VERSION 5.8 ;
BUSBITCHARS "[]" ;
DIVIDERCHAR "/" ;
UNITS
    DATABASE MICRONS 1000 ;
END UNITS

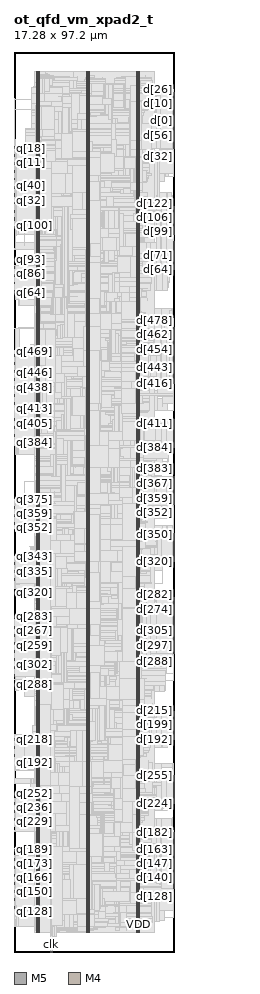
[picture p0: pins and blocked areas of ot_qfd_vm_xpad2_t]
MACRO ot_qfd_vm_xpad2_t
  FOREIGN ot_qfd_vm_xpad2_t 0 0 ;
  CLASS BLOCK ;
  SIZE 17.28 BY 97.2 ;
  PIN clk
    DIRECTION INPUT ;
    USE SIGNAL ;
    PORT
      LAYER M5 ;
        RECT  3.984 0 4.008 0.084 ;
    END
  END clk
  PIN d[0]
    DIRECTION INPUT ;
    USE SIGNAL ;
    PORT
      LAYER M4 ;
        RECT  17.196 89.808 17.28 89.832 ;
    END
  END d[0]
  PIN d[100]
    DIRECTION INPUT ;
    USE SIGNAL ;
    PORT
      LAYER M4 ;
        RECT  17.196 77.904 17.28 77.928 ;
    END
  END d[100]
  PIN d[101]
    DIRECTION INPUT ;
    USE SIGNAL ;
    PORT
      LAYER M4 ;
        RECT  17.196 78 17.28 78.024 ;
    END
  END d[101]
  PIN d[102]
    DIRECTION INPUT ;
    USE SIGNAL ;
    PORT
      LAYER M4 ;
        RECT  17.196 78.096 17.28 78.12 ;
    END
  END d[102]
  PIN d[103]
    DIRECTION INPUT ;
    USE SIGNAL ;
    PORT
      LAYER M4 ;
        RECT  17.196 78.192 17.28 78.216 ;
    END
  END d[103]
  PIN d[104]
    DIRECTION INPUT ;
    USE SIGNAL ;
    PORT
      LAYER M4 ;
        RECT  17.196 78.288 17.28 78.312 ;
    END
  END d[104]
  PIN d[105]
    DIRECTION INPUT ;
    USE SIGNAL ;
    PORT
      LAYER M4 ;
        RECT  17.196 78.384 17.28 78.408 ;
    END
  END d[105]
  PIN d[106]
    DIRECTION INPUT ;
    USE SIGNAL ;
    PORT
      LAYER M4 ;
        RECT  17.196 78.48 17.28 78.504 ;
    END
  END d[106]
  PIN d[107]
    DIRECTION INPUT ;
    USE SIGNAL ;
    PORT
      LAYER M4 ;
        RECT  17.196 78.576 17.28 78.6 ;
    END
  END d[107]
  PIN d[108]
    DIRECTION INPUT ;
    USE SIGNAL ;
    PORT
      LAYER M4 ;
        RECT  17.196 78.672 17.28 78.696 ;
    END
  END d[108]
  PIN d[109]
    DIRECTION INPUT ;
    USE SIGNAL ;
    PORT
      LAYER M4 ;
        RECT  17.196 78.768 17.28 78.792 ;
    END
  END d[109]
  PIN d[10]
    DIRECTION INPUT ;
    USE SIGNAL ;
    PORT
      LAYER M4 ;
        RECT  17.196 90.768 17.28 90.792 ;
    END
  END d[10]
  PIN d[110]
    DIRECTION INPUT ;
    USE SIGNAL ;
    PORT
      LAYER M4 ;
        RECT  17.196 78.864 17.28 78.888 ;
    END
  END d[110]
  PIN d[111]
    DIRECTION INPUT ;
    USE SIGNAL ;
    PORT
      LAYER M4 ;
        RECT  17.196 78.96 17.28 78.984 ;
    END
  END d[111]
  PIN d[112]
    DIRECTION INPUT ;
    USE SIGNAL ;
    PORT
      LAYER M4 ;
        RECT  17.196 79.056 17.28 79.08 ;
    END
  END d[112]
  PIN d[113]
    DIRECTION INPUT ;
    USE SIGNAL ;
    PORT
      LAYER M4 ;
        RECT  17.196 79.152 17.28 79.176 ;
    END
  END d[113]
  PIN d[114]
    DIRECTION INPUT ;
    USE SIGNAL ;
    PORT
      LAYER M4 ;
        RECT  17.196 79.248 17.28 79.272 ;
    END
  END d[114]
  PIN d[115]
    DIRECTION INPUT ;
    USE SIGNAL ;
    PORT
      LAYER M4 ;
        RECT  17.196 79.344 17.28 79.368 ;
    END
  END d[115]
  PIN d[116]
    DIRECTION INPUT ;
    USE SIGNAL ;
    PORT
      LAYER M4 ;
        RECT  17.196 79.44 17.28 79.464 ;
    END
  END d[116]
  PIN d[117]
    DIRECTION INPUT ;
    USE SIGNAL ;
    PORT
      LAYER M4 ;
        RECT  17.196 79.536 17.28 79.56 ;
    END
  END d[117]
  PIN d[118]
    DIRECTION INPUT ;
    USE SIGNAL ;
    PORT
      LAYER M4 ;
        RECT  17.196 79.632 17.28 79.656 ;
    END
  END d[118]
  PIN d[119]
    DIRECTION INPUT ;
    USE SIGNAL ;
    PORT
      LAYER M4 ;
        RECT  17.196 79.728 17.28 79.752 ;
    END
  END d[119]
  PIN d[11]
    DIRECTION INPUT ;
    USE SIGNAL ;
    PORT
      LAYER M4 ;
        RECT  17.196 90.864 17.28 90.888 ;
    END
  END d[11]
  PIN d[120]
    DIRECTION INPUT ;
    USE SIGNAL ;
    PORT
      LAYER M4 ;
        RECT  17.196 79.824 17.28 79.848 ;
    END
  END d[120]
  PIN d[121]
    DIRECTION INPUT ;
    USE SIGNAL ;
    PORT
      LAYER M4 ;
        RECT  17.196 79.92 17.28 79.944 ;
    END
  END d[121]
  PIN d[122]
    DIRECTION INPUT ;
    USE SIGNAL ;
    PORT
      LAYER M4 ;
        RECT  17.196 80.016 17.28 80.04 ;
    END
  END d[122]
  PIN d[123]
    DIRECTION INPUT ;
    USE SIGNAL ;
    PORT
      LAYER M4 ;
        RECT  17.196 80.112 17.28 80.136 ;
    END
  END d[123]
  PIN d[124]
    DIRECTION INPUT ;
    USE SIGNAL ;
    PORT
      LAYER M4 ;
        RECT  17.196 80.208 17.28 80.232 ;
    END
  END d[124]
  PIN d[125]
    DIRECTION INPUT ;
    USE SIGNAL ;
    PORT
      LAYER M4 ;
        RECT  17.196 80.304 17.28 80.328 ;
    END
  END d[125]
  PIN d[126]
    DIRECTION INPUT ;
    USE SIGNAL ;
    PORT
      LAYER M4 ;
        RECT  17.196 80.4 17.28 80.424 ;
    END
  END d[126]
  PIN d[127]
    DIRECTION INPUT ;
    USE SIGNAL ;
    PORT
      LAYER M4 ;
        RECT  17.196 80.496 17.28 80.52 ;
    END
  END d[127]
  PIN d[128]
    DIRECTION INPUT ;
    USE SIGNAL ;
    PORT
      LAYER M4 ;
        RECT  17.196 6.864 17.28 6.888 ;
    END
  END d[128]
  PIN d[129]
    DIRECTION INPUT ;
    USE SIGNAL ;
    PORT
      LAYER M4 ;
        RECT  17.196 6.96 17.28 6.984 ;
    END
  END d[129]
  PIN d[12]
    DIRECTION INPUT ;
    USE SIGNAL ;
    PORT
      LAYER M4 ;
        RECT  17.196 90.96 17.28 90.984 ;
    END
  END d[12]
  PIN d[130]
    DIRECTION INPUT ;
    USE SIGNAL ;
    PORT
      LAYER M4 ;
        RECT  17.196 7.056 17.28 7.08 ;
    END
  END d[130]
  PIN d[131]
    DIRECTION INPUT ;
    USE SIGNAL ;
    PORT
      LAYER M4 ;
        RECT  17.196 7.152 17.28 7.176 ;
    END
  END d[131]
  PIN d[132]
    DIRECTION INPUT ;
    USE SIGNAL ;
    PORT
      LAYER M4 ;
        RECT  17.196 7.248 17.28 7.272 ;
    END
  END d[132]
  PIN d[133]
    DIRECTION INPUT ;
    USE SIGNAL ;
    PORT
      LAYER M4 ;
        RECT  17.196 7.344 17.28 7.368 ;
    END
  END d[133]
  PIN d[134]
    DIRECTION INPUT ;
    USE SIGNAL ;
    PORT
      LAYER M4 ;
        RECT  17.196 7.44 17.28 7.464 ;
    END
  END d[134]
  PIN d[135]
    DIRECTION INPUT ;
    USE SIGNAL ;
    PORT
      LAYER M4 ;
        RECT  17.196 7.536 17.28 7.56 ;
    END
  END d[135]
  PIN d[136]
    DIRECTION INPUT ;
    USE SIGNAL ;
    PORT
      LAYER M4 ;
        RECT  17.196 7.632 17.28 7.656 ;
    END
  END d[136]
  PIN d[137]
    DIRECTION INPUT ;
    USE SIGNAL ;
    PORT
      LAYER M4 ;
        RECT  17.196 7.728 17.28 7.752 ;
    END
  END d[137]
  PIN d[138]
    DIRECTION INPUT ;
    USE SIGNAL ;
    PORT
      LAYER M4 ;
        RECT  17.196 7.824 17.28 7.848 ;
    END
  END d[138]
  PIN d[139]
    DIRECTION INPUT ;
    USE SIGNAL ;
    PORT
      LAYER M4 ;
        RECT  17.196 7.92 17.28 7.944 ;
    END
  END d[139]
  PIN d[13]
    DIRECTION INPUT ;
    USE SIGNAL ;
    PORT
      LAYER M4 ;
        RECT  17.196 91.056 17.28 91.08 ;
    END
  END d[13]
  PIN d[140]
    DIRECTION INPUT ;
    USE SIGNAL ;
    PORT
      LAYER M4 ;
        RECT  17.196 8.016 17.28 8.04 ;
    END
  END d[140]
  PIN d[141]
    DIRECTION INPUT ;
    USE SIGNAL ;
    PORT
      LAYER M4 ;
        RECT  17.196 8.112 17.28 8.136 ;
    END
  END d[141]
  PIN d[142]
    DIRECTION INPUT ;
    USE SIGNAL ;
    PORT
      LAYER M4 ;
        RECT  17.196 8.208 17.28 8.232 ;
    END
  END d[142]
  PIN d[143]
    DIRECTION INPUT ;
    USE SIGNAL ;
    PORT
      LAYER M4 ;
        RECT  17.196 8.304 17.28 8.328 ;
    END
  END d[143]
  PIN d[144]
    DIRECTION INPUT ;
    USE SIGNAL ;
    PORT
      LAYER M4 ;
        RECT  17.196 8.4 17.28 8.424 ;
    END
  END d[144]
  PIN d[145]
    DIRECTION INPUT ;
    USE SIGNAL ;
    PORT
      LAYER M4 ;
        RECT  17.196 8.496 17.28 8.52 ;
    END
  END d[145]
  PIN d[146]
    DIRECTION INPUT ;
    USE SIGNAL ;
    PORT
      LAYER M4 ;
        RECT  17.196 8.592 17.28 8.616 ;
    END
  END d[146]
  PIN d[147]
    DIRECTION INPUT ;
    USE SIGNAL ;
    PORT
      LAYER M4 ;
        RECT  17.196 8.688 17.28 8.712 ;
    END
  END d[147]
  PIN d[148]
    DIRECTION INPUT ;
    USE SIGNAL ;
    PORT
      LAYER M4 ;
        RECT  17.196 8.784 17.28 8.808 ;
    END
  END d[148]
  PIN d[149]
    DIRECTION INPUT ;
    USE SIGNAL ;
    PORT
      LAYER M4 ;
        RECT  17.196 8.88 17.28 8.904 ;
    END
  END d[149]
  PIN d[14]
    DIRECTION INPUT ;
    USE SIGNAL ;
    PORT
      LAYER M4 ;
        RECT  17.196 91.152 17.28 91.176 ;
    END
  END d[14]
  PIN d[150]
    DIRECTION INPUT ;
    USE SIGNAL ;
    PORT
      LAYER M4 ;
        RECT  17.196 8.976 17.28 9 ;
    END
  END d[150]
  PIN d[151]
    DIRECTION INPUT ;
    USE SIGNAL ;
    PORT
      LAYER M4 ;
        RECT  17.196 9.072 17.28 9.096 ;
    END
  END d[151]
  PIN d[152]
    DIRECTION INPUT ;
    USE SIGNAL ;
    PORT
      LAYER M4 ;
        RECT  17.196 9.168 17.28 9.192 ;
    END
  END d[152]
  PIN d[153]
    DIRECTION INPUT ;
    USE SIGNAL ;
    PORT
      LAYER M4 ;
        RECT  17.196 9.264 17.28 9.288 ;
    END
  END d[153]
  PIN d[154]
    DIRECTION INPUT ;
    USE SIGNAL ;
    PORT
      LAYER M4 ;
        RECT  17.196 9.36 17.28 9.384 ;
    END
  END d[154]
  PIN d[155]
    DIRECTION INPUT ;
    USE SIGNAL ;
    PORT
      LAYER M4 ;
        RECT  17.196 9.456 17.28 9.48 ;
    END
  END d[155]
  PIN d[156]
    DIRECTION INPUT ;
    USE SIGNAL ;
    PORT
      LAYER M4 ;
        RECT  17.196 9.552 17.28 9.576 ;
    END
  END d[156]
  PIN d[157]
    DIRECTION INPUT ;
    USE SIGNAL ;
    PORT
      LAYER M4 ;
        RECT  17.196 9.648 17.28 9.672 ;
    END
  END d[157]
  PIN d[158]
    DIRECTION INPUT ;
    USE SIGNAL ;
    PORT
      LAYER M4 ;
        RECT  17.196 9.744 17.28 9.768 ;
    END
  END d[158]
  PIN d[159]
    DIRECTION INPUT ;
    USE SIGNAL ;
    PORT
      LAYER M4 ;
        RECT  17.196 9.84 17.28 9.864 ;
    END
  END d[159]
  PIN d[15]
    DIRECTION INPUT ;
    USE SIGNAL ;
    PORT
      LAYER M4 ;
        RECT  17.196 91.248 17.28 91.272 ;
    END
  END d[15]
  PIN d[160]
    DIRECTION INPUT ;
    USE SIGNAL ;
    PORT
      LAYER M4 ;
        RECT  17.196 9.936 17.28 9.96 ;
    END
  END d[160]
  PIN d[161]
    DIRECTION INPUT ;
    USE SIGNAL ;
    PORT
      LAYER M4 ;
        RECT  17.196 10.032 17.28 10.056 ;
    END
  END d[161]
  PIN d[162]
    DIRECTION INPUT ;
    USE SIGNAL ;
    PORT
      LAYER M4 ;
        RECT  17.196 10.128 17.28 10.152 ;
    END
  END d[162]
  PIN d[163]
    DIRECTION INPUT ;
    USE SIGNAL ;
    PORT
      LAYER M4 ;
        RECT  17.196 10.224 17.28 10.248 ;
    END
  END d[163]
  PIN d[164]
    DIRECTION INPUT ;
    USE SIGNAL ;
    PORT
      LAYER M4 ;
        RECT  17.196 10.32 17.28 10.344 ;
    END
  END d[164]
  PIN d[165]
    DIRECTION INPUT ;
    USE SIGNAL ;
    PORT
      LAYER M4 ;
        RECT  17.196 10.416 17.28 10.44 ;
    END
  END d[165]
  PIN d[166]
    DIRECTION INPUT ;
    USE SIGNAL ;
    PORT
      LAYER M4 ;
        RECT  17.196 10.512 17.28 10.536 ;
    END
  END d[166]
  PIN d[167]
    DIRECTION INPUT ;
    USE SIGNAL ;
    PORT
      LAYER M4 ;
        RECT  17.196 10.608 17.28 10.632 ;
    END
  END d[167]
  PIN d[168]
    DIRECTION INPUT ;
    USE SIGNAL ;
    PORT
      LAYER M4 ;
        RECT  17.196 10.704 17.28 10.728 ;
    END
  END d[168]
  PIN d[169]
    DIRECTION INPUT ;
    USE SIGNAL ;
    PORT
      LAYER M4 ;
        RECT  17.196 10.8 17.28 10.824 ;
    END
  END d[169]
  PIN d[16]
    DIRECTION INPUT ;
    USE SIGNAL ;
    PORT
      LAYER M4 ;
        RECT  17.196 91.344 17.28 91.368 ;
    END
  END d[16]
  PIN d[170]
    DIRECTION INPUT ;
    USE SIGNAL ;
    PORT
      LAYER M4 ;
        RECT  17.196 10.896 17.28 10.92 ;
    END
  END d[170]
  PIN d[171]
    DIRECTION INPUT ;
    USE SIGNAL ;
    PORT
      LAYER M4 ;
        RECT  17.196 10.992 17.28 11.016 ;
    END
  END d[171]
  PIN d[172]
    DIRECTION INPUT ;
    USE SIGNAL ;
    PORT
      LAYER M4 ;
        RECT  17.196 11.088 17.28 11.112 ;
    END
  END d[172]
  PIN d[173]
    DIRECTION INPUT ;
    USE SIGNAL ;
    PORT
      LAYER M4 ;
        RECT  17.196 11.184 17.28 11.208 ;
    END
  END d[173]
  PIN d[174]
    DIRECTION INPUT ;
    USE SIGNAL ;
    PORT
      LAYER M4 ;
        RECT  17.196 11.28 17.28 11.304 ;
    END
  END d[174]
  PIN d[175]
    DIRECTION INPUT ;
    USE SIGNAL ;
    PORT
      LAYER M4 ;
        RECT  17.196 11.376 17.28 11.4 ;
    END
  END d[175]
  PIN d[176]
    DIRECTION INPUT ;
    USE SIGNAL ;
    PORT
      LAYER M4 ;
        RECT  17.196 11.472 17.28 11.496 ;
    END
  END d[176]
  PIN d[177]
    DIRECTION INPUT ;
    USE SIGNAL ;
    PORT
      LAYER M4 ;
        RECT  17.196 11.568 17.28 11.592 ;
    END
  END d[177]
  PIN d[178]
    DIRECTION INPUT ;
    USE SIGNAL ;
    PORT
      LAYER M4 ;
        RECT  17.196 11.664 17.28 11.688 ;
    END
  END d[178]
  PIN d[179]
    DIRECTION INPUT ;
    USE SIGNAL ;
    PORT
      LAYER M4 ;
        RECT  17.196 11.76 17.28 11.784 ;
    END
  END d[179]
  PIN d[17]
    DIRECTION INPUT ;
    USE SIGNAL ;
    PORT
      LAYER M4 ;
        RECT  17.196 91.44 17.28 91.464 ;
    END
  END d[17]
  PIN d[180]
    DIRECTION INPUT ;
    USE SIGNAL ;
    PORT
      LAYER M4 ;
        RECT  17.196 11.856 17.28 11.88 ;
    END
  END d[180]
  PIN d[181]
    DIRECTION INPUT ;
    USE SIGNAL ;
    PORT
      LAYER M4 ;
        RECT  17.196 11.952 17.28 11.976 ;
    END
  END d[181]
  PIN d[182]
    DIRECTION INPUT ;
    USE SIGNAL ;
    PORT
      LAYER M4 ;
        RECT  17.196 12.048 17.28 12.072 ;
    END
  END d[182]
  PIN d[183]
    DIRECTION INPUT ;
    USE SIGNAL ;
    PORT
      LAYER M4 ;
        RECT  17.196 12.144 17.28 12.168 ;
    END
  END d[183]
  PIN d[184]
    DIRECTION INPUT ;
    USE SIGNAL ;
    PORT
      LAYER M4 ;
        RECT  17.196 12.24 17.28 12.264 ;
    END
  END d[184]
  PIN d[185]
    DIRECTION INPUT ;
    USE SIGNAL ;
    PORT
      LAYER M4 ;
        RECT  17.196 12.336 17.28 12.36 ;
    END
  END d[185]
  PIN d[186]
    DIRECTION INPUT ;
    USE SIGNAL ;
    PORT
      LAYER M4 ;
        RECT  17.196 12.432 17.28 12.456 ;
    END
  END d[186]
  PIN d[187]
    DIRECTION INPUT ;
    USE SIGNAL ;
    PORT
      LAYER M4 ;
        RECT  17.196 12.528 17.28 12.552 ;
    END
  END d[187]
  PIN d[188]
    DIRECTION INPUT ;
    USE SIGNAL ;
    PORT
      LAYER M4 ;
        RECT  17.196 12.624 17.28 12.648 ;
    END
  END d[188]
  PIN d[189]
    DIRECTION INPUT ;
    USE SIGNAL ;
    PORT
      LAYER M4 ;
        RECT  17.196 12.72 17.28 12.744 ;
    END
  END d[189]
  PIN d[18]
    DIRECTION INPUT ;
    USE SIGNAL ;
    PORT
      LAYER M4 ;
        RECT  17.196 91.536 17.28 91.56 ;
    END
  END d[18]
  PIN d[190]
    DIRECTION INPUT ;
    USE SIGNAL ;
    PORT
      LAYER M4 ;
        RECT  17.196 12.816 17.28 12.84 ;
    END
  END d[190]
  PIN d[191]
    DIRECTION INPUT ;
    USE SIGNAL ;
    PORT
      LAYER M4 ;
        RECT  17.196 12.912 17.28 12.936 ;
    END
  END d[191]
  PIN d[192]
    DIRECTION INPUT ;
    USE SIGNAL ;
    PORT
      LAYER M4 ;
        RECT  17.196 22.992 17.28 23.016 ;
    END
  END d[192]
  PIN d[193]
    DIRECTION INPUT ;
    USE SIGNAL ;
    PORT
      LAYER M4 ;
        RECT  17.196 23.088 17.28 23.112 ;
    END
  END d[193]
  PIN d[194]
    DIRECTION INPUT ;
    USE SIGNAL ;
    PORT
      LAYER M4 ;
        RECT  17.196 23.184 17.28 23.208 ;
    END
  END d[194]
  PIN d[195]
    DIRECTION INPUT ;
    USE SIGNAL ;
    PORT
      LAYER M4 ;
        RECT  17.196 23.28 17.28 23.304 ;
    END
  END d[195]
  PIN d[196]
    DIRECTION INPUT ;
    USE SIGNAL ;
    PORT
      LAYER M4 ;
        RECT  17.196 23.376 17.28 23.4 ;
    END
  END d[196]
  PIN d[197]
    DIRECTION INPUT ;
    USE SIGNAL ;
    PORT
      LAYER M4 ;
        RECT  17.196 23.472 17.28 23.496 ;
    END
  END d[197]
  PIN d[198]
    DIRECTION INPUT ;
    USE SIGNAL ;
    PORT
      LAYER M4 ;
        RECT  17.196 23.568 17.28 23.592 ;
    END
  END d[198]
  PIN d[199]
    DIRECTION INPUT ;
    USE SIGNAL ;
    PORT
      LAYER M4 ;
        RECT  17.196 23.664 17.28 23.688 ;
    END
  END d[199]
  PIN d[19]
    DIRECTION INPUT ;
    USE SIGNAL ;
    PORT
      LAYER M4 ;
        RECT  17.196 91.632 17.28 91.656 ;
    END
  END d[19]
  PIN d[1]
    DIRECTION INPUT ;
    USE SIGNAL ;
    PORT
      LAYER M4 ;
        RECT  17.196 89.904 17.28 89.928 ;
    END
  END d[1]
  PIN d[200]
    DIRECTION INPUT ;
    USE SIGNAL ;
    PORT
      LAYER M4 ;
        RECT  17.196 23.76 17.28 23.784 ;
    END
  END d[200]
  PIN d[201]
    DIRECTION INPUT ;
    USE SIGNAL ;
    PORT
      LAYER M4 ;
        RECT  17.196 23.856 17.28 23.88 ;
    END
  END d[201]
  PIN d[202]
    DIRECTION INPUT ;
    USE SIGNAL ;
    PORT
      LAYER M4 ;
        RECT  17.196 23.952 17.28 23.976 ;
    END
  END d[202]
  PIN d[203]
    DIRECTION INPUT ;
    USE SIGNAL ;
    PORT
      LAYER M4 ;
        RECT  17.196 24.048 17.28 24.072 ;
    END
  END d[203]
  PIN d[204]
    DIRECTION INPUT ;
    USE SIGNAL ;
    PORT
      LAYER M4 ;
        RECT  17.196 24.144 17.28 24.168 ;
    END
  END d[204]
  PIN d[205]
    DIRECTION INPUT ;
    USE SIGNAL ;
    PORT
      LAYER M4 ;
        RECT  17.196 24.24 17.28 24.264 ;
    END
  END d[205]
  PIN d[206]
    DIRECTION INPUT ;
    USE SIGNAL ;
    PORT
      LAYER M4 ;
        RECT  17.196 24.336 17.28 24.36 ;
    END
  END d[206]
  PIN d[207]
    DIRECTION INPUT ;
    USE SIGNAL ;
    PORT
      LAYER M4 ;
        RECT  17.196 24.432 17.28 24.456 ;
    END
  END d[207]
  PIN d[208]
    DIRECTION INPUT ;
    USE SIGNAL ;
    PORT
      LAYER M4 ;
        RECT  17.196 24.528 17.28 24.552 ;
    END
  END d[208]
  PIN d[209]
    DIRECTION INPUT ;
    USE SIGNAL ;
    PORT
      LAYER M4 ;
        RECT  17.196 24.624 17.28 24.648 ;
    END
  END d[209]
  PIN d[20]
    DIRECTION INPUT ;
    USE SIGNAL ;
    PORT
      LAYER M4 ;
        RECT  17.196 91.728 17.28 91.752 ;
    END
  END d[20]
  PIN d[210]
    DIRECTION INPUT ;
    USE SIGNAL ;
    PORT
      LAYER M4 ;
        RECT  17.196 24.72 17.28 24.744 ;
    END
  END d[210]
  PIN d[211]
    DIRECTION INPUT ;
    USE SIGNAL ;
    PORT
      LAYER M4 ;
        RECT  17.196 24.816 17.28 24.84 ;
    END
  END d[211]
  PIN d[212]
    DIRECTION INPUT ;
    USE SIGNAL ;
    PORT
      LAYER M4 ;
        RECT  17.196 24.912 17.28 24.936 ;
    END
  END d[212]
  PIN d[213]
    DIRECTION INPUT ;
    USE SIGNAL ;
    PORT
      LAYER M4 ;
        RECT  17.196 25.008 17.28 25.032 ;
    END
  END d[213]
  PIN d[214]
    DIRECTION INPUT ;
    USE SIGNAL ;
    PORT
      LAYER M4 ;
        RECT  17.196 25.104 17.28 25.128 ;
    END
  END d[214]
  PIN d[215]
    DIRECTION INPUT ;
    USE SIGNAL ;
    PORT
      LAYER M4 ;
        RECT  17.196 25.2 17.28 25.224 ;
    END
  END d[215]
  PIN d[216]
    DIRECTION INPUT ;
    USE SIGNAL ;
    PORT
      LAYER M4 ;
        RECT  17.196 25.296 17.28 25.32 ;
    END
  END d[216]
  PIN d[217]
    DIRECTION INPUT ;
    USE SIGNAL ;
    PORT
      LAYER M4 ;
        RECT  17.196 25.392 17.28 25.416 ;
    END
  END d[217]
  PIN d[218]
    DIRECTION INPUT ;
    USE SIGNAL ;
    PORT
      LAYER M4 ;
        RECT  17.196 25.488 17.28 25.512 ;
    END
  END d[218]
  PIN d[219]
    DIRECTION INPUT ;
    USE SIGNAL ;
    PORT
      LAYER M4 ;
        RECT  17.196 25.584 17.28 25.608 ;
    END
  END d[219]
  PIN d[21]
    DIRECTION INPUT ;
    USE SIGNAL ;
    PORT
      LAYER M4 ;
        RECT  17.196 91.824 17.28 91.848 ;
    END
  END d[21]
  PIN d[220]
    DIRECTION INPUT ;
    USE SIGNAL ;
    PORT
      LAYER M4 ;
        RECT  17.196 25.68 17.28 25.704 ;
    END
  END d[220]
  PIN d[221]
    DIRECTION INPUT ;
    USE SIGNAL ;
    PORT
      LAYER M4 ;
        RECT  17.196 25.776 17.28 25.8 ;
    END
  END d[221]
  PIN d[222]
    DIRECTION INPUT ;
    USE SIGNAL ;
    PORT
      LAYER M4 ;
        RECT  17.196 25.872 17.28 25.896 ;
    END
  END d[222]
  PIN d[223]
    DIRECTION INPUT ;
    USE SIGNAL ;
    PORT
      LAYER M4 ;
        RECT  17.196 25.968 17.28 25.992 ;
    END
  END d[223]
  PIN d[224]
    DIRECTION INPUT ;
    USE SIGNAL ;
    PORT
      LAYER M4 ;
        RECT  17.196 16.08 17.28 16.104 ;
    END
  END d[224]
  PIN d[225]
    DIRECTION INPUT ;
    USE SIGNAL ;
    PORT
      LAYER M4 ;
        RECT  17.196 16.176 17.28 16.2 ;
    END
  END d[225]
  PIN d[226]
    DIRECTION INPUT ;
    USE SIGNAL ;
    PORT
      LAYER M4 ;
        RECT  17.196 16.272 17.28 16.296 ;
    END
  END d[226]
  PIN d[227]
    DIRECTION INPUT ;
    USE SIGNAL ;
    PORT
      LAYER M4 ;
        RECT  17.196 16.368 17.28 16.392 ;
    END
  END d[227]
  PIN d[228]
    DIRECTION INPUT ;
    USE SIGNAL ;
    PORT
      LAYER M4 ;
        RECT  17.196 16.464 17.28 16.488 ;
    END
  END d[228]
  PIN d[229]
    DIRECTION INPUT ;
    USE SIGNAL ;
    PORT
      LAYER M4 ;
        RECT  17.196 16.56 17.28 16.584 ;
    END
  END d[229]
  PIN d[22]
    DIRECTION INPUT ;
    USE SIGNAL ;
    PORT
      LAYER M4 ;
        RECT  17.196 91.92 17.28 91.944 ;
    END
  END d[22]
  PIN d[230]
    DIRECTION INPUT ;
    USE SIGNAL ;
    PORT
      LAYER M4 ;
        RECT  17.196 16.656 17.28 16.68 ;
    END
  END d[230]
  PIN d[231]
    DIRECTION INPUT ;
    USE SIGNAL ;
    PORT
      LAYER M4 ;
        RECT  17.196 16.752 17.28 16.776 ;
    END
  END d[231]
  PIN d[232]
    DIRECTION INPUT ;
    USE SIGNAL ;
    PORT
      LAYER M4 ;
        RECT  17.196 16.848 17.28 16.872 ;
    END
  END d[232]
  PIN d[233]
    DIRECTION INPUT ;
    USE SIGNAL ;
    PORT
      LAYER M4 ;
        RECT  17.196 16.944 17.28 16.968 ;
    END
  END d[233]
  PIN d[234]
    DIRECTION INPUT ;
    USE SIGNAL ;
    PORT
      LAYER M4 ;
        RECT  17.196 17.04 17.28 17.064 ;
    END
  END d[234]
  PIN d[235]
    DIRECTION INPUT ;
    USE SIGNAL ;
    PORT
      LAYER M4 ;
        RECT  17.196 17.136 17.28 17.16 ;
    END
  END d[235]
  PIN d[236]
    DIRECTION INPUT ;
    USE SIGNAL ;
    PORT
      LAYER M4 ;
        RECT  17.196 17.232 17.28 17.256 ;
    END
  END d[236]
  PIN d[237]
    DIRECTION INPUT ;
    USE SIGNAL ;
    PORT
      LAYER M4 ;
        RECT  17.196 17.328 17.28 17.352 ;
    END
  END d[237]
  PIN d[238]
    DIRECTION INPUT ;
    USE SIGNAL ;
    PORT
      LAYER M4 ;
        RECT  17.196 17.424 17.28 17.448 ;
    END
  END d[238]
  PIN d[239]
    DIRECTION INPUT ;
    USE SIGNAL ;
    PORT
      LAYER M4 ;
        RECT  17.196 17.52 17.28 17.544 ;
    END
  END d[239]
  PIN d[23]
    DIRECTION INPUT ;
    USE SIGNAL ;
    PORT
      LAYER M4 ;
        RECT  17.196 92.016 17.28 92.04 ;
    END
  END d[23]
  PIN d[240]
    DIRECTION INPUT ;
    USE SIGNAL ;
    PORT
      LAYER M4 ;
        RECT  17.196 17.616 17.28 17.64 ;
    END
  END d[240]
  PIN d[241]
    DIRECTION INPUT ;
    USE SIGNAL ;
    PORT
      LAYER M4 ;
        RECT  17.196 17.712 17.28 17.736 ;
    END
  END d[241]
  PIN d[242]
    DIRECTION INPUT ;
    USE SIGNAL ;
    PORT
      LAYER M4 ;
        RECT  17.196 17.808 17.28 17.832 ;
    END
  END d[242]
  PIN d[243]
    DIRECTION INPUT ;
    USE SIGNAL ;
    PORT
      LAYER M4 ;
        RECT  17.196 17.904 17.28 17.928 ;
    END
  END d[243]
  PIN d[244]
    DIRECTION INPUT ;
    USE SIGNAL ;
    PORT
      LAYER M4 ;
        RECT  17.196 18 17.28 18.024 ;
    END
  END d[244]
  PIN d[245]
    DIRECTION INPUT ;
    USE SIGNAL ;
    PORT
      LAYER M4 ;
        RECT  17.196 18.096 17.28 18.12 ;
    END
  END d[245]
  PIN d[246]
    DIRECTION INPUT ;
    USE SIGNAL ;
    PORT
      LAYER M4 ;
        RECT  17.196 18.192 17.28 18.216 ;
    END
  END d[246]
  PIN d[247]
    DIRECTION INPUT ;
    USE SIGNAL ;
    PORT
      LAYER M4 ;
        RECT  17.196 18.288 17.28 18.312 ;
    END
  END d[247]
  PIN d[248]
    DIRECTION INPUT ;
    USE SIGNAL ;
    PORT
      LAYER M4 ;
        RECT  17.196 18.384 17.28 18.408 ;
    END
  END d[248]
  PIN d[249]
    DIRECTION INPUT ;
    USE SIGNAL ;
    PORT
      LAYER M4 ;
        RECT  17.196 18.48 17.28 18.504 ;
    END
  END d[249]
  PIN d[24]
    DIRECTION INPUT ;
    USE SIGNAL ;
    PORT
      LAYER M4 ;
        RECT  17.196 92.112 17.28 92.136 ;
    END
  END d[24]
  PIN d[250]
    DIRECTION INPUT ;
    USE SIGNAL ;
    PORT
      LAYER M4 ;
        RECT  17.196 18.576 17.28 18.6 ;
    END
  END d[250]
  PIN d[251]
    DIRECTION INPUT ;
    USE SIGNAL ;
    PORT
      LAYER M4 ;
        RECT  17.196 18.672 17.28 18.696 ;
    END
  END d[251]
  PIN d[252]
    DIRECTION INPUT ;
    USE SIGNAL ;
    PORT
      LAYER M4 ;
        RECT  17.196 18.768 17.28 18.792 ;
    END
  END d[252]
  PIN d[253]
    DIRECTION INPUT ;
    USE SIGNAL ;
    PORT
      LAYER M4 ;
        RECT  17.196 18.864 17.28 18.888 ;
    END
  END d[253]
  PIN d[254]
    DIRECTION INPUT ;
    USE SIGNAL ;
    PORT
      LAYER M4 ;
        RECT  17.196 18.96 17.28 18.984 ;
    END
  END d[254]
  PIN d[255]
    DIRECTION INPUT ;
    USE SIGNAL ;
    PORT
      LAYER M4 ;
        RECT  17.196 19.056 17.28 19.08 ;
    END
  END d[255]
  PIN d[256]
    DIRECTION INPUT ;
    USE SIGNAL ;
    PORT
      LAYER M4 ;
        RECT  17.196 35.28 17.28 35.304 ;
    END
  END d[256]
  PIN d[257]
    DIRECTION INPUT ;
    USE SIGNAL ;
    PORT
      LAYER M4 ;
        RECT  17.196 35.376 17.28 35.4 ;
    END
  END d[257]
  PIN d[258]
    DIRECTION INPUT ;
    USE SIGNAL ;
    PORT
      LAYER M4 ;
        RECT  17.196 35.472 17.28 35.496 ;
    END
  END d[258]
  PIN d[259]
    DIRECTION INPUT ;
    USE SIGNAL ;
    PORT
      LAYER M4 ;
        RECT  17.196 35.568 17.28 35.592 ;
    END
  END d[259]
  PIN d[25]
    DIRECTION INPUT ;
    USE SIGNAL ;
    PORT
      LAYER M4 ;
        RECT  17.196 92.208 17.28 92.232 ;
    END
  END d[25]
  PIN d[260]
    DIRECTION INPUT ;
    USE SIGNAL ;
    PORT
      LAYER M4 ;
        RECT  17.196 35.664 17.28 35.688 ;
    END
  END d[260]
  PIN d[261]
    DIRECTION INPUT ;
    USE SIGNAL ;
    PORT
      LAYER M4 ;
        RECT  17.196 35.76 17.28 35.784 ;
    END
  END d[261]
  PIN d[262]
    DIRECTION INPUT ;
    USE SIGNAL ;
    PORT
      LAYER M4 ;
        RECT  17.196 35.856 17.28 35.88 ;
    END
  END d[262]
  PIN d[263]
    DIRECTION INPUT ;
    USE SIGNAL ;
    PORT
      LAYER M4 ;
        RECT  17.196 35.952 17.28 35.976 ;
    END
  END d[263]
  PIN d[264]
    DIRECTION INPUT ;
    USE SIGNAL ;
    PORT
      LAYER M4 ;
        RECT  17.196 36.048 17.28 36.072 ;
    END
  END d[264]
  PIN d[265]
    DIRECTION INPUT ;
    USE SIGNAL ;
    PORT
      LAYER M4 ;
        RECT  17.196 36.144 17.28 36.168 ;
    END
  END d[265]
  PIN d[266]
    DIRECTION INPUT ;
    USE SIGNAL ;
    PORT
      LAYER M4 ;
        RECT  17.196 36.24 17.28 36.264 ;
    END
  END d[266]
  PIN d[267]
    DIRECTION INPUT ;
    USE SIGNAL ;
    PORT
      LAYER M4 ;
        RECT  17.196 36.336 17.28 36.36 ;
    END
  END d[267]
  PIN d[268]
    DIRECTION INPUT ;
    USE SIGNAL ;
    PORT
      LAYER M4 ;
        RECT  17.196 36.432 17.28 36.456 ;
    END
  END d[268]
  PIN d[269]
    DIRECTION INPUT ;
    USE SIGNAL ;
    PORT
      LAYER M4 ;
        RECT  17.196 36.528 17.28 36.552 ;
    END
  END d[269]
  PIN d[26]
    DIRECTION INPUT ;
    USE SIGNAL ;
    PORT
      LAYER M4 ;
        RECT  17.196 92.304 17.28 92.328 ;
    END
  END d[26]
  PIN d[270]
    DIRECTION INPUT ;
    USE SIGNAL ;
    PORT
      LAYER M4 ;
        RECT  17.196 36.624 17.28 36.648 ;
    END
  END d[270]
  PIN d[271]
    DIRECTION INPUT ;
    USE SIGNAL ;
    PORT
      LAYER M4 ;
        RECT  17.196 36.72 17.28 36.744 ;
    END
  END d[271]
  PIN d[272]
    DIRECTION INPUT ;
    USE SIGNAL ;
    PORT
      LAYER M4 ;
        RECT  17.196 36.816 17.28 36.84 ;
    END
  END d[272]
  PIN d[273]
    DIRECTION INPUT ;
    USE SIGNAL ;
    PORT
      LAYER M4 ;
        RECT  17.196 36.912 17.28 36.936 ;
    END
  END d[273]
  PIN d[274]
    DIRECTION INPUT ;
    USE SIGNAL ;
    PORT
      LAYER M4 ;
        RECT  17.196 37.008 17.28 37.032 ;
    END
  END d[274]
  PIN d[275]
    DIRECTION INPUT ;
    USE SIGNAL ;
    PORT
      LAYER M4 ;
        RECT  17.196 37.104 17.28 37.128 ;
    END
  END d[275]
  PIN d[276]
    DIRECTION INPUT ;
    USE SIGNAL ;
    PORT
      LAYER M4 ;
        RECT  17.196 37.2 17.28 37.224 ;
    END
  END d[276]
  PIN d[277]
    DIRECTION INPUT ;
    USE SIGNAL ;
    PORT
      LAYER M4 ;
        RECT  17.196 37.296 17.28 37.32 ;
    END
  END d[277]
  PIN d[278]
    DIRECTION INPUT ;
    USE SIGNAL ;
    PORT
      LAYER M4 ;
        RECT  17.196 37.392 17.28 37.416 ;
    END
  END d[278]
  PIN d[279]
    DIRECTION INPUT ;
    USE SIGNAL ;
    PORT
      LAYER M4 ;
        RECT  17.196 37.488 17.28 37.512 ;
    END
  END d[279]
  PIN d[27]
    DIRECTION INPUT ;
    USE SIGNAL ;
    PORT
      LAYER M4 ;
        RECT  17.196 92.4 17.28 92.424 ;
    END
  END d[27]
  PIN d[280]
    DIRECTION INPUT ;
    USE SIGNAL ;
    PORT
      LAYER M4 ;
        RECT  17.196 37.584 17.28 37.608 ;
    END
  END d[280]
  PIN d[281]
    DIRECTION INPUT ;
    USE SIGNAL ;
    PORT
      LAYER M4 ;
        RECT  17.196 37.68 17.28 37.704 ;
    END
  END d[281]
  PIN d[282]
    DIRECTION INPUT ;
    USE SIGNAL ;
    PORT
      LAYER M4 ;
        RECT  17.196 37.776 17.28 37.8 ;
    END
  END d[282]
  PIN d[283]
    DIRECTION INPUT ;
    USE SIGNAL ;
    PORT
      LAYER M4 ;
        RECT  17.196 37.872 17.28 37.896 ;
    END
  END d[283]
  PIN d[284]
    DIRECTION INPUT ;
    USE SIGNAL ;
    PORT
      LAYER M4 ;
        RECT  17.196 37.968 17.28 37.992 ;
    END
  END d[284]
  PIN d[285]
    DIRECTION INPUT ;
    USE SIGNAL ;
    PORT
      LAYER M4 ;
        RECT  17.196 38.064 17.28 38.088 ;
    END
  END d[285]
  PIN d[286]
    DIRECTION INPUT ;
    USE SIGNAL ;
    PORT
      LAYER M4 ;
        RECT  17.196 38.16 17.28 38.184 ;
    END
  END d[286]
  PIN d[287]
    DIRECTION INPUT ;
    USE SIGNAL ;
    PORT
      LAYER M4 ;
        RECT  17.196 38.256 17.28 38.28 ;
    END
  END d[287]
  PIN d[288]
    DIRECTION INPUT ;
    USE SIGNAL ;
    PORT
      LAYER M4 ;
        RECT  17.196 32.208 17.28 32.232 ;
    END
  END d[288]
  PIN d[289]
    DIRECTION INPUT ;
    USE SIGNAL ;
    PORT
      LAYER M4 ;
        RECT  17.196 32.304 17.28 32.328 ;
    END
  END d[289]
  PIN d[28]
    DIRECTION INPUT ;
    USE SIGNAL ;
    PORT
      LAYER M4 ;
        RECT  17.196 92.496 17.28 92.52 ;
    END
  END d[28]
  PIN d[290]
    DIRECTION INPUT ;
    USE SIGNAL ;
    PORT
      LAYER M4 ;
        RECT  17.196 32.4 17.28 32.424 ;
    END
  END d[290]
  PIN d[291]
    DIRECTION INPUT ;
    USE SIGNAL ;
    PORT
      LAYER M4 ;
        RECT  17.196 32.496 17.28 32.52 ;
    END
  END d[291]
  PIN d[292]
    DIRECTION INPUT ;
    USE SIGNAL ;
    PORT
      LAYER M4 ;
        RECT  17.196 32.592 17.28 32.616 ;
    END
  END d[292]
  PIN d[293]
    DIRECTION INPUT ;
    USE SIGNAL ;
    PORT
      LAYER M4 ;
        RECT  17.196 32.688 17.28 32.712 ;
    END
  END d[293]
  PIN d[294]
    DIRECTION INPUT ;
    USE SIGNAL ;
    PORT
      LAYER M4 ;
        RECT  17.196 32.784 17.28 32.808 ;
    END
  END d[294]
  PIN d[295]
    DIRECTION INPUT ;
    USE SIGNAL ;
    PORT
      LAYER M4 ;
        RECT  17.196 32.88 17.28 32.904 ;
    END
  END d[295]
  PIN d[296]
    DIRECTION INPUT ;
    USE SIGNAL ;
    PORT
      LAYER M4 ;
        RECT  17.196 32.976 17.28 33 ;
    END
  END d[296]
  PIN d[297]
    DIRECTION INPUT ;
    USE SIGNAL ;
    PORT
      LAYER M4 ;
        RECT  17.196 33.072 17.28 33.096 ;
    END
  END d[297]
  PIN d[298]
    DIRECTION INPUT ;
    USE SIGNAL ;
    PORT
      LAYER M4 ;
        RECT  17.196 33.168 17.28 33.192 ;
    END
  END d[298]
  PIN d[299]
    DIRECTION INPUT ;
    USE SIGNAL ;
    PORT
      LAYER M4 ;
        RECT  17.196 33.264 17.28 33.288 ;
    END
  END d[299]
  PIN d[29]
    DIRECTION INPUT ;
    USE SIGNAL ;
    PORT
      LAYER M4 ;
        RECT  17.196 92.592 17.28 92.616 ;
    END
  END d[29]
  PIN d[2]
    DIRECTION INPUT ;
    USE SIGNAL ;
    PORT
      LAYER M4 ;
        RECT  17.196 90 17.28 90.024 ;
    END
  END d[2]
  PIN d[300]
    DIRECTION INPUT ;
    USE SIGNAL ;
    PORT
      LAYER M4 ;
        RECT  17.196 33.36 17.28 33.384 ;
    END
  END d[300]
  PIN d[301]
    DIRECTION INPUT ;
    USE SIGNAL ;
    PORT
      LAYER M4 ;
        RECT  17.196 33.456 17.28 33.48 ;
    END
  END d[301]
  PIN d[302]
    DIRECTION INPUT ;
    USE SIGNAL ;
    PORT
      LAYER M4 ;
        RECT  17.196 33.552 17.28 33.576 ;
    END
  END d[302]
  PIN d[303]
    DIRECTION INPUT ;
    USE SIGNAL ;
    PORT
      LAYER M4 ;
        RECT  17.196 33.648 17.28 33.672 ;
    END
  END d[303]
  PIN d[304]
    DIRECTION INPUT ;
    USE SIGNAL ;
    PORT
      LAYER M4 ;
        RECT  17.196 33.744 17.28 33.768 ;
    END
  END d[304]
  PIN d[305]
    DIRECTION INPUT ;
    USE SIGNAL ;
    PORT
      LAYER M4 ;
        RECT  17.196 33.84 17.28 33.864 ;
    END
  END d[305]
  PIN d[306]
    DIRECTION INPUT ;
    USE SIGNAL ;
    PORT
      LAYER M4 ;
        RECT  17.196 33.936 17.28 33.96 ;
    END
  END d[306]
  PIN d[307]
    DIRECTION INPUT ;
    USE SIGNAL ;
    PORT
      LAYER M4 ;
        RECT  17.196 34.032 17.28 34.056 ;
    END
  END d[307]
  PIN d[308]
    DIRECTION INPUT ;
    USE SIGNAL ;
    PORT
      LAYER M4 ;
        RECT  17.196 34.128 17.28 34.152 ;
    END
  END d[308]
  PIN d[309]
    DIRECTION INPUT ;
    USE SIGNAL ;
    PORT
      LAYER M4 ;
        RECT  17.196 34.224 17.28 34.248 ;
    END
  END d[309]
  PIN d[30]
    DIRECTION INPUT ;
    USE SIGNAL ;
    PORT
      LAYER M4 ;
        RECT  17.196 92.688 17.28 92.712 ;
    END
  END d[30]
  PIN d[310]
    DIRECTION INPUT ;
    USE SIGNAL ;
    PORT
      LAYER M4 ;
        RECT  17.196 34.32 17.28 34.344 ;
    END
  END d[310]
  PIN d[311]
    DIRECTION INPUT ;
    USE SIGNAL ;
    PORT
      LAYER M4 ;
        RECT  17.196 34.416 17.28 34.44 ;
    END
  END d[311]
  PIN d[312]
    DIRECTION INPUT ;
    USE SIGNAL ;
    PORT
      LAYER M4 ;
        RECT  17.196 34.512 17.28 34.536 ;
    END
  END d[312]
  PIN d[313]
    DIRECTION INPUT ;
    USE SIGNAL ;
    PORT
      LAYER M4 ;
        RECT  17.196 34.608 17.28 34.632 ;
    END
  END d[313]
  PIN d[314]
    DIRECTION INPUT ;
    USE SIGNAL ;
    PORT
      LAYER M4 ;
        RECT  17.196 34.704 17.28 34.728 ;
    END
  END d[314]
  PIN d[315]
    DIRECTION INPUT ;
    USE SIGNAL ;
    PORT
      LAYER M4 ;
        RECT  17.196 34.8 17.28 34.824 ;
    END
  END d[315]
  PIN d[316]
    DIRECTION INPUT ;
    USE SIGNAL ;
    PORT
      LAYER M4 ;
        RECT  17.196 34.896 17.28 34.92 ;
    END
  END d[316]
  PIN d[317]
    DIRECTION INPUT ;
    USE SIGNAL ;
    PORT
      LAYER M4 ;
        RECT  17.196 34.992 17.28 35.016 ;
    END
  END d[317]
  PIN d[318]
    DIRECTION INPUT ;
    USE SIGNAL ;
    PORT
      LAYER M4 ;
        RECT  17.196 35.088 17.28 35.112 ;
    END
  END d[318]
  PIN d[319]
    DIRECTION INPUT ;
    USE SIGNAL ;
    PORT
      LAYER M4 ;
        RECT  17.196 35.184 17.28 35.208 ;
    END
  END d[319]
  PIN d[31]
    DIRECTION INPUT ;
    USE SIGNAL ;
    PORT
      LAYER M4 ;
        RECT  17.196 92.784 17.28 92.808 ;
    END
  END d[31]
  PIN d[320]
    DIRECTION INPUT ;
    USE SIGNAL ;
    PORT
      LAYER M4 ;
        RECT  17.196 42.192 17.28 42.216 ;
    END
  END d[320]
  PIN d[321]
    DIRECTION INPUT ;
    USE SIGNAL ;
    PORT
      LAYER M4 ;
        RECT  17.196 42.288 17.28 42.312 ;
    END
  END d[321]
  PIN d[322]
    DIRECTION INPUT ;
    USE SIGNAL ;
    PORT
      LAYER M4 ;
        RECT  17.196 42.384 17.28 42.408 ;
    END
  END d[322]
  PIN d[323]
    DIRECTION INPUT ;
    USE SIGNAL ;
    PORT
      LAYER M4 ;
        RECT  17.196 42.48 17.28 42.504 ;
    END
  END d[323]
  PIN d[324]
    DIRECTION INPUT ;
    USE SIGNAL ;
    PORT
      LAYER M4 ;
        RECT  17.196 42.576 17.28 42.6 ;
    END
  END d[324]
  PIN d[325]
    DIRECTION INPUT ;
    USE SIGNAL ;
    PORT
      LAYER M4 ;
        RECT  17.196 42.672 17.28 42.696 ;
    END
  END d[325]
  PIN d[326]
    DIRECTION INPUT ;
    USE SIGNAL ;
    PORT
      LAYER M4 ;
        RECT  17.196 42.768 17.28 42.792 ;
    END
  END d[326]
  PIN d[327]
    DIRECTION INPUT ;
    USE SIGNAL ;
    PORT
      LAYER M4 ;
        RECT  17.196 42.864 17.28 42.888 ;
    END
  END d[327]
  PIN d[328]
    DIRECTION INPUT ;
    USE SIGNAL ;
    PORT
      LAYER M4 ;
        RECT  17.196 42.96 17.28 42.984 ;
    END
  END d[328]
  PIN d[329]
    DIRECTION INPUT ;
    USE SIGNAL ;
    PORT
      LAYER M4 ;
        RECT  17.196 43.056 17.28 43.08 ;
    END
  END d[329]
  PIN d[32]
    DIRECTION INPUT ;
    USE SIGNAL ;
    PORT
      LAYER M4 ;
        RECT  17.196 86.736 17.28 86.76 ;
    END
  END d[32]
  PIN d[330]
    DIRECTION INPUT ;
    USE SIGNAL ;
    PORT
      LAYER M4 ;
        RECT  17.196 43.152 17.28 43.176 ;
    END
  END d[330]
  PIN d[331]
    DIRECTION INPUT ;
    USE SIGNAL ;
    PORT
      LAYER M4 ;
        RECT  17.196 43.248 17.28 43.272 ;
    END
  END d[331]
  PIN d[332]
    DIRECTION INPUT ;
    USE SIGNAL ;
    PORT
      LAYER M4 ;
        RECT  17.196 43.344 17.28 43.368 ;
    END
  END d[332]
  PIN d[333]
    DIRECTION INPUT ;
    USE SIGNAL ;
    PORT
      LAYER M4 ;
        RECT  17.196 43.44 17.28 43.464 ;
    END
  END d[333]
  PIN d[334]
    DIRECTION INPUT ;
    USE SIGNAL ;
    PORT
      LAYER M4 ;
        RECT  17.196 43.536 17.28 43.56 ;
    END
  END d[334]
  PIN d[335]
    DIRECTION INPUT ;
    USE SIGNAL ;
    PORT
      LAYER M4 ;
        RECT  17.196 43.632 17.28 43.656 ;
    END
  END d[335]
  PIN d[336]
    DIRECTION INPUT ;
    USE SIGNAL ;
    PORT
      LAYER M4 ;
        RECT  17.196 43.728 17.28 43.752 ;
    END
  END d[336]
  PIN d[337]
    DIRECTION INPUT ;
    USE SIGNAL ;
    PORT
      LAYER M4 ;
        RECT  17.196 43.824 17.28 43.848 ;
    END
  END d[337]
  PIN d[338]
    DIRECTION INPUT ;
    USE SIGNAL ;
    PORT
      LAYER M4 ;
        RECT  17.196 43.92 17.28 43.944 ;
    END
  END d[338]
  PIN d[339]
    DIRECTION INPUT ;
    USE SIGNAL ;
    PORT
      LAYER M4 ;
        RECT  17.196 44.016 17.28 44.04 ;
    END
  END d[339]
  PIN d[33]
    DIRECTION INPUT ;
    USE SIGNAL ;
    PORT
      LAYER M4 ;
        RECT  17.196 86.832 17.28 86.856 ;
    END
  END d[33]
  PIN d[340]
    DIRECTION INPUT ;
    USE SIGNAL ;
    PORT
      LAYER M4 ;
        RECT  17.196 44.112 17.28 44.136 ;
    END
  END d[340]
  PIN d[341]
    DIRECTION INPUT ;
    USE SIGNAL ;
    PORT
      LAYER M4 ;
        RECT  17.196 44.208 17.28 44.232 ;
    END
  END d[341]
  PIN d[342]
    DIRECTION INPUT ;
    USE SIGNAL ;
    PORT
      LAYER M4 ;
        RECT  17.196 44.304 17.28 44.328 ;
    END
  END d[342]
  PIN d[343]
    DIRECTION INPUT ;
    USE SIGNAL ;
    PORT
      LAYER M4 ;
        RECT  17.196 44.4 17.28 44.424 ;
    END
  END d[343]
  PIN d[344]
    DIRECTION INPUT ;
    USE SIGNAL ;
    PORT
      LAYER M4 ;
        RECT  17.196 44.496 17.28 44.52 ;
    END
  END d[344]
  PIN d[345]
    DIRECTION INPUT ;
    USE SIGNAL ;
    PORT
      LAYER M4 ;
        RECT  17.196 44.592 17.28 44.616 ;
    END
  END d[345]
  PIN d[346]
    DIRECTION INPUT ;
    USE SIGNAL ;
    PORT
      LAYER M4 ;
        RECT  17.196 44.688 17.28 44.712 ;
    END
  END d[346]
  PIN d[347]
    DIRECTION INPUT ;
    USE SIGNAL ;
    PORT
      LAYER M4 ;
        RECT  17.196 44.784 17.28 44.808 ;
    END
  END d[347]
  PIN d[348]
    DIRECTION INPUT ;
    USE SIGNAL ;
    PORT
      LAYER M4 ;
        RECT  17.196 44.88 17.28 44.904 ;
    END
  END d[348]
  PIN d[349]
    DIRECTION INPUT ;
    USE SIGNAL ;
    PORT
      LAYER M4 ;
        RECT  17.196 44.976 17.28 45 ;
    END
  END d[349]
  PIN d[34]
    DIRECTION INPUT ;
    USE SIGNAL ;
    PORT
      LAYER M4 ;
        RECT  17.196 86.928 17.28 86.952 ;
    END
  END d[34]
  PIN d[350]
    DIRECTION INPUT ;
    USE SIGNAL ;
    PORT
      LAYER M4 ;
        RECT  17.196 45.072 17.28 45.096 ;
    END
  END d[350]
  PIN d[351]
    DIRECTION INPUT ;
    USE SIGNAL ;
    PORT
      LAYER M4 ;
        RECT  17.196 45.168 17.28 45.192 ;
    END
  END d[351]
  PIN d[352]
    DIRECTION INPUT ;
    USE SIGNAL ;
    PORT
      LAYER M4 ;
        RECT  17.196 48.336 17.28 48.36 ;
    END
  END d[352]
  PIN d[353]
    DIRECTION INPUT ;
    USE SIGNAL ;
    PORT
      LAYER M4 ;
        RECT  17.196 48.432 17.28 48.456 ;
    END
  END d[353]
  PIN d[354]
    DIRECTION INPUT ;
    USE SIGNAL ;
    PORT
      LAYER M4 ;
        RECT  17.196 48.528 17.28 48.552 ;
    END
  END d[354]
  PIN d[355]
    DIRECTION INPUT ;
    USE SIGNAL ;
    PORT
      LAYER M4 ;
        RECT  17.196 48.624 17.28 48.648 ;
    END
  END d[355]
  PIN d[356]
    DIRECTION INPUT ;
    USE SIGNAL ;
    PORT
      LAYER M4 ;
        RECT  17.196 48.72 17.28 48.744 ;
    END
  END d[356]
  PIN d[357]
    DIRECTION INPUT ;
    USE SIGNAL ;
    PORT
      LAYER M4 ;
        RECT  17.196 48.816 17.28 48.84 ;
    END
  END d[357]
  PIN d[358]
    DIRECTION INPUT ;
    USE SIGNAL ;
    PORT
      LAYER M4 ;
        RECT  17.196 48.912 17.28 48.936 ;
    END
  END d[358]
  PIN d[359]
    DIRECTION INPUT ;
    USE SIGNAL ;
    PORT
      LAYER M4 ;
        RECT  17.196 49.008 17.28 49.032 ;
    END
  END d[359]
  PIN d[35]
    DIRECTION INPUT ;
    USE SIGNAL ;
    PORT
      LAYER M4 ;
        RECT  17.196 87.024 17.28 87.048 ;
    END
  END d[35]
  PIN d[360]
    DIRECTION INPUT ;
    USE SIGNAL ;
    PORT
      LAYER M4 ;
        RECT  17.196 49.104 17.28 49.128 ;
    END
  END d[360]
  PIN d[361]
    DIRECTION INPUT ;
    USE SIGNAL ;
    PORT
      LAYER M4 ;
        RECT  17.196 49.2 17.28 49.224 ;
    END
  END d[361]
  PIN d[362]
    DIRECTION INPUT ;
    USE SIGNAL ;
    PORT
      LAYER M4 ;
        RECT  17.196 49.296 17.28 49.32 ;
    END
  END d[362]
  PIN d[363]
    DIRECTION INPUT ;
    USE SIGNAL ;
    PORT
      LAYER M4 ;
        RECT  17.196 49.392 17.28 49.416 ;
    END
  END d[363]
  PIN d[364]
    DIRECTION INPUT ;
    USE SIGNAL ;
    PORT
      LAYER M4 ;
        RECT  17.196 49.488 17.28 49.512 ;
    END
  END d[364]
  PIN d[365]
    DIRECTION INPUT ;
    USE SIGNAL ;
    PORT
      LAYER M4 ;
        RECT  17.196 49.584 17.28 49.608 ;
    END
  END d[365]
  PIN d[366]
    DIRECTION INPUT ;
    USE SIGNAL ;
    PORT
      LAYER M4 ;
        RECT  17.196 49.68 17.28 49.704 ;
    END
  END d[366]
  PIN d[367]
    DIRECTION INPUT ;
    USE SIGNAL ;
    PORT
      LAYER M4 ;
        RECT  17.196 49.776 17.28 49.8 ;
    END
  END d[367]
  PIN d[368]
    DIRECTION INPUT ;
    USE SIGNAL ;
    PORT
      LAYER M4 ;
        RECT  17.196 49.872 17.28 49.896 ;
    END
  END d[368]
  PIN d[369]
    DIRECTION INPUT ;
    USE SIGNAL ;
    PORT
      LAYER M4 ;
        RECT  17.196 49.968 17.28 49.992 ;
    END
  END d[369]
  PIN d[36]
    DIRECTION INPUT ;
    USE SIGNAL ;
    PORT
      LAYER M4 ;
        RECT  17.196 87.12 17.28 87.144 ;
    END
  END d[36]
  PIN d[370]
    DIRECTION INPUT ;
    USE SIGNAL ;
    PORT
      LAYER M4 ;
        RECT  17.196 50.064 17.28 50.088 ;
    END
  END d[370]
  PIN d[371]
    DIRECTION INPUT ;
    USE SIGNAL ;
    PORT
      LAYER M4 ;
        RECT  17.196 50.16 17.28 50.184 ;
    END
  END d[371]
  PIN d[372]
    DIRECTION INPUT ;
    USE SIGNAL ;
    PORT
      LAYER M4 ;
        RECT  17.196 50.256 17.28 50.28 ;
    END
  END d[372]
  PIN d[373]
    DIRECTION INPUT ;
    USE SIGNAL ;
    PORT
      LAYER M4 ;
        RECT  17.196 50.352 17.28 50.376 ;
    END
  END d[373]
  PIN d[374]
    DIRECTION INPUT ;
    USE SIGNAL ;
    PORT
      LAYER M4 ;
        RECT  17.196 50.448 17.28 50.472 ;
    END
  END d[374]
  PIN d[375]
    DIRECTION INPUT ;
    USE SIGNAL ;
    PORT
      LAYER M4 ;
        RECT  17.196 50.544 17.28 50.568 ;
    END
  END d[375]
  PIN d[376]
    DIRECTION INPUT ;
    USE SIGNAL ;
    PORT
      LAYER M4 ;
        RECT  17.196 50.64 17.28 50.664 ;
    END
  END d[376]
  PIN d[377]
    DIRECTION INPUT ;
    USE SIGNAL ;
    PORT
      LAYER M4 ;
        RECT  17.196 50.736 17.28 50.76 ;
    END
  END d[377]
  PIN d[378]
    DIRECTION INPUT ;
    USE SIGNAL ;
    PORT
      LAYER M4 ;
        RECT  17.196 50.832 17.28 50.856 ;
    END
  END d[378]
  PIN d[379]
    DIRECTION INPUT ;
    USE SIGNAL ;
    PORT
      LAYER M4 ;
        RECT  17.196 50.928 17.28 50.952 ;
    END
  END d[379]
  PIN d[37]
    DIRECTION INPUT ;
    USE SIGNAL ;
    PORT
      LAYER M4 ;
        RECT  17.196 87.216 17.28 87.24 ;
    END
  END d[37]
  PIN d[380]
    DIRECTION INPUT ;
    USE SIGNAL ;
    PORT
      LAYER M4 ;
        RECT  17.196 51.024 17.28 51.048 ;
    END
  END d[380]
  PIN d[381]
    DIRECTION INPUT ;
    USE SIGNAL ;
    PORT
      LAYER M4 ;
        RECT  17.196 51.12 17.28 51.144 ;
    END
  END d[381]
  PIN d[382]
    DIRECTION INPUT ;
    USE SIGNAL ;
    PORT
      LAYER M4 ;
        RECT  17.196 51.216 17.28 51.24 ;
    END
  END d[382]
  PIN d[383]
    DIRECTION INPUT ;
    USE SIGNAL ;
    PORT
      LAYER M4 ;
        RECT  17.196 51.312 17.28 51.336 ;
    END
  END d[383]
  PIN d[384]
    DIRECTION INPUT ;
    USE SIGNAL ;
    PORT
      LAYER M4 ;
        RECT  17.196 54.48 17.28 54.504 ;
    END
  END d[384]
  PIN d[385]
    DIRECTION INPUT ;
    USE SIGNAL ;
    PORT
      LAYER M4 ;
        RECT  17.196 54.576 17.28 54.6 ;
    END
  END d[385]
  PIN d[386]
    DIRECTION INPUT ;
    USE SIGNAL ;
    PORT
      LAYER M4 ;
        RECT  17.196 54.672 17.28 54.696 ;
    END
  END d[386]
  PIN d[387]
    DIRECTION INPUT ;
    USE SIGNAL ;
    PORT
      LAYER M4 ;
        RECT  17.196 54.768 17.28 54.792 ;
    END
  END d[387]
  PIN d[388]
    DIRECTION INPUT ;
    USE SIGNAL ;
    PORT
      LAYER M4 ;
        RECT  17.196 54.864 17.28 54.888 ;
    END
  END d[388]
  PIN d[389]
    DIRECTION INPUT ;
    USE SIGNAL ;
    PORT
      LAYER M4 ;
        RECT  17.196 54.96 17.28 54.984 ;
    END
  END d[389]
  PIN d[38]
    DIRECTION INPUT ;
    USE SIGNAL ;
    PORT
      LAYER M4 ;
        RECT  17.196 87.312 17.28 87.336 ;
    END
  END d[38]
  PIN d[390]
    DIRECTION INPUT ;
    USE SIGNAL ;
    PORT
      LAYER M4 ;
        RECT  17.196 55.056 17.28 55.08 ;
    END
  END d[390]
  PIN d[391]
    DIRECTION INPUT ;
    USE SIGNAL ;
    PORT
      LAYER M4 ;
        RECT  17.196 55.152 17.28 55.176 ;
    END
  END d[391]
  PIN d[392]
    DIRECTION INPUT ;
    USE SIGNAL ;
    PORT
      LAYER M4 ;
        RECT  17.196 55.248 17.28 55.272 ;
    END
  END d[392]
  PIN d[393]
    DIRECTION INPUT ;
    USE SIGNAL ;
    PORT
      LAYER M4 ;
        RECT  17.196 55.344 17.28 55.368 ;
    END
  END d[393]
  PIN d[394]
    DIRECTION INPUT ;
    USE SIGNAL ;
    PORT
      LAYER M4 ;
        RECT  17.196 55.44 17.28 55.464 ;
    END
  END d[394]
  PIN d[395]
    DIRECTION INPUT ;
    USE SIGNAL ;
    PORT
      LAYER M4 ;
        RECT  17.196 55.536 17.28 55.56 ;
    END
  END d[395]
  PIN d[396]
    DIRECTION INPUT ;
    USE SIGNAL ;
    PORT
      LAYER M4 ;
        RECT  17.196 55.632 17.28 55.656 ;
    END
  END d[396]
  PIN d[397]
    DIRECTION INPUT ;
    USE SIGNAL ;
    PORT
      LAYER M4 ;
        RECT  17.196 55.728 17.28 55.752 ;
    END
  END d[397]
  PIN d[398]
    DIRECTION INPUT ;
    USE SIGNAL ;
    PORT
      LAYER M4 ;
        RECT  17.196 55.824 17.28 55.848 ;
    END
  END d[398]
  PIN d[399]
    DIRECTION INPUT ;
    USE SIGNAL ;
    PORT
      LAYER M4 ;
        RECT  17.196 55.92 17.28 55.944 ;
    END
  END d[399]
  PIN d[39]
    DIRECTION INPUT ;
    USE SIGNAL ;
    PORT
      LAYER M4 ;
        RECT  17.196 87.408 17.28 87.432 ;
    END
  END d[39]
  PIN d[3]
    DIRECTION INPUT ;
    USE SIGNAL ;
    PORT
      LAYER M4 ;
        RECT  17.196 90.096 17.28 90.12 ;
    END
  END d[3]
  PIN d[400]
    DIRECTION INPUT ;
    USE SIGNAL ;
    PORT
      LAYER M4 ;
        RECT  17.196 56.016 17.28 56.04 ;
    END
  END d[400]
  PIN d[401]
    DIRECTION INPUT ;
    USE SIGNAL ;
    PORT
      LAYER M4 ;
        RECT  17.196 56.112 17.28 56.136 ;
    END
  END d[401]
  PIN d[402]
    DIRECTION INPUT ;
    USE SIGNAL ;
    PORT
      LAYER M4 ;
        RECT  17.196 56.208 17.28 56.232 ;
    END
  END d[402]
  PIN d[403]
    DIRECTION INPUT ;
    USE SIGNAL ;
    PORT
      LAYER M4 ;
        RECT  17.196 56.304 17.28 56.328 ;
    END
  END d[403]
  PIN d[404]
    DIRECTION INPUT ;
    USE SIGNAL ;
    PORT
      LAYER M4 ;
        RECT  17.196 56.4 17.28 56.424 ;
    END
  END d[404]
  PIN d[405]
    DIRECTION INPUT ;
    USE SIGNAL ;
    PORT
      LAYER M4 ;
        RECT  17.196 56.496 17.28 56.52 ;
    END
  END d[405]
  PIN d[406]
    DIRECTION INPUT ;
    USE SIGNAL ;
    PORT
      LAYER M4 ;
        RECT  17.196 56.592 17.28 56.616 ;
    END
  END d[406]
  PIN d[407]
    DIRECTION INPUT ;
    USE SIGNAL ;
    PORT
      LAYER M4 ;
        RECT  17.196 56.688 17.28 56.712 ;
    END
  END d[407]
  PIN d[408]
    DIRECTION INPUT ;
    USE SIGNAL ;
    PORT
      LAYER M4 ;
        RECT  17.196 56.784 17.28 56.808 ;
    END
  END d[408]
  PIN d[409]
    DIRECTION INPUT ;
    USE SIGNAL ;
    PORT
      LAYER M4 ;
        RECT  17.196 56.88 17.28 56.904 ;
    END
  END d[409]
  PIN d[40]
    DIRECTION INPUT ;
    USE SIGNAL ;
    PORT
      LAYER M4 ;
        RECT  17.196 87.504 17.28 87.528 ;
    END
  END d[40]
  PIN d[410]
    DIRECTION INPUT ;
    USE SIGNAL ;
    PORT
      LAYER M4 ;
        RECT  17.196 56.976 17.28 57 ;
    END
  END d[410]
  PIN d[411]
    DIRECTION INPUT ;
    USE SIGNAL ;
    PORT
      LAYER M4 ;
        RECT  17.196 57.072 17.28 57.096 ;
    END
  END d[411]
  PIN d[412]
    DIRECTION INPUT ;
    USE SIGNAL ;
    PORT
      LAYER M4 ;
        RECT  17.196 57.168 17.28 57.192 ;
    END
  END d[412]
  PIN d[413]
    DIRECTION INPUT ;
    USE SIGNAL ;
    PORT
      LAYER M4 ;
        RECT  17.196 57.264 17.28 57.288 ;
    END
  END d[413]
  PIN d[414]
    DIRECTION INPUT ;
    USE SIGNAL ;
    PORT
      LAYER M4 ;
        RECT  17.196 57.36 17.28 57.384 ;
    END
  END d[414]
  PIN d[415]
    DIRECTION INPUT ;
    USE SIGNAL ;
    PORT
      LAYER M4 ;
        RECT  17.196 57.456 17.28 57.48 ;
    END
  END d[415]
  PIN d[416]
    DIRECTION INPUT ;
    USE SIGNAL ;
    PORT
      LAYER M4 ;
        RECT  17.196 61.392 17.28 61.416 ;
    END
  END d[416]
  PIN d[417]
    DIRECTION INPUT ;
    USE SIGNAL ;
    PORT
      LAYER M4 ;
        RECT  17.196 61.488 17.28 61.512 ;
    END
  END d[417]
  PIN d[418]
    DIRECTION INPUT ;
    USE SIGNAL ;
    PORT
      LAYER M4 ;
        RECT  17.196 61.584 17.28 61.608 ;
    END
  END d[418]
  PIN d[419]
    DIRECTION INPUT ;
    USE SIGNAL ;
    PORT
      LAYER M4 ;
        RECT  17.196 61.68 17.28 61.704 ;
    END
  END d[419]
  PIN d[41]
    DIRECTION INPUT ;
    USE SIGNAL ;
    PORT
      LAYER M4 ;
        RECT  17.196 87.6 17.28 87.624 ;
    END
  END d[41]
  PIN d[420]
    DIRECTION INPUT ;
    USE SIGNAL ;
    PORT
      LAYER M4 ;
        RECT  17.196 61.776 17.28 61.8 ;
    END
  END d[420]
  PIN d[421]
    DIRECTION INPUT ;
    USE SIGNAL ;
    PORT
      LAYER M4 ;
        RECT  17.196 61.872 17.28 61.896 ;
    END
  END d[421]
  PIN d[422]
    DIRECTION INPUT ;
    USE SIGNAL ;
    PORT
      LAYER M4 ;
        RECT  17.196 61.968 17.28 61.992 ;
    END
  END d[422]
  PIN d[423]
    DIRECTION INPUT ;
    USE SIGNAL ;
    PORT
      LAYER M4 ;
        RECT  17.196 62.064 17.28 62.088 ;
    END
  END d[423]
  PIN d[424]
    DIRECTION INPUT ;
    USE SIGNAL ;
    PORT
      LAYER M4 ;
        RECT  17.196 62.16 17.28 62.184 ;
    END
  END d[424]
  PIN d[425]
    DIRECTION INPUT ;
    USE SIGNAL ;
    PORT
      LAYER M4 ;
        RECT  17.196 62.256 17.28 62.28 ;
    END
  END d[425]
  PIN d[426]
    DIRECTION INPUT ;
    USE SIGNAL ;
    PORT
      LAYER M4 ;
        RECT  17.196 62.352 17.28 62.376 ;
    END
  END d[426]
  PIN d[427]
    DIRECTION INPUT ;
    USE SIGNAL ;
    PORT
      LAYER M4 ;
        RECT  17.196 62.448 17.28 62.472 ;
    END
  END d[427]
  PIN d[428]
    DIRECTION INPUT ;
    USE SIGNAL ;
    PORT
      LAYER M4 ;
        RECT  17.196 62.544 17.28 62.568 ;
    END
  END d[428]
  PIN d[429]
    DIRECTION INPUT ;
    USE SIGNAL ;
    PORT
      LAYER M4 ;
        RECT  17.196 62.64 17.28 62.664 ;
    END
  END d[429]
  PIN d[42]
    DIRECTION INPUT ;
    USE SIGNAL ;
    PORT
      LAYER M4 ;
        RECT  17.196 87.696 17.28 87.72 ;
    END
  END d[42]
  PIN d[430]
    DIRECTION INPUT ;
    USE SIGNAL ;
    PORT
      LAYER M4 ;
        RECT  17.196 62.736 17.28 62.76 ;
    END
  END d[430]
  PIN d[431]
    DIRECTION INPUT ;
    USE SIGNAL ;
    PORT
      LAYER M4 ;
        RECT  17.196 62.832 17.28 62.856 ;
    END
  END d[431]
  PIN d[432]
    DIRECTION INPUT ;
    USE SIGNAL ;
    PORT
      LAYER M4 ;
        RECT  17.196 62.928 17.28 62.952 ;
    END
  END d[432]
  PIN d[433]
    DIRECTION INPUT ;
    USE SIGNAL ;
    PORT
      LAYER M4 ;
        RECT  17.196 63.024 17.28 63.048 ;
    END
  END d[433]
  PIN d[434]
    DIRECTION INPUT ;
    USE SIGNAL ;
    PORT
      LAYER M4 ;
        RECT  17.196 63.12 17.28 63.144 ;
    END
  END d[434]
  PIN d[435]
    DIRECTION INPUT ;
    USE SIGNAL ;
    PORT
      LAYER M4 ;
        RECT  17.196 63.216 17.28 63.24 ;
    END
  END d[435]
  PIN d[436]
    DIRECTION INPUT ;
    USE SIGNAL ;
    PORT
      LAYER M4 ;
        RECT  17.196 63.312 17.28 63.336 ;
    END
  END d[436]
  PIN d[437]
    DIRECTION INPUT ;
    USE SIGNAL ;
    PORT
      LAYER M4 ;
        RECT  17.196 63.408 17.28 63.432 ;
    END
  END d[437]
  PIN d[438]
    DIRECTION INPUT ;
    USE SIGNAL ;
    PORT
      LAYER M4 ;
        RECT  17.196 63.504 17.28 63.528 ;
    END
  END d[438]
  PIN d[439]
    DIRECTION INPUT ;
    USE SIGNAL ;
    PORT
      LAYER M4 ;
        RECT  17.196 63.6 17.28 63.624 ;
    END
  END d[439]
  PIN d[43]
    DIRECTION INPUT ;
    USE SIGNAL ;
    PORT
      LAYER M4 ;
        RECT  17.196 87.792 17.28 87.816 ;
    END
  END d[43]
  PIN d[440]
    DIRECTION INPUT ;
    USE SIGNAL ;
    PORT
      LAYER M4 ;
        RECT  17.196 63.696 17.28 63.72 ;
    END
  END d[440]
  PIN d[441]
    DIRECTION INPUT ;
    USE SIGNAL ;
    PORT
      LAYER M4 ;
        RECT  17.196 63.792 17.28 63.816 ;
    END
  END d[441]
  PIN d[442]
    DIRECTION INPUT ;
    USE SIGNAL ;
    PORT
      LAYER M4 ;
        RECT  17.196 63.888 17.28 63.912 ;
    END
  END d[442]
  PIN d[443]
    DIRECTION INPUT ;
    USE SIGNAL ;
    PORT
      LAYER M4 ;
        RECT  17.196 63.984 17.28 64.008 ;
    END
  END d[443]
  PIN d[444]
    DIRECTION INPUT ;
    USE SIGNAL ;
    PORT
      LAYER M4 ;
        RECT  17.196 64.08 17.28 64.104 ;
    END
  END d[444]
  PIN d[445]
    DIRECTION INPUT ;
    USE SIGNAL ;
    PORT
      LAYER M4 ;
        RECT  17.196 64.176 17.28 64.2 ;
    END
  END d[445]
  PIN d[446]
    DIRECTION INPUT ;
    USE SIGNAL ;
    PORT
      LAYER M4 ;
        RECT  17.196 64.272 17.28 64.296 ;
    END
  END d[446]
  PIN d[447]
    DIRECTION INPUT ;
    USE SIGNAL ;
    PORT
      LAYER M4 ;
        RECT  17.196 64.368 17.28 64.392 ;
    END
  END d[447]
  PIN d[448]
    DIRECTION INPUT ;
    USE SIGNAL ;
    PORT
      LAYER M4 ;
        RECT  17.196 64.464 17.28 64.488 ;
    END
  END d[448]
  PIN d[449]
    DIRECTION INPUT ;
    USE SIGNAL ;
    PORT
      LAYER M4 ;
        RECT  17.196 64.56 17.28 64.584 ;
    END
  END d[449]
  PIN d[44]
    DIRECTION INPUT ;
    USE SIGNAL ;
    PORT
      LAYER M4 ;
        RECT  17.196 87.888 17.28 87.912 ;
    END
  END d[44]
  PIN d[450]
    DIRECTION INPUT ;
    USE SIGNAL ;
    PORT
      LAYER M4 ;
        RECT  17.196 64.656 17.28 64.68 ;
    END
  END d[450]
  PIN d[451]
    DIRECTION INPUT ;
    USE SIGNAL ;
    PORT
      LAYER M4 ;
        RECT  17.196 64.752 17.28 64.776 ;
    END
  END d[451]
  PIN d[452]
    DIRECTION INPUT ;
    USE SIGNAL ;
    PORT
      LAYER M4 ;
        RECT  17.196 64.848 17.28 64.872 ;
    END
  END d[452]
  PIN d[453]
    DIRECTION INPUT ;
    USE SIGNAL ;
    PORT
      LAYER M4 ;
        RECT  17.196 64.944 17.28 64.968 ;
    END
  END d[453]
  PIN d[454]
    DIRECTION INPUT ;
    USE SIGNAL ;
    PORT
      LAYER M4 ;
        RECT  17.196 65.04 17.28 65.064 ;
    END
  END d[454]
  PIN d[455]
    DIRECTION INPUT ;
    USE SIGNAL ;
    PORT
      LAYER M4 ;
        RECT  17.196 65.136 17.28 65.16 ;
    END
  END d[455]
  PIN d[456]
    DIRECTION INPUT ;
    USE SIGNAL ;
    PORT
      LAYER M4 ;
        RECT  17.196 65.232 17.28 65.256 ;
    END
  END d[456]
  PIN d[457]
    DIRECTION INPUT ;
    USE SIGNAL ;
    PORT
      LAYER M4 ;
        RECT  17.196 65.328 17.28 65.352 ;
    END
  END d[457]
  PIN d[458]
    DIRECTION INPUT ;
    USE SIGNAL ;
    PORT
      LAYER M4 ;
        RECT  17.196 65.424 17.28 65.448 ;
    END
  END d[458]
  PIN d[459]
    DIRECTION INPUT ;
    USE SIGNAL ;
    PORT
      LAYER M4 ;
        RECT  17.196 65.52 17.28 65.544 ;
    END
  END d[459]
  PIN d[45]
    DIRECTION INPUT ;
    USE SIGNAL ;
    PORT
      LAYER M4 ;
        RECT  17.196 87.984 17.28 88.008 ;
    END
  END d[45]
  PIN d[460]
    DIRECTION INPUT ;
    USE SIGNAL ;
    PORT
      LAYER M4 ;
        RECT  17.196 65.616 17.28 65.64 ;
    END
  END d[460]
  PIN d[461]
    DIRECTION INPUT ;
    USE SIGNAL ;
    PORT
      LAYER M4 ;
        RECT  17.196 65.712 17.28 65.736 ;
    END
  END d[461]
  PIN d[462]
    DIRECTION INPUT ;
    USE SIGNAL ;
    PORT
      LAYER M4 ;
        RECT  17.196 65.808 17.28 65.832 ;
    END
  END d[462]
  PIN d[463]
    DIRECTION INPUT ;
    USE SIGNAL ;
    PORT
      LAYER M4 ;
        RECT  17.196 65.904 17.28 65.928 ;
    END
  END d[463]
  PIN d[464]
    DIRECTION INPUT ;
    USE SIGNAL ;
    PORT
      LAYER M4 ;
        RECT  17.196 66 17.28 66.024 ;
    END
  END d[464]
  PIN d[465]
    DIRECTION INPUT ;
    USE SIGNAL ;
    PORT
      LAYER M4 ;
        RECT  17.196 66.096 17.28 66.12 ;
    END
  END d[465]
  PIN d[466]
    DIRECTION INPUT ;
    USE SIGNAL ;
    PORT
      LAYER M4 ;
        RECT  17.196 66.192 17.28 66.216 ;
    END
  END d[466]
  PIN d[467]
    DIRECTION INPUT ;
    USE SIGNAL ;
    PORT
      LAYER M4 ;
        RECT  17.196 66.288 17.28 66.312 ;
    END
  END d[467]
  PIN d[468]
    DIRECTION INPUT ;
    USE SIGNAL ;
    PORT
      LAYER M4 ;
        RECT  17.196 66.384 17.28 66.408 ;
    END
  END d[468]
  PIN d[469]
    DIRECTION INPUT ;
    USE SIGNAL ;
    PORT
      LAYER M4 ;
        RECT  17.196 66.48 17.28 66.504 ;
    END
  END d[469]
  PIN d[46]
    DIRECTION INPUT ;
    USE SIGNAL ;
    PORT
      LAYER M4 ;
        RECT  17.196 88.08 17.28 88.104 ;
    END
  END d[46]
  PIN d[470]
    DIRECTION INPUT ;
    USE SIGNAL ;
    PORT
      LAYER M4 ;
        RECT  17.196 66.576 17.28 66.6 ;
    END
  END d[470]
  PIN d[471]
    DIRECTION INPUT ;
    USE SIGNAL ;
    PORT
      LAYER M4 ;
        RECT  17.196 66.672 17.28 66.696 ;
    END
  END d[471]
  PIN d[472]
    DIRECTION INPUT ;
    USE SIGNAL ;
    PORT
      LAYER M4 ;
        RECT  17.196 66.768 17.28 66.792 ;
    END
  END d[472]
  PIN d[473]
    DIRECTION INPUT ;
    USE SIGNAL ;
    PORT
      LAYER M4 ;
        RECT  17.196 66.864 17.28 66.888 ;
    END
  END d[473]
  PIN d[474]
    DIRECTION INPUT ;
    USE SIGNAL ;
    PORT
      LAYER M4 ;
        RECT  17.196 66.96 17.28 66.984 ;
    END
  END d[474]
  PIN d[475]
    DIRECTION INPUT ;
    USE SIGNAL ;
    PORT
      LAYER M4 ;
        RECT  17.196 67.056 17.28 67.08 ;
    END
  END d[475]
  PIN d[476]
    DIRECTION INPUT ;
    USE SIGNAL ;
    PORT
      LAYER M4 ;
        RECT  17.196 67.152 17.28 67.176 ;
    END
  END d[476]
  PIN d[477]
    DIRECTION INPUT ;
    USE SIGNAL ;
    PORT
      LAYER M4 ;
        RECT  17.196 67.248 17.28 67.272 ;
    END
  END d[477]
  PIN d[478]
    DIRECTION INPUT ;
    USE SIGNAL ;
    PORT
      LAYER M4 ;
        RECT  17.196 67.344 17.28 67.368 ;
    END
  END d[478]
  PIN d[479]
    DIRECTION INPUT ;
    USE SIGNAL ;
    PORT
      LAYER M4 ;
        RECT  17.196 67.44 17.28 67.464 ;
    END
  END d[479]
  PIN d[47]
    DIRECTION INPUT ;
    USE SIGNAL ;
    PORT
      LAYER M4 ;
        RECT  17.196 88.176 17.28 88.2 ;
    END
  END d[47]
  PIN d[48]
    DIRECTION INPUT ;
    USE SIGNAL ;
    PORT
      LAYER M4 ;
        RECT  17.196 88.272 17.28 88.296 ;
    END
  END d[48]
  PIN d[49]
    DIRECTION INPUT ;
    USE SIGNAL ;
    PORT
      LAYER M4 ;
        RECT  17.196 88.368 17.28 88.392 ;
    END
  END d[49]
  PIN d[4]
    DIRECTION INPUT ;
    USE SIGNAL ;
    PORT
      LAYER M4 ;
        RECT  17.196 90.192 17.28 90.216 ;
    END
  END d[4]
  PIN d[50]
    DIRECTION INPUT ;
    USE SIGNAL ;
    PORT
      LAYER M4 ;
        RECT  17.196 88.464 17.28 88.488 ;
    END
  END d[50]
  PIN d[51]
    DIRECTION INPUT ;
    USE SIGNAL ;
    PORT
      LAYER M4 ;
        RECT  17.196 88.56 17.28 88.584 ;
    END
  END d[51]
  PIN d[52]
    DIRECTION INPUT ;
    USE SIGNAL ;
    PORT
      LAYER M4 ;
        RECT  17.196 88.656 17.28 88.68 ;
    END
  END d[52]
  PIN d[53]
    DIRECTION INPUT ;
    USE SIGNAL ;
    PORT
      LAYER M4 ;
        RECT  17.196 88.752 17.28 88.776 ;
    END
  END d[53]
  PIN d[54]
    DIRECTION INPUT ;
    USE SIGNAL ;
    PORT
      LAYER M4 ;
        RECT  17.196 88.848 17.28 88.872 ;
    END
  END d[54]
  PIN d[55]
    DIRECTION INPUT ;
    USE SIGNAL ;
    PORT
      LAYER M4 ;
        RECT  17.196 88.944 17.28 88.968 ;
    END
  END d[55]
  PIN d[56]
    DIRECTION INPUT ;
    USE SIGNAL ;
    PORT
      LAYER M4 ;
        RECT  17.196 89.04 17.28 89.064 ;
    END
  END d[56]
  PIN d[57]
    DIRECTION INPUT ;
    USE SIGNAL ;
    PORT
      LAYER M4 ;
        RECT  17.196 89.136 17.28 89.16 ;
    END
  END d[57]
  PIN d[58]
    DIRECTION INPUT ;
    USE SIGNAL ;
    PORT
      LAYER M4 ;
        RECT  17.196 89.232 17.28 89.256 ;
    END
  END d[58]
  PIN d[59]
    DIRECTION INPUT ;
    USE SIGNAL ;
    PORT
      LAYER M4 ;
        RECT  17.196 89.328 17.28 89.352 ;
    END
  END d[59]
  PIN d[5]
    DIRECTION INPUT ;
    USE SIGNAL ;
    PORT
      LAYER M4 ;
        RECT  17.196 90.288 17.28 90.312 ;
    END
  END d[5]
  PIN d[60]
    DIRECTION INPUT ;
    USE SIGNAL ;
    PORT
      LAYER M4 ;
        RECT  17.196 89.424 17.28 89.448 ;
    END
  END d[60]
  PIN d[61]
    DIRECTION INPUT ;
    USE SIGNAL ;
    PORT
      LAYER M4 ;
        RECT  17.196 89.52 17.28 89.544 ;
    END
  END d[61]
  PIN d[62]
    DIRECTION INPUT ;
    USE SIGNAL ;
    PORT
      LAYER M4 ;
        RECT  17.196 89.616 17.28 89.64 ;
    END
  END d[62]
  PIN d[63]
    DIRECTION INPUT ;
    USE SIGNAL ;
    PORT
      LAYER M4 ;
        RECT  17.196 89.712 17.28 89.736 ;
    END
  END d[63]
  PIN d[64]
    DIRECTION INPUT ;
    USE SIGNAL ;
    PORT
      LAYER M4 ;
        RECT  17.196 73.68 17.28 73.704 ;
    END
  END d[64]
  PIN d[65]
    DIRECTION INPUT ;
    USE SIGNAL ;
    PORT
      LAYER M4 ;
        RECT  17.196 73.776 17.28 73.8 ;
    END
  END d[65]
  PIN d[66]
    DIRECTION INPUT ;
    USE SIGNAL ;
    PORT
      LAYER M4 ;
        RECT  17.196 73.872 17.28 73.896 ;
    END
  END d[66]
  PIN d[67]
    DIRECTION INPUT ;
    USE SIGNAL ;
    PORT
      LAYER M4 ;
        RECT  17.196 73.968 17.28 73.992 ;
    END
  END d[67]
  PIN d[68]
    DIRECTION INPUT ;
    USE SIGNAL ;
    PORT
      LAYER M4 ;
        RECT  17.196 74.064 17.28 74.088 ;
    END
  END d[68]
  PIN d[69]
    DIRECTION INPUT ;
    USE SIGNAL ;
    PORT
      LAYER M4 ;
        RECT  17.196 74.16 17.28 74.184 ;
    END
  END d[69]
  PIN d[6]
    DIRECTION INPUT ;
    USE SIGNAL ;
    PORT
      LAYER M4 ;
        RECT  17.196 90.384 17.28 90.408 ;
    END
  END d[6]
  PIN d[70]
    DIRECTION INPUT ;
    USE SIGNAL ;
    PORT
      LAYER M4 ;
        RECT  17.196 74.256 17.28 74.28 ;
    END
  END d[70]
  PIN d[71]
    DIRECTION INPUT ;
    USE SIGNAL ;
    PORT
      LAYER M4 ;
        RECT  17.196 74.352 17.28 74.376 ;
    END
  END d[71]
  PIN d[72]
    DIRECTION INPUT ;
    USE SIGNAL ;
    PORT
      LAYER M4 ;
        RECT  17.196 74.448 17.28 74.472 ;
    END
  END d[72]
  PIN d[73]
    DIRECTION INPUT ;
    USE SIGNAL ;
    PORT
      LAYER M4 ;
        RECT  17.196 74.544 17.28 74.568 ;
    END
  END d[73]
  PIN d[74]
    DIRECTION INPUT ;
    USE SIGNAL ;
    PORT
      LAYER M4 ;
        RECT  17.196 74.64 17.28 74.664 ;
    END
  END d[74]
  PIN d[75]
    DIRECTION INPUT ;
    USE SIGNAL ;
    PORT
      LAYER M4 ;
        RECT  17.196 74.736 17.28 74.76 ;
    END
  END d[75]
  PIN d[76]
    DIRECTION INPUT ;
    USE SIGNAL ;
    PORT
      LAYER M4 ;
        RECT  17.196 74.832 17.28 74.856 ;
    END
  END d[76]
  PIN d[77]
    DIRECTION INPUT ;
    USE SIGNAL ;
    PORT
      LAYER M4 ;
        RECT  17.196 74.928 17.28 74.952 ;
    END
  END d[77]
  PIN d[78]
    DIRECTION INPUT ;
    USE SIGNAL ;
    PORT
      LAYER M4 ;
        RECT  17.196 75.024 17.28 75.048 ;
    END
  END d[78]
  PIN d[79]
    DIRECTION INPUT ;
    USE SIGNAL ;
    PORT
      LAYER M4 ;
        RECT  17.196 75.12 17.28 75.144 ;
    END
  END d[79]
  PIN d[7]
    DIRECTION INPUT ;
    USE SIGNAL ;
    PORT
      LAYER M4 ;
        RECT  17.196 90.48 17.28 90.504 ;
    END
  END d[7]
  PIN d[80]
    DIRECTION INPUT ;
    USE SIGNAL ;
    PORT
      LAYER M4 ;
        RECT  17.196 75.216 17.28 75.24 ;
    END
  END d[80]
  PIN d[81]
    DIRECTION INPUT ;
    USE SIGNAL ;
    PORT
      LAYER M4 ;
        RECT  17.196 75.312 17.28 75.336 ;
    END
  END d[81]
  PIN d[82]
    DIRECTION INPUT ;
    USE SIGNAL ;
    PORT
      LAYER M4 ;
        RECT  17.196 75.408 17.28 75.432 ;
    END
  END d[82]
  PIN d[83]
    DIRECTION INPUT ;
    USE SIGNAL ;
    PORT
      LAYER M4 ;
        RECT  17.196 75.504 17.28 75.528 ;
    END
  END d[83]
  PIN d[84]
    DIRECTION INPUT ;
    USE SIGNAL ;
    PORT
      LAYER M4 ;
        RECT  17.196 75.6 17.28 75.624 ;
    END
  END d[84]
  PIN d[85]
    DIRECTION INPUT ;
    USE SIGNAL ;
    PORT
      LAYER M4 ;
        RECT  17.196 75.696 17.28 75.72 ;
    END
  END d[85]
  PIN d[86]
    DIRECTION INPUT ;
    USE SIGNAL ;
    PORT
      LAYER M4 ;
        RECT  17.196 75.792 17.28 75.816 ;
    END
  END d[86]
  PIN d[87]
    DIRECTION INPUT ;
    USE SIGNAL ;
    PORT
      LAYER M4 ;
        RECT  17.196 75.888 17.28 75.912 ;
    END
  END d[87]
  PIN d[88]
    DIRECTION INPUT ;
    USE SIGNAL ;
    PORT
      LAYER M4 ;
        RECT  17.196 75.984 17.28 76.008 ;
    END
  END d[88]
  PIN d[89]
    DIRECTION INPUT ;
    USE SIGNAL ;
    PORT
      LAYER M4 ;
        RECT  17.196 76.08 17.28 76.104 ;
    END
  END d[89]
  PIN d[8]
    DIRECTION INPUT ;
    USE SIGNAL ;
    PORT
      LAYER M4 ;
        RECT  17.196 90.576 17.28 90.6 ;
    END
  END d[8]
  PIN d[90]
    DIRECTION INPUT ;
    USE SIGNAL ;
    PORT
      LAYER M4 ;
        RECT  17.196 76.176 17.28 76.2 ;
    END
  END d[90]
  PIN d[91]
    DIRECTION INPUT ;
    USE SIGNAL ;
    PORT
      LAYER M4 ;
        RECT  17.196 76.272 17.28 76.296 ;
    END
  END d[91]
  PIN d[92]
    DIRECTION INPUT ;
    USE SIGNAL ;
    PORT
      LAYER M4 ;
        RECT  17.196 76.368 17.28 76.392 ;
    END
  END d[92]
  PIN d[93]
    DIRECTION INPUT ;
    USE SIGNAL ;
    PORT
      LAYER M4 ;
        RECT  17.196 76.464 17.28 76.488 ;
    END
  END d[93]
  PIN d[94]
    DIRECTION INPUT ;
    USE SIGNAL ;
    PORT
      LAYER M4 ;
        RECT  17.196 76.56 17.28 76.584 ;
    END
  END d[94]
  PIN d[95]
    DIRECTION INPUT ;
    USE SIGNAL ;
    PORT
      LAYER M4 ;
        RECT  17.196 76.656 17.28 76.68 ;
    END
  END d[95]
  PIN d[96]
    DIRECTION INPUT ;
    USE SIGNAL ;
    PORT
      LAYER M4 ;
        RECT  17.196 77.52 17.28 77.544 ;
    END
  END d[96]
  PIN d[97]
    DIRECTION INPUT ;
    USE SIGNAL ;
    PORT
      LAYER M4 ;
        RECT  17.196 77.616 17.28 77.64 ;
    END
  END d[97]
  PIN d[98]
    DIRECTION INPUT ;
    USE SIGNAL ;
    PORT
      LAYER M4 ;
        RECT  17.196 77.712 17.28 77.736 ;
    END
  END d[98]
  PIN d[99]
    DIRECTION INPUT ;
    USE SIGNAL ;
    PORT
      LAYER M4 ;
        RECT  17.196 77.808 17.28 77.832 ;
    END
  END d[99]
  PIN d[9]
    DIRECTION INPUT ;
    USE SIGNAL ;
    PORT
      LAYER M4 ;
        RECT  17.196 90.672 17.28 90.696 ;
    END
  END d[9]
  PIN me_e
    DIRECTION INPUT ;
    USE SIGNAL ;
    PORT
      LAYER M5 ;
        RECT  4.08 0 4.104 0.084 ;
    END
  END me_e
  PIN q[0]
    DIRECTION OUTPUT ;
    USE SIGNAL ;
    PORT
      LAYER M4 ;
        RECT  0 84.24 0.084 84.264 ;
    END
  END q[0]
  PIN q[100]
    DIRECTION OUTPUT ;
    USE SIGNAL ;
    PORT
      LAYER M4 ;
        RECT  0 78.48 0.084 78.504 ;
    END
  END q[100]
  PIN q[101]
    DIRECTION OUTPUT ;
    USE SIGNAL ;
    PORT
      LAYER M4 ;
        RECT  0 78.576 0.084 78.6 ;
    END
  END q[101]
  PIN q[102]
    DIRECTION OUTPUT ;
    USE SIGNAL ;
    PORT
      LAYER M4 ;
        RECT  0 78.672 0.084 78.696 ;
    END
  END q[102]
  PIN q[103]
    DIRECTION OUTPUT ;
    USE SIGNAL ;
    PORT
      LAYER M4 ;
        RECT  0 78.768 0.084 78.792 ;
    END
  END q[103]
  PIN q[104]
    DIRECTION OUTPUT ;
    USE SIGNAL ;
    PORT
      LAYER M4 ;
        RECT  0 78.864 0.084 78.888 ;
    END
  END q[104]
  PIN q[105]
    DIRECTION OUTPUT ;
    USE SIGNAL ;
    PORT
      LAYER M4 ;
        RECT  0 78.96 0.084 78.984 ;
    END
  END q[105]
  PIN q[106]
    DIRECTION OUTPUT ;
    USE SIGNAL ;
    PORT
      LAYER M4 ;
        RECT  0 79.056 0.084 79.08 ;
    END
  END q[106]
  PIN q[107]
    DIRECTION OUTPUT ;
    USE SIGNAL ;
    PORT
      LAYER M4 ;
        RECT  0 79.152 0.084 79.176 ;
    END
  END q[107]
  PIN q[108]
    DIRECTION OUTPUT ;
    USE SIGNAL ;
    PORT
      LAYER M4 ;
        RECT  0 79.248 0.084 79.272 ;
    END
  END q[108]
  PIN q[109]
    DIRECTION OUTPUT ;
    USE SIGNAL ;
    PORT
      LAYER M4 ;
        RECT  0 79.344 0.084 79.368 ;
    END
  END q[109]
  PIN q[10]
    DIRECTION OUTPUT ;
    USE SIGNAL ;
    PORT
      LAYER M4 ;
        RECT  0 85.2 0.084 85.224 ;
    END
  END q[10]
  PIN q[110]
    DIRECTION OUTPUT ;
    USE SIGNAL ;
    PORT
      LAYER M4 ;
        RECT  0 79.44 0.084 79.464 ;
    END
  END q[110]
  PIN q[111]
    DIRECTION OUTPUT ;
    USE SIGNAL ;
    PORT
      LAYER M4 ;
        RECT  0 79.536 0.084 79.56 ;
    END
  END q[111]
  PIN q[112]
    DIRECTION OUTPUT ;
    USE SIGNAL ;
    PORT
      LAYER M4 ;
        RECT  0 79.632 0.084 79.656 ;
    END
  END q[112]
  PIN q[113]
    DIRECTION OUTPUT ;
    USE SIGNAL ;
    PORT
      LAYER M4 ;
        RECT  0 79.728 0.084 79.752 ;
    END
  END q[113]
  PIN q[114]
    DIRECTION OUTPUT ;
    USE SIGNAL ;
    PORT
      LAYER M4 ;
        RECT  0 79.824 0.084 79.848 ;
    END
  END q[114]
  PIN q[115]
    DIRECTION OUTPUT ;
    USE SIGNAL ;
    PORT
      LAYER M4 ;
        RECT  0 79.92 0.084 79.944 ;
    END
  END q[115]
  PIN q[116]
    DIRECTION OUTPUT ;
    USE SIGNAL ;
    PORT
      LAYER M4 ;
        RECT  0 80.016 0.084 80.04 ;
    END
  END q[116]
  PIN q[117]
    DIRECTION OUTPUT ;
    USE SIGNAL ;
    PORT
      LAYER M4 ;
        RECT  0 80.112 0.084 80.136 ;
    END
  END q[117]
  PIN q[118]
    DIRECTION OUTPUT ;
    USE SIGNAL ;
    PORT
      LAYER M4 ;
        RECT  0 80.208 0.084 80.232 ;
    END
  END q[118]
  PIN q[119]
    DIRECTION OUTPUT ;
    USE SIGNAL ;
    PORT
      LAYER M4 ;
        RECT  0 80.304 0.084 80.328 ;
    END
  END q[119]
  PIN q[11]
    DIRECTION OUTPUT ;
    USE SIGNAL ;
    PORT
      LAYER M4 ;
        RECT  0 85.296 0.084 85.32 ;
    END
  END q[11]
  PIN q[120]
    DIRECTION OUTPUT ;
    USE SIGNAL ;
    PORT
      LAYER M4 ;
        RECT  0 80.4 0.084 80.424 ;
    END
  END q[120]
  PIN q[121]
    DIRECTION OUTPUT ;
    USE SIGNAL ;
    PORT
      LAYER M4 ;
        RECT  0 80.496 0.084 80.52 ;
    END
  END q[121]
  PIN q[122]
    DIRECTION OUTPUT ;
    USE SIGNAL ;
    PORT
      LAYER M4 ;
        RECT  0 80.592 0.084 80.616 ;
    END
  END q[122]
  PIN q[123]
    DIRECTION OUTPUT ;
    USE SIGNAL ;
    PORT
      LAYER M4 ;
        RECT  0 80.688 0.084 80.712 ;
    END
  END q[123]
  PIN q[124]
    DIRECTION OUTPUT ;
    USE SIGNAL ;
    PORT
      LAYER M4 ;
        RECT  0 80.784 0.084 80.808 ;
    END
  END q[124]
  PIN q[125]
    DIRECTION OUTPUT ;
    USE SIGNAL ;
    PORT
      LAYER M4 ;
        RECT  0 80.88 0.084 80.904 ;
    END
  END q[125]
  PIN q[126]
    DIRECTION OUTPUT ;
    USE SIGNAL ;
    PORT
      LAYER M4 ;
        RECT  0 80.976 0.084 81 ;
    END
  END q[126]
  PIN q[127]
    DIRECTION OUTPUT ;
    USE SIGNAL ;
    PORT
      LAYER M4 ;
        RECT  0 81.072 0.084 81.096 ;
    END
  END q[127]
  PIN q[128]
    DIRECTION OUTPUT ;
    USE SIGNAL ;
    PORT
      LAYER M4 ;
        RECT  0 4.368 0.084 4.392 ;
    END
  END q[128]
  PIN q[129]
    DIRECTION OUTPUT ;
    USE SIGNAL ;
    PORT
      LAYER M4 ;
        RECT  0 4.464 0.084 4.488 ;
    END
  END q[129]
  PIN q[12]
    DIRECTION OUTPUT ;
    USE SIGNAL ;
    PORT
      LAYER M4 ;
        RECT  0 85.392 0.084 85.416 ;
    END
  END q[12]
  PIN q[130]
    DIRECTION OUTPUT ;
    USE SIGNAL ;
    PORT
      LAYER M4 ;
        RECT  0 4.56 0.084 4.584 ;
    END
  END q[130]
  PIN q[131]
    DIRECTION OUTPUT ;
    USE SIGNAL ;
    PORT
      LAYER M4 ;
        RECT  0 4.656 0.084 4.68 ;
    END
  END q[131]
  PIN q[132]
    DIRECTION OUTPUT ;
    USE SIGNAL ;
    PORT
      LAYER M4 ;
        RECT  0 4.752 0.084 4.776 ;
    END
  END q[132]
  PIN q[133]
    DIRECTION OUTPUT ;
    USE SIGNAL ;
    PORT
      LAYER M4 ;
        RECT  0 4.848 0.084 4.872 ;
    END
  END q[133]
  PIN q[134]
    DIRECTION OUTPUT ;
    USE SIGNAL ;
    PORT
      LAYER M4 ;
        RECT  0 4.944 0.084 4.968 ;
    END
  END q[134]
  PIN q[135]
    DIRECTION OUTPUT ;
    USE SIGNAL ;
    PORT
      LAYER M4 ;
        RECT  0 5.04 0.084 5.064 ;
    END
  END q[135]
  PIN q[136]
    DIRECTION OUTPUT ;
    USE SIGNAL ;
    PORT
      LAYER M4 ;
        RECT  0 5.136 0.084 5.16 ;
    END
  END q[136]
  PIN q[137]
    DIRECTION OUTPUT ;
    USE SIGNAL ;
    PORT
      LAYER M4 ;
        RECT  0 5.232 0.084 5.256 ;
    END
  END q[137]
  PIN q[138]
    DIRECTION OUTPUT ;
    USE SIGNAL ;
    PORT
      LAYER M4 ;
        RECT  0 5.328 0.084 5.352 ;
    END
  END q[138]
  PIN q[139]
    DIRECTION OUTPUT ;
    USE SIGNAL ;
    PORT
      LAYER M4 ;
        RECT  0 5.424 0.084 5.448 ;
    END
  END q[139]
  PIN q[13]
    DIRECTION OUTPUT ;
    USE SIGNAL ;
    PORT
      LAYER M4 ;
        RECT  0 85.488 0.084 85.512 ;
    END
  END q[13]
  PIN q[140]
    DIRECTION OUTPUT ;
    USE SIGNAL ;
    PORT
      LAYER M4 ;
        RECT  0 5.52 0.084 5.544 ;
    END
  END q[140]
  PIN q[141]
    DIRECTION OUTPUT ;
    USE SIGNAL ;
    PORT
      LAYER M4 ;
        RECT  0 5.616 0.084 5.64 ;
    END
  END q[141]
  PIN q[142]
    DIRECTION OUTPUT ;
    USE SIGNAL ;
    PORT
      LAYER M4 ;
        RECT  0 5.712 0.084 5.736 ;
    END
  END q[142]
  PIN q[143]
    DIRECTION OUTPUT ;
    USE SIGNAL ;
    PORT
      LAYER M4 ;
        RECT  0 5.808 0.084 5.832 ;
    END
  END q[143]
  PIN q[144]
    DIRECTION OUTPUT ;
    USE SIGNAL ;
    PORT
      LAYER M4 ;
        RECT  0 5.904 0.084 5.928 ;
    END
  END q[144]
  PIN q[145]
    DIRECTION OUTPUT ;
    USE SIGNAL ;
    PORT
      LAYER M4 ;
        RECT  0 6 0.084 6.024 ;
    END
  END q[145]
  PIN q[146]
    DIRECTION OUTPUT ;
    USE SIGNAL ;
    PORT
      LAYER M4 ;
        RECT  0 6.096 0.084 6.12 ;
    END
  END q[146]
  PIN q[147]
    DIRECTION OUTPUT ;
    USE SIGNAL ;
    PORT
      LAYER M4 ;
        RECT  0 6.192 0.084 6.216 ;
    END
  END q[147]
  PIN q[148]
    DIRECTION OUTPUT ;
    USE SIGNAL ;
    PORT
      LAYER M4 ;
        RECT  0 6.288 0.084 6.312 ;
    END
  END q[148]
  PIN q[149]
    DIRECTION OUTPUT ;
    USE SIGNAL ;
    PORT
      LAYER M4 ;
        RECT  0 6.384 0.084 6.408 ;
    END
  END q[149]
  PIN q[14]
    DIRECTION OUTPUT ;
    USE SIGNAL ;
    PORT
      LAYER M4 ;
        RECT  0 85.584 0.084 85.608 ;
    END
  END q[14]
  PIN q[150]
    DIRECTION OUTPUT ;
    USE SIGNAL ;
    PORT
      LAYER M4 ;
        RECT  0 6.48 0.084 6.504 ;
    END
  END q[150]
  PIN q[151]
    DIRECTION OUTPUT ;
    USE SIGNAL ;
    PORT
      LAYER M4 ;
        RECT  0 6.576 0.084 6.6 ;
    END
  END q[151]
  PIN q[152]
    DIRECTION OUTPUT ;
    USE SIGNAL ;
    PORT
      LAYER M4 ;
        RECT  0 6.672 0.084 6.696 ;
    END
  END q[152]
  PIN q[153]
    DIRECTION OUTPUT ;
    USE SIGNAL ;
    PORT
      LAYER M4 ;
        RECT  0 6.768 0.084 6.792 ;
    END
  END q[153]
  PIN q[154]
    DIRECTION OUTPUT ;
    USE SIGNAL ;
    PORT
      LAYER M4 ;
        RECT  0 6.864 0.084 6.888 ;
    END
  END q[154]
  PIN q[155]
    DIRECTION OUTPUT ;
    USE SIGNAL ;
    PORT
      LAYER M4 ;
        RECT  0 6.96 0.084 6.984 ;
    END
  END q[155]
  PIN q[156]
    DIRECTION OUTPUT ;
    USE SIGNAL ;
    PORT
      LAYER M4 ;
        RECT  0 7.056 0.084 7.08 ;
    END
  END q[156]
  PIN q[157]
    DIRECTION OUTPUT ;
    USE SIGNAL ;
    PORT
      LAYER M4 ;
        RECT  0 7.152 0.084 7.176 ;
    END
  END q[157]
  PIN q[158]
    DIRECTION OUTPUT ;
    USE SIGNAL ;
    PORT
      LAYER M4 ;
        RECT  0 7.248 0.084 7.272 ;
    END
  END q[158]
  PIN q[159]
    DIRECTION OUTPUT ;
    USE SIGNAL ;
    PORT
      LAYER M4 ;
        RECT  0 7.344 0.084 7.368 ;
    END
  END q[159]
  PIN q[15]
    DIRECTION OUTPUT ;
    USE SIGNAL ;
    PORT
      LAYER M4 ;
        RECT  0 85.68 0.084 85.704 ;
    END
  END q[15]
  PIN q[160]
    DIRECTION OUTPUT ;
    USE SIGNAL ;
    PORT
      LAYER M4 ;
        RECT  0 7.44 0.084 7.464 ;
    END
  END q[160]
  PIN q[161]
    DIRECTION OUTPUT ;
    USE SIGNAL ;
    PORT
      LAYER M4 ;
        RECT  0 7.536 0.084 7.56 ;
    END
  END q[161]
  PIN q[162]
    DIRECTION OUTPUT ;
    USE SIGNAL ;
    PORT
      LAYER M4 ;
        RECT  0 7.632 0.084 7.656 ;
    END
  END q[162]
  PIN q[163]
    DIRECTION OUTPUT ;
    USE SIGNAL ;
    PORT
      LAYER M4 ;
        RECT  0 7.728 0.084 7.752 ;
    END
  END q[163]
  PIN q[164]
    DIRECTION OUTPUT ;
    USE SIGNAL ;
    PORT
      LAYER M4 ;
        RECT  0 7.824 0.084 7.848 ;
    END
  END q[164]
  PIN q[165]
    DIRECTION OUTPUT ;
    USE SIGNAL ;
    PORT
      LAYER M4 ;
        RECT  0 7.92 0.084 7.944 ;
    END
  END q[165]
  PIN q[166]
    DIRECTION OUTPUT ;
    USE SIGNAL ;
    PORT
      LAYER M4 ;
        RECT  0 8.016 0.084 8.04 ;
    END
  END q[166]
  PIN q[167]
    DIRECTION OUTPUT ;
    USE SIGNAL ;
    PORT
      LAYER M4 ;
        RECT  0 8.112 0.084 8.136 ;
    END
  END q[167]
  PIN q[168]
    DIRECTION OUTPUT ;
    USE SIGNAL ;
    PORT
      LAYER M4 ;
        RECT  0 8.208 0.084 8.232 ;
    END
  END q[168]
  PIN q[169]
    DIRECTION OUTPUT ;
    USE SIGNAL ;
    PORT
      LAYER M4 ;
        RECT  0 8.304 0.084 8.328 ;
    END
  END q[169]
  PIN q[16]
    DIRECTION OUTPUT ;
    USE SIGNAL ;
    PORT
      LAYER M4 ;
        RECT  0 85.776 0.084 85.8 ;
    END
  END q[16]
  PIN q[170]
    DIRECTION OUTPUT ;
    USE SIGNAL ;
    PORT
      LAYER M4 ;
        RECT  0 8.4 0.084 8.424 ;
    END
  END q[170]
  PIN q[171]
    DIRECTION OUTPUT ;
    USE SIGNAL ;
    PORT
      LAYER M4 ;
        RECT  0 8.496 0.084 8.52 ;
    END
  END q[171]
  PIN q[172]
    DIRECTION OUTPUT ;
    USE SIGNAL ;
    PORT
      LAYER M4 ;
        RECT  0 8.592 0.084 8.616 ;
    END
  END q[172]
  PIN q[173]
    DIRECTION OUTPUT ;
    USE SIGNAL ;
    PORT
      LAYER M4 ;
        RECT  0 8.688 0.084 8.712 ;
    END
  END q[173]
  PIN q[174]
    DIRECTION OUTPUT ;
    USE SIGNAL ;
    PORT
      LAYER M4 ;
        RECT  0 8.784 0.084 8.808 ;
    END
  END q[174]
  PIN q[175]
    DIRECTION OUTPUT ;
    USE SIGNAL ;
    PORT
      LAYER M4 ;
        RECT  0 8.88 0.084 8.904 ;
    END
  END q[175]
  PIN q[176]
    DIRECTION OUTPUT ;
    USE SIGNAL ;
    PORT
      LAYER M4 ;
        RECT  0 8.976 0.084 9 ;
    END
  END q[176]
  PIN q[177]
    DIRECTION OUTPUT ;
    USE SIGNAL ;
    PORT
      LAYER M4 ;
        RECT  0 9.072 0.084 9.096 ;
    END
  END q[177]
  PIN q[178]
    DIRECTION OUTPUT ;
    USE SIGNAL ;
    PORT
      LAYER M4 ;
        RECT  0 9.168 0.084 9.192 ;
    END
  END q[178]
  PIN q[179]
    DIRECTION OUTPUT ;
    USE SIGNAL ;
    PORT
      LAYER M4 ;
        RECT  0 9.264 0.084 9.288 ;
    END
  END q[179]
  PIN q[17]
    DIRECTION OUTPUT ;
    USE SIGNAL ;
    PORT
      LAYER M4 ;
        RECT  0 85.872 0.084 85.896 ;
    END
  END q[17]
  PIN q[180]
    DIRECTION OUTPUT ;
    USE SIGNAL ;
    PORT
      LAYER M4 ;
        RECT  0 9.36 0.084 9.384 ;
    END
  END q[180]
  PIN q[181]
    DIRECTION OUTPUT ;
    USE SIGNAL ;
    PORT
      LAYER M4 ;
        RECT  0 9.456 0.084 9.48 ;
    END
  END q[181]
  PIN q[182]
    DIRECTION OUTPUT ;
    USE SIGNAL ;
    PORT
      LAYER M4 ;
        RECT  0 9.552 0.084 9.576 ;
    END
  END q[182]
  PIN q[183]
    DIRECTION OUTPUT ;
    USE SIGNAL ;
    PORT
      LAYER M4 ;
        RECT  0 9.648 0.084 9.672 ;
    END
  END q[183]
  PIN q[184]
    DIRECTION OUTPUT ;
    USE SIGNAL ;
    PORT
      LAYER M4 ;
        RECT  0 9.744 0.084 9.768 ;
    END
  END q[184]
  PIN q[185]
    DIRECTION OUTPUT ;
    USE SIGNAL ;
    PORT
      LAYER M4 ;
        RECT  0 9.84 0.084 9.864 ;
    END
  END q[185]
  PIN q[186]
    DIRECTION OUTPUT ;
    USE SIGNAL ;
    PORT
      LAYER M4 ;
        RECT  0 9.936 0.084 9.96 ;
    END
  END q[186]
  PIN q[187]
    DIRECTION OUTPUT ;
    USE SIGNAL ;
    PORT
      LAYER M4 ;
        RECT  0 10.032 0.084 10.056 ;
    END
  END q[187]
  PIN q[188]
    DIRECTION OUTPUT ;
    USE SIGNAL ;
    PORT
      LAYER M4 ;
        RECT  0 10.128 0.084 10.152 ;
    END
  END q[188]
  PIN q[189]
    DIRECTION OUTPUT ;
    USE SIGNAL ;
    PORT
      LAYER M4 ;
        RECT  0 10.224 0.084 10.248 ;
    END
  END q[189]
  PIN q[18]
    DIRECTION OUTPUT ;
    USE SIGNAL ;
    PORT
      LAYER M4 ;
        RECT  0 85.968 0.084 85.992 ;
    END
  END q[18]
  PIN q[190]
    DIRECTION OUTPUT ;
    USE SIGNAL ;
    PORT
      LAYER M4 ;
        RECT  0 10.32 0.084 10.344 ;
    END
  END q[190]
  PIN q[191]
    DIRECTION OUTPUT ;
    USE SIGNAL ;
    PORT
      LAYER M4 ;
        RECT  0 10.416 0.084 10.44 ;
    END
  END q[191]
  PIN q[192]
    DIRECTION OUTPUT ;
    USE SIGNAL ;
    PORT
      LAYER M4 ;
        RECT  0 20.496 0.084 20.52 ;
    END
  END q[192]
  PIN q[193]
    DIRECTION OUTPUT ;
    USE SIGNAL ;
    PORT
      LAYER M4 ;
        RECT  0 20.592 0.084 20.616 ;
    END
  END q[193]
  PIN q[194]
    DIRECTION OUTPUT ;
    USE SIGNAL ;
    PORT
      LAYER M4 ;
        RECT  0 20.688 0.084 20.712 ;
    END
  END q[194]
  PIN q[195]
    DIRECTION OUTPUT ;
    USE SIGNAL ;
    PORT
      LAYER M4 ;
        RECT  0 20.784 0.084 20.808 ;
    END
  END q[195]
  PIN q[196]
    DIRECTION OUTPUT ;
    USE SIGNAL ;
    PORT
      LAYER M4 ;
        RECT  0 20.88 0.084 20.904 ;
    END
  END q[196]
  PIN q[197]
    DIRECTION OUTPUT ;
    USE SIGNAL ;
    PORT
      LAYER M4 ;
        RECT  0 20.976 0.084 21 ;
    END
  END q[197]
  PIN q[198]
    DIRECTION OUTPUT ;
    USE SIGNAL ;
    PORT
      LAYER M4 ;
        RECT  0 21.072 0.084 21.096 ;
    END
  END q[198]
  PIN q[199]
    DIRECTION OUTPUT ;
    USE SIGNAL ;
    PORT
      LAYER M4 ;
        RECT  0 21.168 0.084 21.192 ;
    END
  END q[199]
  PIN q[19]
    DIRECTION OUTPUT ;
    USE SIGNAL ;
    PORT
      LAYER M4 ;
        RECT  0 86.064 0.084 86.088 ;
    END
  END q[19]
  PIN q[1]
    DIRECTION OUTPUT ;
    USE SIGNAL ;
    PORT
      LAYER M4 ;
        RECT  0 84.336 0.084 84.36 ;
    END
  END q[1]
  PIN q[200]
    DIRECTION OUTPUT ;
    USE SIGNAL ;
    PORT
      LAYER M4 ;
        RECT  0 21.264 0.084 21.288 ;
    END
  END q[200]
  PIN q[201]
    DIRECTION OUTPUT ;
    USE SIGNAL ;
    PORT
      LAYER M4 ;
        RECT  0 21.36 0.084 21.384 ;
    END
  END q[201]
  PIN q[202]
    DIRECTION OUTPUT ;
    USE SIGNAL ;
    PORT
      LAYER M4 ;
        RECT  0 21.456 0.084 21.48 ;
    END
  END q[202]
  PIN q[203]
    DIRECTION OUTPUT ;
    USE SIGNAL ;
    PORT
      LAYER M4 ;
        RECT  0 21.552 0.084 21.576 ;
    END
  END q[203]
  PIN q[204]
    DIRECTION OUTPUT ;
    USE SIGNAL ;
    PORT
      LAYER M4 ;
        RECT  0 21.648 0.084 21.672 ;
    END
  END q[204]
  PIN q[205]
    DIRECTION OUTPUT ;
    USE SIGNAL ;
    PORT
      LAYER M4 ;
        RECT  0 21.744 0.084 21.768 ;
    END
  END q[205]
  PIN q[206]
    DIRECTION OUTPUT ;
    USE SIGNAL ;
    PORT
      LAYER M4 ;
        RECT  0 21.84 0.084 21.864 ;
    END
  END q[206]
  PIN q[207]
    DIRECTION OUTPUT ;
    USE SIGNAL ;
    PORT
      LAYER M4 ;
        RECT  0 21.936 0.084 21.96 ;
    END
  END q[207]
  PIN q[208]
    DIRECTION OUTPUT ;
    USE SIGNAL ;
    PORT
      LAYER M4 ;
        RECT  0 22.032 0.084 22.056 ;
    END
  END q[208]
  PIN q[209]
    DIRECTION OUTPUT ;
    USE SIGNAL ;
    PORT
      LAYER M4 ;
        RECT  0 22.128 0.084 22.152 ;
    END
  END q[209]
  PIN q[20]
    DIRECTION OUTPUT ;
    USE SIGNAL ;
    PORT
      LAYER M4 ;
        RECT  0 86.16 0.084 86.184 ;
    END
  END q[20]
  PIN q[210]
    DIRECTION OUTPUT ;
    USE SIGNAL ;
    PORT
      LAYER M4 ;
        RECT  0 22.224 0.084 22.248 ;
    END
  END q[210]
  PIN q[211]
    DIRECTION OUTPUT ;
    USE SIGNAL ;
    PORT
      LAYER M4 ;
        RECT  0 22.32 0.084 22.344 ;
    END
  END q[211]
  PIN q[212]
    DIRECTION OUTPUT ;
    USE SIGNAL ;
    PORT
      LAYER M4 ;
        RECT  0 22.416 0.084 22.44 ;
    END
  END q[212]
  PIN q[213]
    DIRECTION OUTPUT ;
    USE SIGNAL ;
    PORT
      LAYER M4 ;
        RECT  0 22.512 0.084 22.536 ;
    END
  END q[213]
  PIN q[214]
    DIRECTION OUTPUT ;
    USE SIGNAL ;
    PORT
      LAYER M4 ;
        RECT  0 22.608 0.084 22.632 ;
    END
  END q[214]
  PIN q[215]
    DIRECTION OUTPUT ;
    USE SIGNAL ;
    PORT
      LAYER M4 ;
        RECT  0 22.704 0.084 22.728 ;
    END
  END q[215]
  PIN q[216]
    DIRECTION OUTPUT ;
    USE SIGNAL ;
    PORT
      LAYER M4 ;
        RECT  0 22.8 0.084 22.824 ;
    END
  END q[216]
  PIN q[217]
    DIRECTION OUTPUT ;
    USE SIGNAL ;
    PORT
      LAYER M4 ;
        RECT  0 22.896 0.084 22.92 ;
    END
  END q[217]
  PIN q[218]
    DIRECTION OUTPUT ;
    USE SIGNAL ;
    PORT
      LAYER M4 ;
        RECT  0 22.992 0.084 23.016 ;
    END
  END q[218]
  PIN q[219]
    DIRECTION OUTPUT ;
    USE SIGNAL ;
    PORT
      LAYER M4 ;
        RECT  0 23.088 0.084 23.112 ;
    END
  END q[219]
  PIN q[21]
    DIRECTION OUTPUT ;
    USE SIGNAL ;
    PORT
      LAYER M4 ;
        RECT  0 86.256 0.084 86.28 ;
    END
  END q[21]
  PIN q[220]
    DIRECTION OUTPUT ;
    USE SIGNAL ;
    PORT
      LAYER M4 ;
        RECT  0 23.184 0.084 23.208 ;
    END
  END q[220]
  PIN q[221]
    DIRECTION OUTPUT ;
    USE SIGNAL ;
    PORT
      LAYER M4 ;
        RECT  0 23.28 0.084 23.304 ;
    END
  END q[221]
  PIN q[222]
    DIRECTION OUTPUT ;
    USE SIGNAL ;
    PORT
      LAYER M4 ;
        RECT  0 23.376 0.084 23.4 ;
    END
  END q[222]
  PIN q[223]
    DIRECTION OUTPUT ;
    USE SIGNAL ;
    PORT
      LAYER M4 ;
        RECT  0 23.472 0.084 23.496 ;
    END
  END q[223]
  PIN q[224]
    DIRECTION OUTPUT ;
    USE SIGNAL ;
    PORT
      LAYER M4 ;
        RECT  0 13.584 0.084 13.608 ;
    END
  END q[224]
  PIN q[225]
    DIRECTION OUTPUT ;
    USE SIGNAL ;
    PORT
      LAYER M4 ;
        RECT  0 13.68 0.084 13.704 ;
    END
  END q[225]
  PIN q[226]
    DIRECTION OUTPUT ;
    USE SIGNAL ;
    PORT
      LAYER M4 ;
        RECT  0 13.776 0.084 13.8 ;
    END
  END q[226]
  PIN q[227]
    DIRECTION OUTPUT ;
    USE SIGNAL ;
    PORT
      LAYER M4 ;
        RECT  0 13.872 0.084 13.896 ;
    END
  END q[227]
  PIN q[228]
    DIRECTION OUTPUT ;
    USE SIGNAL ;
    PORT
      LAYER M4 ;
        RECT  0 13.968 0.084 13.992 ;
    END
  END q[228]
  PIN q[229]
    DIRECTION OUTPUT ;
    USE SIGNAL ;
    PORT
      LAYER M4 ;
        RECT  0 14.064 0.084 14.088 ;
    END
  END q[229]
  PIN q[22]
    DIRECTION OUTPUT ;
    USE SIGNAL ;
    PORT
      LAYER M4 ;
        RECT  0 86.352 0.084 86.376 ;
    END
  END q[22]
  PIN q[230]
    DIRECTION OUTPUT ;
    USE SIGNAL ;
    PORT
      LAYER M4 ;
        RECT  0 14.16 0.084 14.184 ;
    END
  END q[230]
  PIN q[231]
    DIRECTION OUTPUT ;
    USE SIGNAL ;
    PORT
      LAYER M4 ;
        RECT  0 14.256 0.084 14.28 ;
    END
  END q[231]
  PIN q[232]
    DIRECTION OUTPUT ;
    USE SIGNAL ;
    PORT
      LAYER M4 ;
        RECT  0 14.352 0.084 14.376 ;
    END
  END q[232]
  PIN q[233]
    DIRECTION OUTPUT ;
    USE SIGNAL ;
    PORT
      LAYER M4 ;
        RECT  0 14.448 0.084 14.472 ;
    END
  END q[233]
  PIN q[234]
    DIRECTION OUTPUT ;
    USE SIGNAL ;
    PORT
      LAYER M4 ;
        RECT  0 14.544 0.084 14.568 ;
    END
  END q[234]
  PIN q[235]
    DIRECTION OUTPUT ;
    USE SIGNAL ;
    PORT
      LAYER M4 ;
        RECT  0 14.64 0.084 14.664 ;
    END
  END q[235]
  PIN q[236]
    DIRECTION OUTPUT ;
    USE SIGNAL ;
    PORT
      LAYER M4 ;
        RECT  0 14.736 0.084 14.76 ;
    END
  END q[236]
  PIN q[237]
    DIRECTION OUTPUT ;
    USE SIGNAL ;
    PORT
      LAYER M4 ;
        RECT  0 14.832 0.084 14.856 ;
    END
  END q[237]
  PIN q[238]
    DIRECTION OUTPUT ;
    USE SIGNAL ;
    PORT
      LAYER M4 ;
        RECT  0 14.928 0.084 14.952 ;
    END
  END q[238]
  PIN q[239]
    DIRECTION OUTPUT ;
    USE SIGNAL ;
    PORT
      LAYER M4 ;
        RECT  0 15.024 0.084 15.048 ;
    END
  END q[239]
  PIN q[23]
    DIRECTION OUTPUT ;
    USE SIGNAL ;
    PORT
      LAYER M4 ;
        RECT  0 86.448 0.084 86.472 ;
    END
  END q[23]
  PIN q[240]
    DIRECTION OUTPUT ;
    USE SIGNAL ;
    PORT
      LAYER M4 ;
        RECT  0 15.12 0.084 15.144 ;
    END
  END q[240]
  PIN q[241]
    DIRECTION OUTPUT ;
    USE SIGNAL ;
    PORT
      LAYER M4 ;
        RECT  0 15.216 0.084 15.24 ;
    END
  END q[241]
  PIN q[242]
    DIRECTION OUTPUT ;
    USE SIGNAL ;
    PORT
      LAYER M4 ;
        RECT  0 15.312 0.084 15.336 ;
    END
  END q[242]
  PIN q[243]
    DIRECTION OUTPUT ;
    USE SIGNAL ;
    PORT
      LAYER M4 ;
        RECT  0 15.408 0.084 15.432 ;
    END
  END q[243]
  PIN q[244]
    DIRECTION OUTPUT ;
    USE SIGNAL ;
    PORT
      LAYER M4 ;
        RECT  0 15.504 0.084 15.528 ;
    END
  END q[244]
  PIN q[245]
    DIRECTION OUTPUT ;
    USE SIGNAL ;
    PORT
      LAYER M4 ;
        RECT  0 15.6 0.084 15.624 ;
    END
  END q[245]
  PIN q[246]
    DIRECTION OUTPUT ;
    USE SIGNAL ;
    PORT
      LAYER M4 ;
        RECT  0 15.696 0.084 15.72 ;
    END
  END q[246]
  PIN q[247]
    DIRECTION OUTPUT ;
    USE SIGNAL ;
    PORT
      LAYER M4 ;
        RECT  0 15.792 0.084 15.816 ;
    END
  END q[247]
  PIN q[248]
    DIRECTION OUTPUT ;
    USE SIGNAL ;
    PORT
      LAYER M4 ;
        RECT  0 15.888 0.084 15.912 ;
    END
  END q[248]
  PIN q[249]
    DIRECTION OUTPUT ;
    USE SIGNAL ;
    PORT
      LAYER M4 ;
        RECT  0 15.984 0.084 16.008 ;
    END
  END q[249]
  PIN q[24]
    DIRECTION OUTPUT ;
    USE SIGNAL ;
    PORT
      LAYER M4 ;
        RECT  0 86.544 0.084 86.568 ;
    END
  END q[24]
  PIN q[250]
    DIRECTION OUTPUT ;
    USE SIGNAL ;
    PORT
      LAYER M4 ;
        RECT  0 16.08 0.084 16.104 ;
    END
  END q[250]
  PIN q[251]
    DIRECTION OUTPUT ;
    USE SIGNAL ;
    PORT
      LAYER M4 ;
        RECT  0 16.176 0.084 16.2 ;
    END
  END q[251]
  PIN q[252]
    DIRECTION OUTPUT ;
    USE SIGNAL ;
    PORT
      LAYER M4 ;
        RECT  0 16.272 0.084 16.296 ;
    END
  END q[252]
  PIN q[253]
    DIRECTION OUTPUT ;
    USE SIGNAL ;
    PORT
      LAYER M4 ;
        RECT  0 16.368 0.084 16.392 ;
    END
  END q[253]
  PIN q[254]
    DIRECTION OUTPUT ;
    USE SIGNAL ;
    PORT
      LAYER M4 ;
        RECT  0 16.464 0.084 16.488 ;
    END
  END q[254]
  PIN q[255]
    DIRECTION OUTPUT ;
    USE SIGNAL ;
    PORT
      LAYER M4 ;
        RECT  0 16.56 0.084 16.584 ;
    END
  END q[255]
  PIN q[256]
    DIRECTION OUTPUT ;
    USE SIGNAL ;
    PORT
      LAYER M4 ;
        RECT  0 32.784 0.084 32.808 ;
    END
  END q[256]
  PIN q[257]
    DIRECTION OUTPUT ;
    USE SIGNAL ;
    PORT
      LAYER M4 ;
        RECT  0 32.88 0.084 32.904 ;
    END
  END q[257]
  PIN q[258]
    DIRECTION OUTPUT ;
    USE SIGNAL ;
    PORT
      LAYER M4 ;
        RECT  0 32.976 0.084 33 ;
    END
  END q[258]
  PIN q[259]
    DIRECTION OUTPUT ;
    USE SIGNAL ;
    PORT
      LAYER M4 ;
        RECT  0 33.072 0.084 33.096 ;
    END
  END q[259]
  PIN q[25]
    DIRECTION OUTPUT ;
    USE SIGNAL ;
    PORT
      LAYER M4 ;
        RECT  0 86.64 0.084 86.664 ;
    END
  END q[25]
  PIN q[260]
    DIRECTION OUTPUT ;
    USE SIGNAL ;
    PORT
      LAYER M4 ;
        RECT  0 33.168 0.084 33.192 ;
    END
  END q[260]
  PIN q[261]
    DIRECTION OUTPUT ;
    USE SIGNAL ;
    PORT
      LAYER M4 ;
        RECT  0 33.264 0.084 33.288 ;
    END
  END q[261]
  PIN q[262]
    DIRECTION OUTPUT ;
    USE SIGNAL ;
    PORT
      LAYER M4 ;
        RECT  0 33.36 0.084 33.384 ;
    END
  END q[262]
  PIN q[263]
    DIRECTION OUTPUT ;
    USE SIGNAL ;
    PORT
      LAYER M4 ;
        RECT  0 33.456 0.084 33.48 ;
    END
  END q[263]
  PIN q[264]
    DIRECTION OUTPUT ;
    USE SIGNAL ;
    PORT
      LAYER M4 ;
        RECT  0 33.552 0.084 33.576 ;
    END
  END q[264]
  PIN q[265]
    DIRECTION OUTPUT ;
    USE SIGNAL ;
    PORT
      LAYER M4 ;
        RECT  0 33.648 0.084 33.672 ;
    END
  END q[265]
  PIN q[266]
    DIRECTION OUTPUT ;
    USE SIGNAL ;
    PORT
      LAYER M4 ;
        RECT  0 33.744 0.084 33.768 ;
    END
  END q[266]
  PIN q[267]
    DIRECTION OUTPUT ;
    USE SIGNAL ;
    PORT
      LAYER M4 ;
        RECT  0 33.84 0.084 33.864 ;
    END
  END q[267]
  PIN q[268]
    DIRECTION OUTPUT ;
    USE SIGNAL ;
    PORT
      LAYER M4 ;
        RECT  0 33.936 0.084 33.96 ;
    END
  END q[268]
  PIN q[269]
    DIRECTION OUTPUT ;
    USE SIGNAL ;
    PORT
      LAYER M4 ;
        RECT  0 34.032 0.084 34.056 ;
    END
  END q[269]
  PIN q[26]
    DIRECTION OUTPUT ;
    USE SIGNAL ;
    PORT
      LAYER M4 ;
        RECT  0 86.736 0.084 86.76 ;
    END
  END q[26]
  PIN q[270]
    DIRECTION OUTPUT ;
    USE SIGNAL ;
    PORT
      LAYER M4 ;
        RECT  0 34.128 0.084 34.152 ;
    END
  END q[270]
  PIN q[271]
    DIRECTION OUTPUT ;
    USE SIGNAL ;
    PORT
      LAYER M4 ;
        RECT  0 34.224 0.084 34.248 ;
    END
  END q[271]
  PIN q[272]
    DIRECTION OUTPUT ;
    USE SIGNAL ;
    PORT
      LAYER M4 ;
        RECT  0 34.32 0.084 34.344 ;
    END
  END q[272]
  PIN q[273]
    DIRECTION OUTPUT ;
    USE SIGNAL ;
    PORT
      LAYER M4 ;
        RECT  0 34.416 0.084 34.44 ;
    END
  END q[273]
  PIN q[274]
    DIRECTION OUTPUT ;
    USE SIGNAL ;
    PORT
      LAYER M4 ;
        RECT  0 34.512 0.084 34.536 ;
    END
  END q[274]
  PIN q[275]
    DIRECTION OUTPUT ;
    USE SIGNAL ;
    PORT
      LAYER M4 ;
        RECT  0 34.608 0.084 34.632 ;
    END
  END q[275]
  PIN q[276]
    DIRECTION OUTPUT ;
    USE SIGNAL ;
    PORT
      LAYER M4 ;
        RECT  0 34.704 0.084 34.728 ;
    END
  END q[276]
  PIN q[277]
    DIRECTION OUTPUT ;
    USE SIGNAL ;
    PORT
      LAYER M4 ;
        RECT  0 34.8 0.084 34.824 ;
    END
  END q[277]
  PIN q[278]
    DIRECTION OUTPUT ;
    USE SIGNAL ;
    PORT
      LAYER M4 ;
        RECT  0 34.896 0.084 34.92 ;
    END
  END q[278]
  PIN q[279]
    DIRECTION OUTPUT ;
    USE SIGNAL ;
    PORT
      LAYER M4 ;
        RECT  0 34.992 0.084 35.016 ;
    END
  END q[279]
  PIN q[27]
    DIRECTION OUTPUT ;
    USE SIGNAL ;
    PORT
      LAYER M4 ;
        RECT  0 86.832 0.084 86.856 ;
    END
  END q[27]
  PIN q[280]
    DIRECTION OUTPUT ;
    USE SIGNAL ;
    PORT
      LAYER M4 ;
        RECT  0 35.088 0.084 35.112 ;
    END
  END q[280]
  PIN q[281]
    DIRECTION OUTPUT ;
    USE SIGNAL ;
    PORT
      LAYER M4 ;
        RECT  0 35.184 0.084 35.208 ;
    END
  END q[281]
  PIN q[282]
    DIRECTION OUTPUT ;
    USE SIGNAL ;
    PORT
      LAYER M4 ;
        RECT  0 35.28 0.084 35.304 ;
    END
  END q[282]
  PIN q[283]
    DIRECTION OUTPUT ;
    USE SIGNAL ;
    PORT
      LAYER M4 ;
        RECT  0 35.376 0.084 35.4 ;
    END
  END q[283]
  PIN q[284]
    DIRECTION OUTPUT ;
    USE SIGNAL ;
    PORT
      LAYER M4 ;
        RECT  0 35.472 0.084 35.496 ;
    END
  END q[284]
  PIN q[285]
    DIRECTION OUTPUT ;
    USE SIGNAL ;
    PORT
      LAYER M4 ;
        RECT  0 35.568 0.084 35.592 ;
    END
  END q[285]
  PIN q[286]
    DIRECTION OUTPUT ;
    USE SIGNAL ;
    PORT
      LAYER M4 ;
        RECT  0 35.664 0.084 35.688 ;
    END
  END q[286]
  PIN q[287]
    DIRECTION OUTPUT ;
    USE SIGNAL ;
    PORT
      LAYER M4 ;
        RECT  0 35.76 0.084 35.784 ;
    END
  END q[287]
  PIN q[288]
    DIRECTION OUTPUT ;
    USE SIGNAL ;
    PORT
      LAYER M4 ;
        RECT  0 29.712 0.084 29.736 ;
    END
  END q[288]
  PIN q[289]
    DIRECTION OUTPUT ;
    USE SIGNAL ;
    PORT
      LAYER M4 ;
        RECT  0 29.808 0.084 29.832 ;
    END
  END q[289]
  PIN q[28]
    DIRECTION OUTPUT ;
    USE SIGNAL ;
    PORT
      LAYER M4 ;
        RECT  0 86.928 0.084 86.952 ;
    END
  END q[28]
  PIN q[290]
    DIRECTION OUTPUT ;
    USE SIGNAL ;
    PORT
      LAYER M4 ;
        RECT  0 29.904 0.084 29.928 ;
    END
  END q[290]
  PIN q[291]
    DIRECTION OUTPUT ;
    USE SIGNAL ;
    PORT
      LAYER M4 ;
        RECT  0 30 0.084 30.024 ;
    END
  END q[291]
  PIN q[292]
    DIRECTION OUTPUT ;
    USE SIGNAL ;
    PORT
      LAYER M4 ;
        RECT  0 30.096 0.084 30.12 ;
    END
  END q[292]
  PIN q[293]
    DIRECTION OUTPUT ;
    USE SIGNAL ;
    PORT
      LAYER M4 ;
        RECT  0 30.192 0.084 30.216 ;
    END
  END q[293]
  PIN q[294]
    DIRECTION OUTPUT ;
    USE SIGNAL ;
    PORT
      LAYER M4 ;
        RECT  0 30.288 0.084 30.312 ;
    END
  END q[294]
  PIN q[295]
    DIRECTION OUTPUT ;
    USE SIGNAL ;
    PORT
      LAYER M4 ;
        RECT  0 30.384 0.084 30.408 ;
    END
  END q[295]
  PIN q[296]
    DIRECTION OUTPUT ;
    USE SIGNAL ;
    PORT
      LAYER M4 ;
        RECT  0 30.48 0.084 30.504 ;
    END
  END q[296]
  PIN q[297]
    DIRECTION OUTPUT ;
    USE SIGNAL ;
    PORT
      LAYER M4 ;
        RECT  0 30.576 0.084 30.6 ;
    END
  END q[297]
  PIN q[298]
    DIRECTION OUTPUT ;
    USE SIGNAL ;
    PORT
      LAYER M4 ;
        RECT  0 30.672 0.084 30.696 ;
    END
  END q[298]
  PIN q[299]
    DIRECTION OUTPUT ;
    USE SIGNAL ;
    PORT
      LAYER M4 ;
        RECT  0 30.768 0.084 30.792 ;
    END
  END q[299]
  PIN q[29]
    DIRECTION OUTPUT ;
    USE SIGNAL ;
    PORT
      LAYER M4 ;
        RECT  0 87.024 0.084 87.048 ;
    END
  END q[29]
  PIN q[2]
    DIRECTION OUTPUT ;
    USE SIGNAL ;
    PORT
      LAYER M4 ;
        RECT  0 84.432 0.084 84.456 ;
    END
  END q[2]
  PIN q[300]
    DIRECTION OUTPUT ;
    USE SIGNAL ;
    PORT
      LAYER M4 ;
        RECT  0 30.864 0.084 30.888 ;
    END
  END q[300]
  PIN q[301]
    DIRECTION OUTPUT ;
    USE SIGNAL ;
    PORT
      LAYER M4 ;
        RECT  0 30.96 0.084 30.984 ;
    END
  END q[301]
  PIN q[302]
    DIRECTION OUTPUT ;
    USE SIGNAL ;
    PORT
      LAYER M4 ;
        RECT  0 31.056 0.084 31.08 ;
    END
  END q[302]
  PIN q[303]
    DIRECTION OUTPUT ;
    USE SIGNAL ;
    PORT
      LAYER M4 ;
        RECT  0 31.152 0.084 31.176 ;
    END
  END q[303]
  PIN q[304]
    DIRECTION OUTPUT ;
    USE SIGNAL ;
    PORT
      LAYER M4 ;
        RECT  0 31.248 0.084 31.272 ;
    END
  END q[304]
  PIN q[305]
    DIRECTION OUTPUT ;
    USE SIGNAL ;
    PORT
      LAYER M4 ;
        RECT  0 31.344 0.084 31.368 ;
    END
  END q[305]
  PIN q[306]
    DIRECTION OUTPUT ;
    USE SIGNAL ;
    PORT
      LAYER M4 ;
        RECT  0 31.44 0.084 31.464 ;
    END
  END q[306]
  PIN q[307]
    DIRECTION OUTPUT ;
    USE SIGNAL ;
    PORT
      LAYER M4 ;
        RECT  0 31.536 0.084 31.56 ;
    END
  END q[307]
  PIN q[308]
    DIRECTION OUTPUT ;
    USE SIGNAL ;
    PORT
      LAYER M4 ;
        RECT  0 31.632 0.084 31.656 ;
    END
  END q[308]
  PIN q[309]
    DIRECTION OUTPUT ;
    USE SIGNAL ;
    PORT
      LAYER M4 ;
        RECT  0 31.728 0.084 31.752 ;
    END
  END q[309]
  PIN q[30]
    DIRECTION OUTPUT ;
    USE SIGNAL ;
    PORT
      LAYER M4 ;
        RECT  0 87.12 0.084 87.144 ;
    END
  END q[30]
  PIN q[310]
    DIRECTION OUTPUT ;
    USE SIGNAL ;
    PORT
      LAYER M4 ;
        RECT  0 31.824 0.084 31.848 ;
    END
  END q[310]
  PIN q[311]
    DIRECTION OUTPUT ;
    USE SIGNAL ;
    PORT
      LAYER M4 ;
        RECT  0 31.92 0.084 31.944 ;
    END
  END q[311]
  PIN q[312]
    DIRECTION OUTPUT ;
    USE SIGNAL ;
    PORT
      LAYER M4 ;
        RECT  0 32.016 0.084 32.04 ;
    END
  END q[312]
  PIN q[313]
    DIRECTION OUTPUT ;
    USE SIGNAL ;
    PORT
      LAYER M4 ;
        RECT  0 32.112 0.084 32.136 ;
    END
  END q[313]
  PIN q[314]
    DIRECTION OUTPUT ;
    USE SIGNAL ;
    PORT
      LAYER M4 ;
        RECT  0 32.208 0.084 32.232 ;
    END
  END q[314]
  PIN q[315]
    DIRECTION OUTPUT ;
    USE SIGNAL ;
    PORT
      LAYER M4 ;
        RECT  0 32.304 0.084 32.328 ;
    END
  END q[315]
  PIN q[316]
    DIRECTION OUTPUT ;
    USE SIGNAL ;
    PORT
      LAYER M4 ;
        RECT  0 32.4 0.084 32.424 ;
    END
  END q[316]
  PIN q[317]
    DIRECTION OUTPUT ;
    USE SIGNAL ;
    PORT
      LAYER M4 ;
        RECT  0 32.496 0.084 32.52 ;
    END
  END q[317]
  PIN q[318]
    DIRECTION OUTPUT ;
    USE SIGNAL ;
    PORT
      LAYER M4 ;
        RECT  0 32.592 0.084 32.616 ;
    END
  END q[318]
  PIN q[319]
    DIRECTION OUTPUT ;
    USE SIGNAL ;
    PORT
      LAYER M4 ;
        RECT  0 32.688 0.084 32.712 ;
    END
  END q[319]
  PIN q[31]
    DIRECTION OUTPUT ;
    USE SIGNAL ;
    PORT
      LAYER M4 ;
        RECT  0 87.216 0.084 87.24 ;
    END
  END q[31]
  PIN q[320]
    DIRECTION OUTPUT ;
    USE SIGNAL ;
    PORT
      LAYER M4 ;
        RECT  0 39.696 0.084 39.72 ;
    END
  END q[320]
  PIN q[321]
    DIRECTION OUTPUT ;
    USE SIGNAL ;
    PORT
      LAYER M4 ;
        RECT  0 39.792 0.084 39.816 ;
    END
  END q[321]
  PIN q[322]
    DIRECTION OUTPUT ;
    USE SIGNAL ;
    PORT
      LAYER M4 ;
        RECT  0 39.888 0.084 39.912 ;
    END
  END q[322]
  PIN q[323]
    DIRECTION OUTPUT ;
    USE SIGNAL ;
    PORT
      LAYER M4 ;
        RECT  0 39.984 0.084 40.008 ;
    END
  END q[323]
  PIN q[324]
    DIRECTION OUTPUT ;
    USE SIGNAL ;
    PORT
      LAYER M4 ;
        RECT  0 40.08 0.084 40.104 ;
    END
  END q[324]
  PIN q[325]
    DIRECTION OUTPUT ;
    USE SIGNAL ;
    PORT
      LAYER M4 ;
        RECT  0 40.176 0.084 40.2 ;
    END
  END q[325]
  PIN q[326]
    DIRECTION OUTPUT ;
    USE SIGNAL ;
    PORT
      LAYER M4 ;
        RECT  0 40.272 0.084 40.296 ;
    END
  END q[326]
  PIN q[327]
    DIRECTION OUTPUT ;
    USE SIGNAL ;
    PORT
      LAYER M4 ;
        RECT  0 40.368 0.084 40.392 ;
    END
  END q[327]
  PIN q[328]
    DIRECTION OUTPUT ;
    USE SIGNAL ;
    PORT
      LAYER M4 ;
        RECT  0 40.464 0.084 40.488 ;
    END
  END q[328]
  PIN q[329]
    DIRECTION OUTPUT ;
    USE SIGNAL ;
    PORT
      LAYER M4 ;
        RECT  0 40.56 0.084 40.584 ;
    END
  END q[329]
  PIN q[32]
    DIRECTION OUTPUT ;
    USE SIGNAL ;
    PORT
      LAYER M4 ;
        RECT  0 81.168 0.084 81.192 ;
    END
  END q[32]
  PIN q[330]
    DIRECTION OUTPUT ;
    USE SIGNAL ;
    PORT
      LAYER M4 ;
        RECT  0 40.656 0.084 40.68 ;
    END
  END q[330]
  PIN q[331]
    DIRECTION OUTPUT ;
    USE SIGNAL ;
    PORT
      LAYER M4 ;
        RECT  0 40.752 0.084 40.776 ;
    END
  END q[331]
  PIN q[332]
    DIRECTION OUTPUT ;
    USE SIGNAL ;
    PORT
      LAYER M4 ;
        RECT  0 40.848 0.084 40.872 ;
    END
  END q[332]
  PIN q[333]
    DIRECTION OUTPUT ;
    USE SIGNAL ;
    PORT
      LAYER M4 ;
        RECT  0 40.944 0.084 40.968 ;
    END
  END q[333]
  PIN q[334]
    DIRECTION OUTPUT ;
    USE SIGNAL ;
    PORT
      LAYER M4 ;
        RECT  0 41.04 0.084 41.064 ;
    END
  END q[334]
  PIN q[335]
    DIRECTION OUTPUT ;
    USE SIGNAL ;
    PORT
      LAYER M4 ;
        RECT  0 41.136 0.084 41.16 ;
    END
  END q[335]
  PIN q[336]
    DIRECTION OUTPUT ;
    USE SIGNAL ;
    PORT
      LAYER M4 ;
        RECT  0 41.232 0.084 41.256 ;
    END
  END q[336]
  PIN q[337]
    DIRECTION OUTPUT ;
    USE SIGNAL ;
    PORT
      LAYER M4 ;
        RECT  0 41.328 0.084 41.352 ;
    END
  END q[337]
  PIN q[338]
    DIRECTION OUTPUT ;
    USE SIGNAL ;
    PORT
      LAYER M4 ;
        RECT  0 41.424 0.084 41.448 ;
    END
  END q[338]
  PIN q[339]
    DIRECTION OUTPUT ;
    USE SIGNAL ;
    PORT
      LAYER M4 ;
        RECT  0 41.52 0.084 41.544 ;
    END
  END q[339]
  PIN q[33]
    DIRECTION OUTPUT ;
    USE SIGNAL ;
    PORT
      LAYER M4 ;
        RECT  0 81.264 0.084 81.288 ;
    END
  END q[33]
  PIN q[340]
    DIRECTION OUTPUT ;
    USE SIGNAL ;
    PORT
      LAYER M4 ;
        RECT  0 41.616 0.084 41.64 ;
    END
  END q[340]
  PIN q[341]
    DIRECTION OUTPUT ;
    USE SIGNAL ;
    PORT
      LAYER M4 ;
        RECT  0 41.712 0.084 41.736 ;
    END
  END q[341]
  PIN q[342]
    DIRECTION OUTPUT ;
    USE SIGNAL ;
    PORT
      LAYER M4 ;
        RECT  0 41.808 0.084 41.832 ;
    END
  END q[342]
  PIN q[343]
    DIRECTION OUTPUT ;
    USE SIGNAL ;
    PORT
      LAYER M4 ;
        RECT  0 41.904 0.084 41.928 ;
    END
  END q[343]
  PIN q[344]
    DIRECTION OUTPUT ;
    USE SIGNAL ;
    PORT
      LAYER M4 ;
        RECT  0 42 0.084 42.024 ;
    END
  END q[344]
  PIN q[345]
    DIRECTION OUTPUT ;
    USE SIGNAL ;
    PORT
      LAYER M4 ;
        RECT  0 42.096 0.084 42.12 ;
    END
  END q[345]
  PIN q[346]
    DIRECTION OUTPUT ;
    USE SIGNAL ;
    PORT
      LAYER M4 ;
        RECT  0 42.192 0.084 42.216 ;
    END
  END q[346]
  PIN q[347]
    DIRECTION OUTPUT ;
    USE SIGNAL ;
    PORT
      LAYER M4 ;
        RECT  0 42.288 0.084 42.312 ;
    END
  END q[347]
  PIN q[348]
    DIRECTION OUTPUT ;
    USE SIGNAL ;
    PORT
      LAYER M4 ;
        RECT  0 42.384 0.084 42.408 ;
    END
  END q[348]
  PIN q[349]
    DIRECTION OUTPUT ;
    USE SIGNAL ;
    PORT
      LAYER M4 ;
        RECT  0 42.48 0.084 42.504 ;
    END
  END q[349]
  PIN q[34]
    DIRECTION OUTPUT ;
    USE SIGNAL ;
    PORT
      LAYER M4 ;
        RECT  0 81.36 0.084 81.384 ;
    END
  END q[34]
  PIN q[350]
    DIRECTION OUTPUT ;
    USE SIGNAL ;
    PORT
      LAYER M4 ;
        RECT  0 42.576 0.084 42.6 ;
    END
  END q[350]
  PIN q[351]
    DIRECTION OUTPUT ;
    USE SIGNAL ;
    PORT
      LAYER M4 ;
        RECT  0 42.672 0.084 42.696 ;
    END
  END q[351]
  PIN q[352]
    DIRECTION OUTPUT ;
    USE SIGNAL ;
    PORT
      LAYER M4 ;
        RECT  0 45.84 0.084 45.864 ;
    END
  END q[352]
  PIN q[353]
    DIRECTION OUTPUT ;
    USE SIGNAL ;
    PORT
      LAYER M4 ;
        RECT  0 45.936 0.084 45.96 ;
    END
  END q[353]
  PIN q[354]
    DIRECTION OUTPUT ;
    USE SIGNAL ;
    PORT
      LAYER M4 ;
        RECT  0 46.032 0.084 46.056 ;
    END
  END q[354]
  PIN q[355]
    DIRECTION OUTPUT ;
    USE SIGNAL ;
    PORT
      LAYER M4 ;
        RECT  0 46.128 0.084 46.152 ;
    END
  END q[355]
  PIN q[356]
    DIRECTION OUTPUT ;
    USE SIGNAL ;
    PORT
      LAYER M4 ;
        RECT  0 46.224 0.084 46.248 ;
    END
  END q[356]
  PIN q[357]
    DIRECTION OUTPUT ;
    USE SIGNAL ;
    PORT
      LAYER M4 ;
        RECT  0 46.32 0.084 46.344 ;
    END
  END q[357]
  PIN q[358]
    DIRECTION OUTPUT ;
    USE SIGNAL ;
    PORT
      LAYER M4 ;
        RECT  0 46.416 0.084 46.44 ;
    END
  END q[358]
  PIN q[359]
    DIRECTION OUTPUT ;
    USE SIGNAL ;
    PORT
      LAYER M4 ;
        RECT  0 46.512 0.084 46.536 ;
    END
  END q[359]
  PIN q[35]
    DIRECTION OUTPUT ;
    USE SIGNAL ;
    PORT
      LAYER M4 ;
        RECT  0 81.456 0.084 81.48 ;
    END
  END q[35]
  PIN q[360]
    DIRECTION OUTPUT ;
    USE SIGNAL ;
    PORT
      LAYER M4 ;
        RECT  0 46.608 0.084 46.632 ;
    END
  END q[360]
  PIN q[361]
    DIRECTION OUTPUT ;
    USE SIGNAL ;
    PORT
      LAYER M4 ;
        RECT  0 46.704 0.084 46.728 ;
    END
  END q[361]
  PIN q[362]
    DIRECTION OUTPUT ;
    USE SIGNAL ;
    PORT
      LAYER M4 ;
        RECT  0 46.8 0.084 46.824 ;
    END
  END q[362]
  PIN q[363]
    DIRECTION OUTPUT ;
    USE SIGNAL ;
    PORT
      LAYER M4 ;
        RECT  0 46.896 0.084 46.92 ;
    END
  END q[363]
  PIN q[364]
    DIRECTION OUTPUT ;
    USE SIGNAL ;
    PORT
      LAYER M4 ;
        RECT  0 46.992 0.084 47.016 ;
    END
  END q[364]
  PIN q[365]
    DIRECTION OUTPUT ;
    USE SIGNAL ;
    PORT
      LAYER M4 ;
        RECT  0 47.088 0.084 47.112 ;
    END
  END q[365]
  PIN q[366]
    DIRECTION OUTPUT ;
    USE SIGNAL ;
    PORT
      LAYER M4 ;
        RECT  0 47.184 0.084 47.208 ;
    END
  END q[366]
  PIN q[367]
    DIRECTION OUTPUT ;
    USE SIGNAL ;
    PORT
      LAYER M4 ;
        RECT  0 47.28 0.084 47.304 ;
    END
  END q[367]
  PIN q[368]
    DIRECTION OUTPUT ;
    USE SIGNAL ;
    PORT
      LAYER M4 ;
        RECT  0 47.376 0.084 47.4 ;
    END
  END q[368]
  PIN q[369]
    DIRECTION OUTPUT ;
    USE SIGNAL ;
    PORT
      LAYER M4 ;
        RECT  0 47.472 0.084 47.496 ;
    END
  END q[369]
  PIN q[36]
    DIRECTION OUTPUT ;
    USE SIGNAL ;
    PORT
      LAYER M4 ;
        RECT  0 81.552 0.084 81.576 ;
    END
  END q[36]
  PIN q[370]
    DIRECTION OUTPUT ;
    USE SIGNAL ;
    PORT
      LAYER M4 ;
        RECT  0 47.568 0.084 47.592 ;
    END
  END q[370]
  PIN q[371]
    DIRECTION OUTPUT ;
    USE SIGNAL ;
    PORT
      LAYER M4 ;
        RECT  0 47.664 0.084 47.688 ;
    END
  END q[371]
  PIN q[372]
    DIRECTION OUTPUT ;
    USE SIGNAL ;
    PORT
      LAYER M4 ;
        RECT  0 47.76 0.084 47.784 ;
    END
  END q[372]
  PIN q[373]
    DIRECTION OUTPUT ;
    USE SIGNAL ;
    PORT
      LAYER M4 ;
        RECT  0 47.856 0.084 47.88 ;
    END
  END q[373]
  PIN q[374]
    DIRECTION OUTPUT ;
    USE SIGNAL ;
    PORT
      LAYER M4 ;
        RECT  0 47.952 0.084 47.976 ;
    END
  END q[374]
  PIN q[375]
    DIRECTION OUTPUT ;
    USE SIGNAL ;
    PORT
      LAYER M4 ;
        RECT  0 48.048 0.084 48.072 ;
    END
  END q[375]
  PIN q[376]
    DIRECTION OUTPUT ;
    USE SIGNAL ;
    PORT
      LAYER M4 ;
        RECT  0 48.144 0.084 48.168 ;
    END
  END q[376]
  PIN q[377]
    DIRECTION OUTPUT ;
    USE SIGNAL ;
    PORT
      LAYER M4 ;
        RECT  0 48.24 0.084 48.264 ;
    END
  END q[377]
  PIN q[378]
    DIRECTION OUTPUT ;
    USE SIGNAL ;
    PORT
      LAYER M4 ;
        RECT  0 48.336 0.084 48.36 ;
    END
  END q[378]
  PIN q[379]
    DIRECTION OUTPUT ;
    USE SIGNAL ;
    PORT
      LAYER M4 ;
        RECT  0 48.432 0.084 48.456 ;
    END
  END q[379]
  PIN q[37]
    DIRECTION OUTPUT ;
    USE SIGNAL ;
    PORT
      LAYER M4 ;
        RECT  0 81.648 0.084 81.672 ;
    END
  END q[37]
  PIN q[380]
    DIRECTION OUTPUT ;
    USE SIGNAL ;
    PORT
      LAYER M4 ;
        RECT  0 48.528 0.084 48.552 ;
    END
  END q[380]
  PIN q[381]
    DIRECTION OUTPUT ;
    USE SIGNAL ;
    PORT
      LAYER M4 ;
        RECT  0 48.624 0.084 48.648 ;
    END
  END q[381]
  PIN q[382]
    DIRECTION OUTPUT ;
    USE SIGNAL ;
    PORT
      LAYER M4 ;
        RECT  0 48.72 0.084 48.744 ;
    END
  END q[382]
  PIN q[383]
    DIRECTION OUTPUT ;
    USE SIGNAL ;
    PORT
      LAYER M4 ;
        RECT  0 48.816 0.084 48.84 ;
    END
  END q[383]
  PIN q[384]
    DIRECTION OUTPUT ;
    USE SIGNAL ;
    PORT
      LAYER M4 ;
        RECT  0 55.056 0.084 55.08 ;
    END
  END q[384]
  PIN q[385]
    DIRECTION OUTPUT ;
    USE SIGNAL ;
    PORT
      LAYER M4 ;
        RECT  0 55.152 0.084 55.176 ;
    END
  END q[385]
  PIN q[386]
    DIRECTION OUTPUT ;
    USE SIGNAL ;
    PORT
      LAYER M4 ;
        RECT  0 55.248 0.084 55.272 ;
    END
  END q[386]
  PIN q[387]
    DIRECTION OUTPUT ;
    USE SIGNAL ;
    PORT
      LAYER M4 ;
        RECT  0 55.344 0.084 55.368 ;
    END
  END q[387]
  PIN q[388]
    DIRECTION OUTPUT ;
    USE SIGNAL ;
    PORT
      LAYER M4 ;
        RECT  0 55.44 0.084 55.464 ;
    END
  END q[388]
  PIN q[389]
    DIRECTION OUTPUT ;
    USE SIGNAL ;
    PORT
      LAYER M4 ;
        RECT  0 55.536 0.084 55.56 ;
    END
  END q[389]
  PIN q[38]
    DIRECTION OUTPUT ;
    USE SIGNAL ;
    PORT
      LAYER M4 ;
        RECT  0 81.744 0.084 81.768 ;
    END
  END q[38]
  PIN q[390]
    DIRECTION OUTPUT ;
    USE SIGNAL ;
    PORT
      LAYER M4 ;
        RECT  0 55.632 0.084 55.656 ;
    END
  END q[390]
  PIN q[391]
    DIRECTION OUTPUT ;
    USE SIGNAL ;
    PORT
      LAYER M4 ;
        RECT  0 55.728 0.084 55.752 ;
    END
  END q[391]
  PIN q[392]
    DIRECTION OUTPUT ;
    USE SIGNAL ;
    PORT
      LAYER M4 ;
        RECT  0 55.824 0.084 55.848 ;
    END
  END q[392]
  PIN q[393]
    DIRECTION OUTPUT ;
    USE SIGNAL ;
    PORT
      LAYER M4 ;
        RECT  0 55.92 0.084 55.944 ;
    END
  END q[393]
  PIN q[394]
    DIRECTION OUTPUT ;
    USE SIGNAL ;
    PORT
      LAYER M4 ;
        RECT  0 56.016 0.084 56.04 ;
    END
  END q[394]
  PIN q[395]
    DIRECTION OUTPUT ;
    USE SIGNAL ;
    PORT
      LAYER M4 ;
        RECT  0 56.112 0.084 56.136 ;
    END
  END q[395]
  PIN q[396]
    DIRECTION OUTPUT ;
    USE SIGNAL ;
    PORT
      LAYER M4 ;
        RECT  0 56.208 0.084 56.232 ;
    END
  END q[396]
  PIN q[397]
    DIRECTION OUTPUT ;
    USE SIGNAL ;
    PORT
      LAYER M4 ;
        RECT  0 56.304 0.084 56.328 ;
    END
  END q[397]
  PIN q[398]
    DIRECTION OUTPUT ;
    USE SIGNAL ;
    PORT
      LAYER M4 ;
        RECT  0 56.4 0.084 56.424 ;
    END
  END q[398]
  PIN q[399]
    DIRECTION OUTPUT ;
    USE SIGNAL ;
    PORT
      LAYER M4 ;
        RECT  0 56.496 0.084 56.52 ;
    END
  END q[399]
  PIN q[39]
    DIRECTION OUTPUT ;
    USE SIGNAL ;
    PORT
      LAYER M4 ;
        RECT  0 81.84 0.084 81.864 ;
    END
  END q[39]
  PIN q[3]
    DIRECTION OUTPUT ;
    USE SIGNAL ;
    PORT
      LAYER M4 ;
        RECT  0 84.528 0.084 84.552 ;
    END
  END q[3]
  PIN q[400]
    DIRECTION OUTPUT ;
    USE SIGNAL ;
    PORT
      LAYER M4 ;
        RECT  0 56.592 0.084 56.616 ;
    END
  END q[400]
  PIN q[401]
    DIRECTION OUTPUT ;
    USE SIGNAL ;
    PORT
      LAYER M4 ;
        RECT  0 56.688 0.084 56.712 ;
    END
  END q[401]
  PIN q[402]
    DIRECTION OUTPUT ;
    USE SIGNAL ;
    PORT
      LAYER M4 ;
        RECT  0 56.784 0.084 56.808 ;
    END
  END q[402]
  PIN q[403]
    DIRECTION OUTPUT ;
    USE SIGNAL ;
    PORT
      LAYER M4 ;
        RECT  0 56.88 0.084 56.904 ;
    END
  END q[403]
  PIN q[404]
    DIRECTION OUTPUT ;
    USE SIGNAL ;
    PORT
      LAYER M4 ;
        RECT  0 56.976 0.084 57 ;
    END
  END q[404]
  PIN q[405]
    DIRECTION OUTPUT ;
    USE SIGNAL ;
    PORT
      LAYER M4 ;
        RECT  0 57.072 0.084 57.096 ;
    END
  END q[405]
  PIN q[406]
    DIRECTION OUTPUT ;
    USE SIGNAL ;
    PORT
      LAYER M4 ;
        RECT  0 57.168 0.084 57.192 ;
    END
  END q[406]
  PIN q[407]
    DIRECTION OUTPUT ;
    USE SIGNAL ;
    PORT
      LAYER M4 ;
        RECT  0 57.264 0.084 57.288 ;
    END
  END q[407]
  PIN q[408]
    DIRECTION OUTPUT ;
    USE SIGNAL ;
    PORT
      LAYER M4 ;
        RECT  0 57.36 0.084 57.384 ;
    END
  END q[408]
  PIN q[409]
    DIRECTION OUTPUT ;
    USE SIGNAL ;
    PORT
      LAYER M4 ;
        RECT  0 57.456 0.084 57.48 ;
    END
  END q[409]
  PIN q[40]
    DIRECTION OUTPUT ;
    USE SIGNAL ;
    PORT
      LAYER M4 ;
        RECT  0 81.936 0.084 81.96 ;
    END
  END q[40]
  PIN q[410]
    DIRECTION OUTPUT ;
    USE SIGNAL ;
    PORT
      LAYER M4 ;
        RECT  0 57.552 0.084 57.576 ;
    END
  END q[410]
  PIN q[411]
    DIRECTION OUTPUT ;
    USE SIGNAL ;
    PORT
      LAYER M4 ;
        RECT  0 57.648 0.084 57.672 ;
    END
  END q[411]
  PIN q[412]
    DIRECTION OUTPUT ;
    USE SIGNAL ;
    PORT
      LAYER M4 ;
        RECT  0 57.744 0.084 57.768 ;
    END
  END q[412]
  PIN q[413]
    DIRECTION OUTPUT ;
    USE SIGNAL ;
    PORT
      LAYER M4 ;
        RECT  0 57.84 0.084 57.864 ;
    END
  END q[413]
  PIN q[414]
    DIRECTION OUTPUT ;
    USE SIGNAL ;
    PORT
      LAYER M4 ;
        RECT  0 57.936 0.084 57.96 ;
    END
  END q[414]
  PIN q[415]
    DIRECTION OUTPUT ;
    USE SIGNAL ;
    PORT
      LAYER M4 ;
        RECT  0 58.032 0.084 58.056 ;
    END
  END q[415]
  PIN q[416]
    DIRECTION OUTPUT ;
    USE SIGNAL ;
    PORT
      LAYER M4 ;
        RECT  0 58.896 0.084 58.92 ;
    END
  END q[416]
  PIN q[417]
    DIRECTION OUTPUT ;
    USE SIGNAL ;
    PORT
      LAYER M4 ;
        RECT  0 58.992 0.084 59.016 ;
    END
  END q[417]
  PIN q[418]
    DIRECTION OUTPUT ;
    USE SIGNAL ;
    PORT
      LAYER M4 ;
        RECT  0 59.088 0.084 59.112 ;
    END
  END q[418]
  PIN q[419]
    DIRECTION OUTPUT ;
    USE SIGNAL ;
    PORT
      LAYER M4 ;
        RECT  0 59.184 0.084 59.208 ;
    END
  END q[419]
  PIN q[41]
    DIRECTION OUTPUT ;
    USE SIGNAL ;
    PORT
      LAYER M4 ;
        RECT  0 82.032 0.084 82.056 ;
    END
  END q[41]
  PIN q[420]
    DIRECTION OUTPUT ;
    USE SIGNAL ;
    PORT
      LAYER M4 ;
        RECT  0 59.28 0.084 59.304 ;
    END
  END q[420]
  PIN q[421]
    DIRECTION OUTPUT ;
    USE SIGNAL ;
    PORT
      LAYER M4 ;
        RECT  0 59.376 0.084 59.4 ;
    END
  END q[421]
  PIN q[422]
    DIRECTION OUTPUT ;
    USE SIGNAL ;
    PORT
      LAYER M4 ;
        RECT  0 59.472 0.084 59.496 ;
    END
  END q[422]
  PIN q[423]
    DIRECTION OUTPUT ;
    USE SIGNAL ;
    PORT
      LAYER M4 ;
        RECT  0 59.568 0.084 59.592 ;
    END
  END q[423]
  PIN q[424]
    DIRECTION OUTPUT ;
    USE SIGNAL ;
    PORT
      LAYER M4 ;
        RECT  0 59.664 0.084 59.688 ;
    END
  END q[424]
  PIN q[425]
    DIRECTION OUTPUT ;
    USE SIGNAL ;
    PORT
      LAYER M4 ;
        RECT  0 59.76 0.084 59.784 ;
    END
  END q[425]
  PIN q[426]
    DIRECTION OUTPUT ;
    USE SIGNAL ;
    PORT
      LAYER M4 ;
        RECT  0 59.856 0.084 59.88 ;
    END
  END q[426]
  PIN q[427]
    DIRECTION OUTPUT ;
    USE SIGNAL ;
    PORT
      LAYER M4 ;
        RECT  0 59.952 0.084 59.976 ;
    END
  END q[427]
  PIN q[428]
    DIRECTION OUTPUT ;
    USE SIGNAL ;
    PORT
      LAYER M4 ;
        RECT  0 60.048 0.084 60.072 ;
    END
  END q[428]
  PIN q[429]
    DIRECTION OUTPUT ;
    USE SIGNAL ;
    PORT
      LAYER M4 ;
        RECT  0 60.144 0.084 60.168 ;
    END
  END q[429]
  PIN q[42]
    DIRECTION OUTPUT ;
    USE SIGNAL ;
    PORT
      LAYER M4 ;
        RECT  0 82.128 0.084 82.152 ;
    END
  END q[42]
  PIN q[430]
    DIRECTION OUTPUT ;
    USE SIGNAL ;
    PORT
      LAYER M4 ;
        RECT  0 60.24 0.084 60.264 ;
    END
  END q[430]
  PIN q[431]
    DIRECTION OUTPUT ;
    USE SIGNAL ;
    PORT
      LAYER M4 ;
        RECT  0 60.336 0.084 60.36 ;
    END
  END q[431]
  PIN q[432]
    DIRECTION OUTPUT ;
    USE SIGNAL ;
    PORT
      LAYER M4 ;
        RECT  0 60.432 0.084 60.456 ;
    END
  END q[432]
  PIN q[433]
    DIRECTION OUTPUT ;
    USE SIGNAL ;
    PORT
      LAYER M4 ;
        RECT  0 60.528 0.084 60.552 ;
    END
  END q[433]
  PIN q[434]
    DIRECTION OUTPUT ;
    USE SIGNAL ;
    PORT
      LAYER M4 ;
        RECT  0 60.624 0.084 60.648 ;
    END
  END q[434]
  PIN q[435]
    DIRECTION OUTPUT ;
    USE SIGNAL ;
    PORT
      LAYER M4 ;
        RECT  0 60.72 0.084 60.744 ;
    END
  END q[435]
  PIN q[436]
    DIRECTION OUTPUT ;
    USE SIGNAL ;
    PORT
      LAYER M4 ;
        RECT  0 60.816 0.084 60.84 ;
    END
  END q[436]
  PIN q[437]
    DIRECTION OUTPUT ;
    USE SIGNAL ;
    PORT
      LAYER M4 ;
        RECT  0 60.912 0.084 60.936 ;
    END
  END q[437]
  PIN q[438]
    DIRECTION OUTPUT ;
    USE SIGNAL ;
    PORT
      LAYER M4 ;
        RECT  0 61.008 0.084 61.032 ;
    END
  END q[438]
  PIN q[439]
    DIRECTION OUTPUT ;
    USE SIGNAL ;
    PORT
      LAYER M4 ;
        RECT  0 61.104 0.084 61.128 ;
    END
  END q[439]
  PIN q[43]
    DIRECTION OUTPUT ;
    USE SIGNAL ;
    PORT
      LAYER M4 ;
        RECT  0 82.224 0.084 82.248 ;
    END
  END q[43]
  PIN q[440]
    DIRECTION OUTPUT ;
    USE SIGNAL ;
    PORT
      LAYER M4 ;
        RECT  0 61.2 0.084 61.224 ;
    END
  END q[440]
  PIN q[441]
    DIRECTION OUTPUT ;
    USE SIGNAL ;
    PORT
      LAYER M4 ;
        RECT  0 61.296 0.084 61.32 ;
    END
  END q[441]
  PIN q[442]
    DIRECTION OUTPUT ;
    USE SIGNAL ;
    PORT
      LAYER M4 ;
        RECT  0 61.392 0.084 61.416 ;
    END
  END q[442]
  PIN q[443]
    DIRECTION OUTPUT ;
    USE SIGNAL ;
    PORT
      LAYER M4 ;
        RECT  0 61.488 0.084 61.512 ;
    END
  END q[443]
  PIN q[444]
    DIRECTION OUTPUT ;
    USE SIGNAL ;
    PORT
      LAYER M4 ;
        RECT  0 61.584 0.084 61.608 ;
    END
  END q[444]
  PIN q[445]
    DIRECTION OUTPUT ;
    USE SIGNAL ;
    PORT
      LAYER M4 ;
        RECT  0 61.68 0.084 61.704 ;
    END
  END q[445]
  PIN q[446]
    DIRECTION OUTPUT ;
    USE SIGNAL ;
    PORT
      LAYER M4 ;
        RECT  0 61.776 0.084 61.8 ;
    END
  END q[446]
  PIN q[447]
    DIRECTION OUTPUT ;
    USE SIGNAL ;
    PORT
      LAYER M4 ;
        RECT  0 61.872 0.084 61.896 ;
    END
  END q[447]
  PIN q[448]
    DIRECTION OUTPUT ;
    USE SIGNAL ;
    PORT
      LAYER M4 ;
        RECT  0 61.968 0.084 61.992 ;
    END
  END q[448]
  PIN q[449]
    DIRECTION OUTPUT ;
    USE SIGNAL ;
    PORT
      LAYER M4 ;
        RECT  0 62.064 0.084 62.088 ;
    END
  END q[449]
  PIN q[44]
    DIRECTION OUTPUT ;
    USE SIGNAL ;
    PORT
      LAYER M4 ;
        RECT  0 82.32 0.084 82.344 ;
    END
  END q[44]
  PIN q[450]
    DIRECTION OUTPUT ;
    USE SIGNAL ;
    PORT
      LAYER M4 ;
        RECT  0 62.16 0.084 62.184 ;
    END
  END q[450]
  PIN q[451]
    DIRECTION OUTPUT ;
    USE SIGNAL ;
    PORT
      LAYER M4 ;
        RECT  0 62.256 0.084 62.28 ;
    END
  END q[451]
  PIN q[452]
    DIRECTION OUTPUT ;
    USE SIGNAL ;
    PORT
      LAYER M4 ;
        RECT  0 62.352 0.084 62.376 ;
    END
  END q[452]
  PIN q[453]
    DIRECTION OUTPUT ;
    USE SIGNAL ;
    PORT
      LAYER M4 ;
        RECT  0 62.448 0.084 62.472 ;
    END
  END q[453]
  PIN q[454]
    DIRECTION OUTPUT ;
    USE SIGNAL ;
    PORT
      LAYER M4 ;
        RECT  0 62.544 0.084 62.568 ;
    END
  END q[454]
  PIN q[455]
    DIRECTION OUTPUT ;
    USE SIGNAL ;
    PORT
      LAYER M4 ;
        RECT  0 62.64 0.084 62.664 ;
    END
  END q[455]
  PIN q[456]
    DIRECTION OUTPUT ;
    USE SIGNAL ;
    PORT
      LAYER M4 ;
        RECT  0 62.736 0.084 62.76 ;
    END
  END q[456]
  PIN q[457]
    DIRECTION OUTPUT ;
    USE SIGNAL ;
    PORT
      LAYER M4 ;
        RECT  0 62.832 0.084 62.856 ;
    END
  END q[457]
  PIN q[458]
    DIRECTION OUTPUT ;
    USE SIGNAL ;
    PORT
      LAYER M4 ;
        RECT  0 62.928 0.084 62.952 ;
    END
  END q[458]
  PIN q[459]
    DIRECTION OUTPUT ;
    USE SIGNAL ;
    PORT
      LAYER M4 ;
        RECT  0 63.024 0.084 63.048 ;
    END
  END q[459]
  PIN q[45]
    DIRECTION OUTPUT ;
    USE SIGNAL ;
    PORT
      LAYER M4 ;
        RECT  0 82.416 0.084 82.44 ;
    END
  END q[45]
  PIN q[460]
    DIRECTION OUTPUT ;
    USE SIGNAL ;
    PORT
      LAYER M4 ;
        RECT  0 63.12 0.084 63.144 ;
    END
  END q[460]
  PIN q[461]
    DIRECTION OUTPUT ;
    USE SIGNAL ;
    PORT
      LAYER M4 ;
        RECT  0 63.216 0.084 63.24 ;
    END
  END q[461]
  PIN q[462]
    DIRECTION OUTPUT ;
    USE SIGNAL ;
    PORT
      LAYER M4 ;
        RECT  0 63.312 0.084 63.336 ;
    END
  END q[462]
  PIN q[463]
    DIRECTION OUTPUT ;
    USE SIGNAL ;
    PORT
      LAYER M4 ;
        RECT  0 63.408 0.084 63.432 ;
    END
  END q[463]
  PIN q[464]
    DIRECTION OUTPUT ;
    USE SIGNAL ;
    PORT
      LAYER M4 ;
        RECT  0 63.504 0.084 63.528 ;
    END
  END q[464]
  PIN q[465]
    DIRECTION OUTPUT ;
    USE SIGNAL ;
    PORT
      LAYER M4 ;
        RECT  0 63.6 0.084 63.624 ;
    END
  END q[465]
  PIN q[466]
    DIRECTION OUTPUT ;
    USE SIGNAL ;
    PORT
      LAYER M4 ;
        RECT  0 63.696 0.084 63.72 ;
    END
  END q[466]
  PIN q[467]
    DIRECTION OUTPUT ;
    USE SIGNAL ;
    PORT
      LAYER M4 ;
        RECT  0 63.792 0.084 63.816 ;
    END
  END q[467]
  PIN q[468]
    DIRECTION OUTPUT ;
    USE SIGNAL ;
    PORT
      LAYER M4 ;
        RECT  0 63.888 0.084 63.912 ;
    END
  END q[468]
  PIN q[469]
    DIRECTION OUTPUT ;
    USE SIGNAL ;
    PORT
      LAYER M4 ;
        RECT  0 63.984 0.084 64.008 ;
    END
  END q[469]
  PIN q[46]
    DIRECTION OUTPUT ;
    USE SIGNAL ;
    PORT
      LAYER M4 ;
        RECT  0 82.512 0.084 82.536 ;
    END
  END q[46]
  PIN q[470]
    DIRECTION OUTPUT ;
    USE SIGNAL ;
    PORT
      LAYER M4 ;
        RECT  0 64.08 0.084 64.104 ;
    END
  END q[470]
  PIN q[471]
    DIRECTION OUTPUT ;
    USE SIGNAL ;
    PORT
      LAYER M4 ;
        RECT  0 64.176 0.084 64.2 ;
    END
  END q[471]
  PIN q[472]
    DIRECTION OUTPUT ;
    USE SIGNAL ;
    PORT
      LAYER M4 ;
        RECT  0 64.272 0.084 64.296 ;
    END
  END q[472]
  PIN q[473]
    DIRECTION OUTPUT ;
    USE SIGNAL ;
    PORT
      LAYER M4 ;
        RECT  0 64.368 0.084 64.392 ;
    END
  END q[473]
  PIN q[474]
    DIRECTION OUTPUT ;
    USE SIGNAL ;
    PORT
      LAYER M4 ;
        RECT  0 64.464 0.084 64.488 ;
    END
  END q[474]
  PIN q[475]
    DIRECTION OUTPUT ;
    USE SIGNAL ;
    PORT
      LAYER M4 ;
        RECT  0 64.56 0.084 64.584 ;
    END
  END q[475]
  PIN q[476]
    DIRECTION OUTPUT ;
    USE SIGNAL ;
    PORT
      LAYER M4 ;
        RECT  0 64.656 0.084 64.68 ;
    END
  END q[476]
  PIN q[477]
    DIRECTION OUTPUT ;
    USE SIGNAL ;
    PORT
      LAYER M4 ;
        RECT  0 64.752 0.084 64.776 ;
    END
  END q[477]
  PIN q[478]
    DIRECTION OUTPUT ;
    USE SIGNAL ;
    PORT
      LAYER M4 ;
        RECT  0 64.848 0.084 64.872 ;
    END
  END q[478]
  PIN q[479]
    DIRECTION OUTPUT ;
    USE SIGNAL ;
    PORT
      LAYER M4 ;
        RECT  0 64.944 0.084 64.968 ;
    END
  END q[479]
  PIN q[47]
    DIRECTION OUTPUT ;
    USE SIGNAL ;
    PORT
      LAYER M4 ;
        RECT  0 82.608 0.084 82.632 ;
    END
  END q[47]
  PIN q[48]
    DIRECTION OUTPUT ;
    USE SIGNAL ;
    PORT
      LAYER M4 ;
        RECT  0 82.704 0.084 82.728 ;
    END
  END q[48]
  PIN q[49]
    DIRECTION OUTPUT ;
    USE SIGNAL ;
    PORT
      LAYER M4 ;
        RECT  0 82.8 0.084 82.824 ;
    END
  END q[49]
  PIN q[4]
    DIRECTION OUTPUT ;
    USE SIGNAL ;
    PORT
      LAYER M4 ;
        RECT  0 84.624 0.084 84.648 ;
    END
  END q[4]
  PIN q[50]
    DIRECTION OUTPUT ;
    USE SIGNAL ;
    PORT
      LAYER M4 ;
        RECT  0 82.896 0.084 82.92 ;
    END
  END q[50]
  PIN q[51]
    DIRECTION OUTPUT ;
    USE SIGNAL ;
    PORT
      LAYER M4 ;
        RECT  0 82.992 0.084 83.016 ;
    END
  END q[51]
  PIN q[52]
    DIRECTION OUTPUT ;
    USE SIGNAL ;
    PORT
      LAYER M4 ;
        RECT  0 83.088 0.084 83.112 ;
    END
  END q[52]
  PIN q[53]
    DIRECTION OUTPUT ;
    USE SIGNAL ;
    PORT
      LAYER M4 ;
        RECT  0 83.184 0.084 83.208 ;
    END
  END q[53]
  PIN q[54]
    DIRECTION OUTPUT ;
    USE SIGNAL ;
    PORT
      LAYER M4 ;
        RECT  0 83.28 0.084 83.304 ;
    END
  END q[54]
  PIN q[55]
    DIRECTION OUTPUT ;
    USE SIGNAL ;
    PORT
      LAYER M4 ;
        RECT  0 83.376 0.084 83.4 ;
    END
  END q[55]
  PIN q[56]
    DIRECTION OUTPUT ;
    USE SIGNAL ;
    PORT
      LAYER M4 ;
        RECT  0 83.472 0.084 83.496 ;
    END
  END q[56]
  PIN q[57]
    DIRECTION OUTPUT ;
    USE SIGNAL ;
    PORT
      LAYER M4 ;
        RECT  0 83.568 0.084 83.592 ;
    END
  END q[57]
  PIN q[58]
    DIRECTION OUTPUT ;
    USE SIGNAL ;
    PORT
      LAYER M4 ;
        RECT  0 83.664 0.084 83.688 ;
    END
  END q[58]
  PIN q[59]
    DIRECTION OUTPUT ;
    USE SIGNAL ;
    PORT
      LAYER M4 ;
        RECT  0 83.76 0.084 83.784 ;
    END
  END q[59]
  PIN q[5]
    DIRECTION OUTPUT ;
    USE SIGNAL ;
    PORT
      LAYER M4 ;
        RECT  0 84.72 0.084 84.744 ;
    END
  END q[5]
  PIN q[60]
    DIRECTION OUTPUT ;
    USE SIGNAL ;
    PORT
      LAYER M4 ;
        RECT  0 83.856 0.084 83.88 ;
    END
  END q[60]
  PIN q[61]
    DIRECTION OUTPUT ;
    USE SIGNAL ;
    PORT
      LAYER M4 ;
        RECT  0 83.952 0.084 83.976 ;
    END
  END q[61]
  PIN q[62]
    DIRECTION OUTPUT ;
    USE SIGNAL ;
    PORT
      LAYER M4 ;
        RECT  0 84.048 0.084 84.072 ;
    END
  END q[62]
  PIN q[63]
    DIRECTION OUTPUT ;
    USE SIGNAL ;
    PORT
      LAYER M4 ;
        RECT  0 84.144 0.084 84.168 ;
    END
  END q[63]
  PIN q[64]
    DIRECTION OUTPUT ;
    USE SIGNAL ;
    PORT
      LAYER M4 ;
        RECT  0 71.184 0.084 71.208 ;
    END
  END q[64]
  PIN q[65]
    DIRECTION OUTPUT ;
    USE SIGNAL ;
    PORT
      LAYER M4 ;
        RECT  0 71.28 0.084 71.304 ;
    END
  END q[65]
  PIN q[66]
    DIRECTION OUTPUT ;
    USE SIGNAL ;
    PORT
      LAYER M4 ;
        RECT  0 71.376 0.084 71.4 ;
    END
  END q[66]
  PIN q[67]
    DIRECTION OUTPUT ;
    USE SIGNAL ;
    PORT
      LAYER M4 ;
        RECT  0 71.472 0.084 71.496 ;
    END
  END q[67]
  PIN q[68]
    DIRECTION OUTPUT ;
    USE SIGNAL ;
    PORT
      LAYER M4 ;
        RECT  0 71.568 0.084 71.592 ;
    END
  END q[68]
  PIN q[69]
    DIRECTION OUTPUT ;
    USE SIGNAL ;
    PORT
      LAYER M4 ;
        RECT  0 71.664 0.084 71.688 ;
    END
  END q[69]
  PIN q[6]
    DIRECTION OUTPUT ;
    USE SIGNAL ;
    PORT
      LAYER M4 ;
        RECT  0 84.816 0.084 84.84 ;
    END
  END q[6]
  PIN q[70]
    DIRECTION OUTPUT ;
    USE SIGNAL ;
    PORT
      LAYER M4 ;
        RECT  0 71.76 0.084 71.784 ;
    END
  END q[70]
  PIN q[71]
    DIRECTION OUTPUT ;
    USE SIGNAL ;
    PORT
      LAYER M4 ;
        RECT  0 71.856 0.084 71.88 ;
    END
  END q[71]
  PIN q[72]
    DIRECTION OUTPUT ;
    USE SIGNAL ;
    PORT
      LAYER M4 ;
        RECT  0 71.952 0.084 71.976 ;
    END
  END q[72]
  PIN q[73]
    DIRECTION OUTPUT ;
    USE SIGNAL ;
    PORT
      LAYER M4 ;
        RECT  0 72.048 0.084 72.072 ;
    END
  END q[73]
  PIN q[74]
    DIRECTION OUTPUT ;
    USE SIGNAL ;
    PORT
      LAYER M4 ;
        RECT  0 72.144 0.084 72.168 ;
    END
  END q[74]
  PIN q[75]
    DIRECTION OUTPUT ;
    USE SIGNAL ;
    PORT
      LAYER M4 ;
        RECT  0 72.24 0.084 72.264 ;
    END
  END q[75]
  PIN q[76]
    DIRECTION OUTPUT ;
    USE SIGNAL ;
    PORT
      LAYER M4 ;
        RECT  0 72.336 0.084 72.36 ;
    END
  END q[76]
  PIN q[77]
    DIRECTION OUTPUT ;
    USE SIGNAL ;
    PORT
      LAYER M4 ;
        RECT  0 72.432 0.084 72.456 ;
    END
  END q[77]
  PIN q[78]
    DIRECTION OUTPUT ;
    USE SIGNAL ;
    PORT
      LAYER M4 ;
        RECT  0 72.528 0.084 72.552 ;
    END
  END q[78]
  PIN q[79]
    DIRECTION OUTPUT ;
    USE SIGNAL ;
    PORT
      LAYER M4 ;
        RECT  0 72.624 0.084 72.648 ;
    END
  END q[79]
  PIN q[7]
    DIRECTION OUTPUT ;
    USE SIGNAL ;
    PORT
      LAYER M4 ;
        RECT  0 84.912 0.084 84.936 ;
    END
  END q[7]
  PIN q[80]
    DIRECTION OUTPUT ;
    USE SIGNAL ;
    PORT
      LAYER M4 ;
        RECT  0 72.72 0.084 72.744 ;
    END
  END q[80]
  PIN q[81]
    DIRECTION OUTPUT ;
    USE SIGNAL ;
    PORT
      LAYER M4 ;
        RECT  0 72.816 0.084 72.84 ;
    END
  END q[81]
  PIN q[82]
    DIRECTION OUTPUT ;
    USE SIGNAL ;
    PORT
      LAYER M4 ;
        RECT  0 72.912 0.084 72.936 ;
    END
  END q[82]
  PIN q[83]
    DIRECTION OUTPUT ;
    USE SIGNAL ;
    PORT
      LAYER M4 ;
        RECT  0 73.008 0.084 73.032 ;
    END
  END q[83]
  PIN q[84]
    DIRECTION OUTPUT ;
    USE SIGNAL ;
    PORT
      LAYER M4 ;
        RECT  0 73.104 0.084 73.128 ;
    END
  END q[84]
  PIN q[85]
    DIRECTION OUTPUT ;
    USE SIGNAL ;
    PORT
      LAYER M4 ;
        RECT  0 73.2 0.084 73.224 ;
    END
  END q[85]
  PIN q[86]
    DIRECTION OUTPUT ;
    USE SIGNAL ;
    PORT
      LAYER M4 ;
        RECT  0 73.296 0.084 73.32 ;
    END
  END q[86]
  PIN q[87]
    DIRECTION OUTPUT ;
    USE SIGNAL ;
    PORT
      LAYER M4 ;
        RECT  0 73.392 0.084 73.416 ;
    END
  END q[87]
  PIN q[88]
    DIRECTION OUTPUT ;
    USE SIGNAL ;
    PORT
      LAYER M4 ;
        RECT  0 73.488 0.084 73.512 ;
    END
  END q[88]
  PIN q[89]
    DIRECTION OUTPUT ;
    USE SIGNAL ;
    PORT
      LAYER M4 ;
        RECT  0 73.584 0.084 73.608 ;
    END
  END q[89]
  PIN q[8]
    DIRECTION OUTPUT ;
    USE SIGNAL ;
    PORT
      LAYER M4 ;
        RECT  0 85.008 0.084 85.032 ;
    END
  END q[8]
  PIN q[90]
    DIRECTION OUTPUT ;
    USE SIGNAL ;
    PORT
      LAYER M4 ;
        RECT  0 73.68 0.084 73.704 ;
    END
  END q[90]
  PIN q[91]
    DIRECTION OUTPUT ;
    USE SIGNAL ;
    PORT
      LAYER M4 ;
        RECT  0 73.776 0.084 73.8 ;
    END
  END q[91]
  PIN q[92]
    DIRECTION OUTPUT ;
    USE SIGNAL ;
    PORT
      LAYER M4 ;
        RECT  0 73.872 0.084 73.896 ;
    END
  END q[92]
  PIN q[93]
    DIRECTION OUTPUT ;
    USE SIGNAL ;
    PORT
      LAYER M4 ;
        RECT  0 73.968 0.084 73.992 ;
    END
  END q[93]
  PIN q[94]
    DIRECTION OUTPUT ;
    USE SIGNAL ;
    PORT
      LAYER M4 ;
        RECT  0 74.064 0.084 74.088 ;
    END
  END q[94]
  PIN q[95]
    DIRECTION OUTPUT ;
    USE SIGNAL ;
    PORT
      LAYER M4 ;
        RECT  0 74.16 0.084 74.184 ;
    END
  END q[95]
  PIN q[96]
    DIRECTION OUTPUT ;
    USE SIGNAL ;
    PORT
      LAYER M4 ;
        RECT  0 78.096 0.084 78.12 ;
    END
  END q[96]
  PIN q[97]
    DIRECTION OUTPUT ;
    USE SIGNAL ;
    PORT
      LAYER M4 ;
        RECT  0 78.192 0.084 78.216 ;
    END
  END q[97]
  PIN q[98]
    DIRECTION OUTPUT ;
    USE SIGNAL ;
    PORT
      LAYER M4 ;
        RECT  0 78.288 0.084 78.312 ;
    END
  END q[98]
  PIN q[99]
    DIRECTION OUTPUT ;
    USE SIGNAL ;
    PORT
      LAYER M4 ;
        RECT  0 78.384 0.084 78.408 ;
    END
  END q[99]
  PIN q[9]
    DIRECTION OUTPUT ;
    USE SIGNAL ;
    PORT
      LAYER M4 ;
        RECT  0 85.104 0.084 85.128 ;
    END
  END q[9]
  PIN VSS
    DIRECTION INOUT ;
    USE GROUND ;
    PORT
      LAYER M5 ;
        RECT  13.2 2.137 13.32 95.063 ;
        RECT  7.8 2.137 7.92 95.063 ;
        RECT  2.4 2.137 2.52 95.063 ;
    END
  END VSS
  PIN VDD
    DIRECTION INOUT ;
    USE POWER ;
    PORT
      LAYER M5 ;
        RECT  13.392 2.151 13.512 95.049 ;
        RECT  7.992 2.151 8.112 95.049 ;
        RECT  2.592 2.151 2.712 95.049 ;
    END
  END VDD
  # OT_OBS_CLOSED layer=M5 d_um=1.536 added=203
  OBS
    LAYER RVTN ;
     RECT  2.16 2.16 15.12 2.295 ;
     RECT  2.16 2.565 15.12 2.835 ;
     RECT  2.16 3.105 15.12 3.375 ;
     RECT  2.16 3.645 15.12 3.915 ;
     RECT  2.16 4.185 15.12 4.455 ;
     RECT  2.16 4.725 15.12 4.995 ;
     RECT  2.16 5.265 15.12 5.535 ;
     RECT  2.16 5.805 15.12 6.075 ;
     RECT  2.16 6.345 15.12 6.615 ;
     RECT  2.16 6.885 15.12 7.155 ;
     RECT  2.16 7.425 15.12 7.695 ;
     RECT  2.16 7.965 15.12 8.235 ;
     RECT  2.16 8.505 15.12 8.775 ;
     RECT  2.16 9.045 15.12 9.315 ;
     RECT  2.16 9.585 15.12 9.855 ;
     RECT  2.16 10.125 15.12 10.395 ;
     RECT  2.16 10.665 15.12 10.935 ;
     RECT  2.16 11.205 15.12 11.475 ;
     RECT  2.16 11.745 15.12 12.015 ;
     RECT  2.16 12.285 15.12 12.555 ;
     RECT  2.16 12.825 15.12 13.095 ;
     RECT  2.16 13.365 15.12 13.635 ;
     RECT  2.16 13.905 15.12 14.175 ;
     RECT  2.16 14.445 15.12 14.715 ;
     RECT  2.16 14.985 15.12 15.255 ;
     RECT  2.16 15.525 15.12 15.795 ;
     RECT  2.16 16.065 15.12 16.335 ;
     RECT  2.16 16.605 15.12 16.875 ;
     RECT  2.16 17.145 15.12 17.415 ;
     RECT  2.16 17.685 15.12 17.955 ;
     RECT  2.16 18.225 15.12 18.495 ;
     RECT  2.16 18.765 15.12 19.035 ;
     RECT  2.16 19.305 15.12 19.575 ;
     RECT  2.16 19.845 15.12 20.115 ;
     RECT  2.16 20.385 15.12 20.655 ;
     RECT  2.16 20.925 15.12 21.195 ;
     RECT  2.16 21.465 15.12 21.735 ;
     RECT  2.16 22.005 15.12 22.275 ;
     RECT  2.16 22.545 15.12 22.815 ;
     RECT  2.16 23.085 15.12 23.355 ;
     RECT  2.16 23.625 15.12 23.895 ;
     RECT  2.16 24.165 15.12 24.435 ;
     RECT  2.16 24.705 15.12 24.975 ;
     RECT  2.16 25.245 15.12 25.515 ;
     RECT  2.16 25.785 15.12 26.055 ;
     RECT  2.16 26.325 15.12 26.595 ;
     RECT  2.16 26.865 15.12 27.135 ;
     RECT  2.16 27.405 15.12 27.675 ;
     RECT  2.16 27.945 15.12 28.215 ;
     RECT  2.16 28.485 15.12 28.755 ;
     RECT  2.16 29.025 15.12 29.295 ;
     RECT  2.16 29.565 15.12 29.835 ;
     RECT  2.16 30.105 15.12 30.375 ;
     RECT  2.16 30.645 15.12 30.915 ;
     RECT  2.16 31.185 15.12 31.455 ;
     RECT  2.16 31.725 15.12 31.995 ;
     RECT  2.16 32.265 15.12 32.535 ;
     RECT  2.16 32.805 15.12 33.075 ;
     RECT  2.16 33.345 15.12 33.615 ;
     RECT  2.16 33.885 15.12 34.155 ;
     RECT  2.16 34.425 15.12 34.695 ;
     RECT  2.16 34.965 15.12 35.235 ;
     RECT  2.16 35.505 15.12 35.775 ;
     RECT  2.16 36.045 15.12 36.315 ;
     RECT  2.16 36.585 15.12 36.855 ;
     RECT  2.16 37.125 15.12 37.395 ;
     RECT  2.16 37.665 15.12 37.935 ;
     RECT  2.16 38.205 15.12 38.475 ;
     RECT  2.16 38.745 15.12 39.015 ;
     RECT  2.16 39.285 15.12 39.555 ;
     RECT  2.16 39.825 15.12 40.095 ;
     RECT  2.16 40.365 15.12 40.635 ;
     RECT  2.16 40.905 15.12 41.175 ;
     RECT  2.16 41.445 15.12 41.715 ;
     RECT  2.16 41.985 15.12 42.255 ;
     RECT  2.16 42.525 15.12 42.795 ;
     RECT  2.16 43.065 15.12 43.335 ;
     RECT  2.16 43.605 15.12 43.875 ;
     RECT  2.16 44.145 15.12 44.415 ;
     RECT  2.16 44.685 15.12 44.955 ;
     RECT  2.16 45.225 15.12 45.495 ;
     RECT  2.16 45.765 15.12 46.035 ;
     RECT  2.16 46.305 15.12 46.575 ;
     RECT  2.16 46.845 15.12 47.115 ;
     RECT  2.16 47.385 15.12 47.655 ;
     RECT  2.16 47.925 15.12 48.195 ;
     RECT  2.16 48.465 15.12 48.735 ;
     RECT  2.16 49.005 15.12 49.275 ;
     RECT  2.16 49.545 15.12 49.815 ;
     RECT  2.16 50.085 15.12 50.355 ;
     RECT  2.16 50.625 15.12 50.895 ;
     RECT  2.16 51.165 15.12 51.435 ;
     RECT  2.16 51.705 15.12 51.975 ;
     RECT  2.16 52.245 15.12 52.515 ;
     RECT  2.16 52.785 15.12 53.055 ;
     RECT  2.16 53.325 15.12 53.595 ;
     RECT  2.16 53.865 15.12 54.135 ;
     RECT  2.16 54.405 15.12 54.675 ;
     RECT  2.16 54.945 15.12 55.215 ;
     RECT  2.16 55.485 15.12 55.755 ;
     RECT  2.16 56.025 15.12 56.295 ;
     RECT  2.16 56.565 15.12 56.835 ;
     RECT  2.16 57.105 15.12 57.375 ;
     RECT  2.16 57.645 15.12 57.915 ;
     RECT  2.16 58.185 15.12 58.455 ;
     RECT  2.16 58.725 15.12 58.995 ;
     RECT  2.16 59.265 15.12 59.535 ;
     RECT  2.16 59.805 15.12 60.075 ;
     RECT  2.16 60.345 15.12 60.615 ;
     RECT  2.16 60.885 15.12 61.155 ;
     RECT  2.16 61.425 15.12 61.695 ;
     RECT  2.16 61.965 15.12 62.235 ;
     RECT  2.16 62.505 15.12 62.775 ;
     RECT  2.16 63.045 15.12 63.315 ;
     RECT  2.16 63.585 15.12 63.855 ;
     RECT  2.16 64.125 15.12 64.395 ;
     RECT  2.16 64.665 15.12 64.935 ;
     RECT  2.16 65.205 15.12 65.475 ;
     RECT  2.16 65.745 15.12 66.015 ;
     RECT  2.16 66.285 15.12 66.555 ;
     RECT  2.16 66.825 15.12 67.095 ;
     RECT  2.16 67.365 15.12 67.635 ;
     RECT  2.16 67.905 15.12 68.175 ;
     RECT  2.16 68.445 15.12 68.715 ;
     RECT  2.16 68.985 15.12 69.255 ;
     RECT  2.16 69.525 15.12 69.795 ;
     RECT  2.16 70.065 15.12 70.335 ;
     RECT  2.16 70.605 15.12 70.875 ;
     RECT  2.16 71.145 15.12 71.415 ;
     RECT  2.16 71.685 15.12 71.955 ;
     RECT  2.16 72.225 15.12 72.495 ;
     RECT  2.16 72.765 15.12 73.035 ;
     RECT  2.16 73.305 15.12 73.575 ;
     RECT  2.16 73.845 15.12 74.115 ;
     RECT  2.16 74.385 15.12 74.655 ;
     RECT  2.16 74.925 15.12 75.195 ;
     RECT  2.16 75.465 15.12 75.735 ;
     RECT  2.16 76.005 15.12 76.275 ;
     RECT  2.16 76.545 15.12 76.815 ;
     RECT  2.16 77.085 15.12 77.355 ;
     RECT  2.16 77.625 15.12 77.895 ;
     RECT  2.16 78.165 15.12 78.435 ;
     RECT  2.16 78.705 15.12 78.975 ;
     RECT  2.16 79.245 15.12 79.515 ;
     RECT  2.16 79.785 15.12 80.055 ;
     RECT  2.16 80.325 15.12 80.595 ;
     RECT  2.16 80.865 15.12 81.135 ;
     RECT  2.16 81.405 15.12 81.675 ;
     RECT  2.16 81.945 15.12 82.215 ;
     RECT  2.16 82.485 15.12 82.755 ;
     RECT  2.16 83.025 15.12 83.295 ;
     RECT  2.16 83.565 15.12 83.835 ;
     RECT  2.16 84.105 15.12 84.375 ;
     RECT  2.16 84.645 15.12 84.915 ;
     RECT  2.16 85.185 15.12 85.455 ;
     RECT  2.16 85.725 15.12 85.995 ;
     RECT  2.16 86.265 15.12 86.535 ;
     RECT  2.16 86.805 15.12 87.075 ;
     RECT  2.16 87.345 15.12 87.615 ;
     RECT  2.16 87.885 15.12 88.155 ;
     RECT  2.16 88.425 15.12 88.695 ;
     RECT  2.16 88.965 15.12 89.235 ;
     RECT  2.16 89.505 15.12 89.775 ;
     RECT  2.16 90.045 15.12 90.315 ;
     RECT  2.16 90.585 15.12 90.855 ;
     RECT  2.16 91.125 15.12 91.395 ;
     RECT  2.16 91.665 15.12 91.935 ;
     RECT  2.16 92.205 15.12 92.475 ;
     RECT  2.16 92.745 15.12 93.015 ;
     RECT  2.16 93.285 15.12 93.555 ;
     RECT  2.16 93.825 15.12 94.095 ;
     RECT  2.16 94.365 15.12 94.635 ;
     RECT  2.16 94.905 15.12 95.04 ;
    LAYER RVTP ;
     RECT  2.16 2.295 15.12 2.565 ;
     RECT  2.16 2.835 15.12 3.105 ;
     RECT  2.16 3.375 15.12 3.645 ;
     RECT  2.16 3.915 15.12 4.185 ;
     RECT  2.16 4.455 15.12 4.725 ;
     RECT  2.16 4.995 15.12 5.265 ;
     RECT  2.16 5.535 15.12 5.805 ;
     RECT  2.16 6.075 15.12 6.345 ;
     RECT  2.16 6.615 15.12 6.885 ;
     RECT  2.16 7.155 15.12 7.425 ;
     RECT  2.16 7.695 15.12 7.965 ;
     RECT  2.16 8.235 15.12 8.505 ;
     RECT  2.16 8.775 15.12 9.045 ;
     RECT  2.16 9.315 15.12 9.585 ;
     RECT  2.16 9.855 15.12 10.125 ;
     RECT  2.16 10.395 15.12 10.665 ;
     RECT  2.16 10.935 15.12 11.205 ;
     RECT  2.16 11.475 15.12 11.745 ;
     RECT  2.16 12.015 15.12 12.285 ;
     RECT  2.16 12.555 15.12 12.825 ;
     RECT  2.16 13.095 15.12 13.365 ;
     RECT  2.16 13.635 15.12 13.905 ;
     RECT  2.16 14.175 15.12 14.445 ;
     RECT  2.16 14.715 15.12 14.985 ;
     RECT  2.16 15.255 15.12 15.525 ;
     RECT  2.16 15.795 15.12 16.065 ;
     RECT  2.16 16.335 15.12 16.605 ;
     RECT  2.16 16.875 15.12 17.145 ;
     RECT  2.16 17.415 15.12 17.685 ;
     RECT  2.16 17.955 15.12 18.225 ;
     RECT  2.16 18.495 15.12 18.765 ;
     RECT  2.16 19.035 15.12 19.305 ;
     RECT  2.16 19.575 15.12 19.845 ;
     RECT  2.16 20.115 15.12 20.385 ;
     RECT  2.16 20.655 15.12 20.925 ;
     RECT  2.16 21.195 15.12 21.465 ;
     RECT  2.16 21.735 15.12 22.005 ;
     RECT  2.16 22.275 15.12 22.545 ;
     RECT  2.16 22.815 15.12 23.085 ;
     RECT  2.16 23.355 15.12 23.625 ;
     RECT  2.16 23.895 15.12 24.165 ;
     RECT  2.16 24.435 15.12 24.705 ;
     RECT  2.16 24.975 15.12 25.245 ;
     RECT  2.16 25.515 15.12 25.785 ;
     RECT  2.16 26.055 15.12 26.325 ;
     RECT  2.16 26.595 15.12 26.865 ;
     RECT  2.16 27.135 15.12 27.405 ;
     RECT  2.16 27.675 15.12 27.945 ;
     RECT  2.16 28.215 15.12 28.485 ;
     RECT  2.16 28.755 15.12 29.025 ;
     RECT  2.16 29.295 15.12 29.565 ;
     RECT  2.16 29.835 15.12 30.105 ;
     RECT  2.16 30.375 15.12 30.645 ;
     RECT  2.16 30.915 15.12 31.185 ;
     RECT  2.16 31.455 15.12 31.725 ;
     RECT  2.16 31.995 15.12 32.265 ;
     RECT  2.16 32.535 15.12 32.805 ;
     RECT  2.16 33.075 15.12 33.345 ;
     RECT  2.16 33.615 15.12 33.885 ;
     RECT  2.16 34.155 15.12 34.425 ;
     RECT  2.16 34.695 15.12 34.965 ;
     RECT  2.16 35.235 15.12 35.505 ;
     RECT  2.16 35.775 15.12 36.045 ;
     RECT  2.16 36.315 15.12 36.585 ;
     RECT  2.16 36.855 15.12 37.125 ;
     RECT  2.16 37.395 15.12 37.665 ;
     RECT  2.16 37.935 15.12 38.205 ;
     RECT  2.16 38.475 15.12 38.745 ;
     RECT  2.16 39.015 15.12 39.285 ;
     RECT  2.16 39.555 15.12 39.825 ;
     RECT  2.16 40.095 15.12 40.365 ;
     RECT  2.16 40.635 15.12 40.905 ;
     RECT  2.16 41.175 15.12 41.445 ;
     RECT  2.16 41.715 15.12 41.985 ;
     RECT  2.16 42.255 15.12 42.525 ;
     RECT  2.16 42.795 15.12 43.065 ;
     RECT  2.16 43.335 15.12 43.605 ;
     RECT  2.16 43.875 15.12 44.145 ;
     RECT  2.16 44.415 15.12 44.685 ;
     RECT  2.16 44.955 15.12 45.225 ;
     RECT  2.16 45.495 15.12 45.765 ;
     RECT  2.16 46.035 15.12 46.305 ;
     RECT  2.16 46.575 15.12 46.845 ;
     RECT  2.16 47.115 15.12 47.385 ;
     RECT  2.16 47.655 15.12 47.925 ;
     RECT  2.16 48.195 15.12 48.465 ;
     RECT  2.16 48.735 15.12 49.005 ;
     RECT  2.16 49.275 15.12 49.545 ;
     RECT  2.16 49.815 15.12 50.085 ;
     RECT  2.16 50.355 15.12 50.625 ;
     RECT  2.16 50.895 15.12 51.165 ;
     RECT  2.16 51.435 15.12 51.705 ;
     RECT  2.16 51.975 15.12 52.245 ;
     RECT  2.16 52.515 15.12 52.785 ;
     RECT  2.16 53.055 15.12 53.325 ;
     RECT  2.16 53.595 15.12 53.865 ;
     RECT  2.16 54.135 15.12 54.405 ;
     RECT  2.16 54.675 15.12 54.945 ;
     RECT  2.16 55.215 15.12 55.485 ;
     RECT  2.16 55.755 15.12 56.025 ;
     RECT  2.16 56.295 15.12 56.565 ;
     RECT  2.16 56.835 15.12 57.105 ;
     RECT  2.16 57.375 15.12 57.645 ;
     RECT  2.16 57.915 15.12 58.185 ;
     RECT  2.16 58.455 15.12 58.725 ;
     RECT  2.16 58.995 15.12 59.265 ;
     RECT  2.16 59.535 15.12 59.805 ;
     RECT  2.16 60.075 15.12 60.345 ;
     RECT  2.16 60.615 15.12 60.885 ;
     RECT  2.16 61.155 15.12 61.425 ;
     RECT  2.16 61.695 15.12 61.965 ;
     RECT  2.16 62.235 15.12 62.505 ;
     RECT  2.16 62.775 15.12 63.045 ;
     RECT  2.16 63.315 15.12 63.585 ;
     RECT  2.16 63.855 15.12 64.125 ;
     RECT  2.16 64.395 15.12 64.665 ;
     RECT  2.16 64.935 15.12 65.205 ;
     RECT  2.16 65.475 15.12 65.745 ;
     RECT  2.16 66.015 15.12 66.285 ;
     RECT  2.16 66.555 15.12 66.825 ;
     RECT  2.16 67.095 15.12 67.365 ;
     RECT  2.16 67.635 15.12 67.905 ;
     RECT  2.16 68.175 15.12 68.445 ;
     RECT  2.16 68.715 15.12 68.985 ;
     RECT  2.16 69.255 15.12 69.525 ;
     RECT  2.16 69.795 15.12 70.065 ;
     RECT  2.16 70.335 15.12 70.605 ;
     RECT  2.16 70.875 15.12 71.145 ;
     RECT  2.16 71.415 15.12 71.685 ;
     RECT  2.16 71.955 15.12 72.225 ;
     RECT  2.16 72.495 15.12 72.765 ;
     RECT  2.16 73.035 15.12 73.305 ;
     RECT  2.16 73.575 15.12 73.845 ;
     RECT  2.16 74.115 15.12 74.385 ;
     RECT  2.16 74.655 15.12 74.925 ;
     RECT  2.16 75.195 15.12 75.465 ;
     RECT  2.16 75.735 15.12 76.005 ;
     RECT  2.16 76.275 15.12 76.545 ;
     RECT  2.16 76.815 15.12 77.085 ;
     RECT  2.16 77.355 15.12 77.625 ;
     RECT  2.16 77.895 15.12 78.165 ;
     RECT  2.16 78.435 15.12 78.705 ;
     RECT  2.16 78.975 15.12 79.245 ;
     RECT  2.16 79.515 15.12 79.785 ;
     RECT  2.16 80.055 15.12 80.325 ;
     RECT  2.16 80.595 15.12 80.865 ;
     RECT  2.16 81.135 15.12 81.405 ;
     RECT  2.16 81.675 15.12 81.945 ;
     RECT  2.16 82.215 15.12 82.485 ;
     RECT  2.16 82.755 15.12 83.025 ;
     RECT  2.16 83.295 15.12 83.565 ;
     RECT  2.16 83.835 15.12 84.105 ;
     RECT  2.16 84.375 15.12 84.645 ;
     RECT  2.16 84.915 15.12 85.185 ;
     RECT  2.16 85.455 15.12 85.725 ;
     RECT  2.16 85.995 15.12 86.265 ;
     RECT  2.16 86.535 15.12 86.805 ;
     RECT  2.16 87.075 15.12 87.345 ;
     RECT  2.16 87.615 15.12 87.885 ;
     RECT  2.16 88.155 15.12 88.425 ;
     RECT  2.16 88.695 15.12 88.965 ;
     RECT  2.16 89.235 15.12 89.505 ;
     RECT  2.16 89.775 15.12 90.045 ;
     RECT  2.16 90.315 15.12 90.585 ;
     RECT  2.16 90.855 15.12 91.125 ;
     RECT  2.16 91.395 15.12 91.665 ;
     RECT  2.16 91.935 15.12 92.205 ;
     RECT  2.16 92.475 15.12 92.745 ;
     RECT  2.16 93.015 15.12 93.285 ;
     RECT  2.16 93.555 15.12 93.825 ;
     RECT  2.16 94.095 15.12 94.365 ;
     RECT  2.16 94.635 15.12 94.905 ;
    LAYER M1 ;
     RECT  2.16 2.151 15.12 95.049 ;
    LAYER M2 ;
     RECT  0.031 18.702 0.067 18.72 ;
     RECT  0.067 2.736 0.103 2.754 ;
     RECT  0.031 21.744 0.103 21.762 ;
     RECT  0.031 54.684 0.103 54.702 ;
     RECT  0.031 57.348 0.103 57.366 ;
     RECT  0.031 59.472 0.103 59.49 ;
     RECT  0.067 87.048 0.103 87.066 ;
     RECT  0.103 6.156 0.139 6.534 ;
     RECT  0.103 13.068 0.139 13.086 ;
     RECT  0.067 20.664 0.139 20.682 ;
     RECT  0.103 21.636 0.139 22.194 ;
     RECT  0.103 31.896 0.139 32.364 ;
     RECT  0.103 54.684 0.139 55.512 ;
     RECT  0.103 57.348 0.139 57.564 ;
     RECT  0.103 75.906 0.139 75.924 ;
     RECT  0.103 79.056 0.139 79.074 ;
     RECT  0.139 20.664 0.167 22.194 ;
     RECT  0.103 86.742 0.167 87.066 ;
     RECT  0.103 59.238 0.175 59.49 ;
     RECT  0.103 60.786 0.175 61.344 ;
     RECT  0.103 71.586 0.175 71.604 ;
     RECT  0.139 79.056 0.175 79.542 ;
     RECT  0.103 81.882 0.175 81.9 ;
     RECT  0.103 39.294 0.203 40.014 ;
     RECT  0.175 60.786 0.203 61.686 ;
     RECT  0.103 64.404 0.203 64.422 ;
     RECT  0.103 2.736 0.211 3.294 ;
     RECT  0.139 13.068 0.211 13.554 ;
     RECT  0.139 28.224 0.211 28.242 ;
     RECT  0.139 45.396 0.211 45.414 ;
     RECT  0.175 46.476 0.211 46.494 ;
     RECT  0.175 53.766 0.211 53.784 ;
     RECT  0.139 54.576 0.211 55.512 ;
     RECT  0.203 61.326 0.211 61.686 ;
     RECT  0.103 62.676 0.211 62.694 ;
     RECT  0.175 77.796 0.211 77.814 ;
     RECT  0.167 86.742 0.239 86.76 ;
     RECT  0.211 2.736 0.247 3.564 ;
     RECT  0.211 53.766 0.247 55.512 ;
     RECT  0.031 56.376 0.247 56.394 ;
     RECT  0.211 58.464 0.247 58.482 ;
     RECT  0.175 59.238 0.247 59.634 ;
     RECT  0.211 77.436 0.247 77.814 ;
     RECT  0.175 78.606 0.247 79.542 ;
     RECT  0.139 9.396 0.275 9.414 ;
     RECT  0.139 4.581 0.283 4.599 ;
     RECT  0.139 31.896 0.283 32.904 ;
     RECT  0.103 34.704 0.347 35.154 ;
     RECT  0.247 53.766 0.427 56.394 ;
     RECT  0.139 57.276 0.427 57.564 ;
     RECT  0.283 4.581 0.463 4.644 ;
     RECT  0.139 5.976 0.463 6.534 ;
     RECT  0.247 2.736 0.499 3.834 ;
     RECT  0.463 4.581 0.499 4.716 ;
     RECT  0.463 5.616 0.499 6.534 ;
     RECT  0.499 2.736 0.535 6.534 ;
     RECT  0.211 28.224 0.535 28.404 ;
     RECT  0.103 29.466 0.535 29.484 ;
     RECT  0.175 30.726 0.535 30.744 ;
     RECT  0.283 31.896 0.535 33.336 ;
     RECT  0.211 45.396 0.535 46.494 ;
     RECT  0.427 53.766 0.535 57.564 ;
     RECT  0.247 58.464 0.535 59.634 ;
     RECT  0.103 67.338 0.535 67.356 ;
     RECT  0.175 70.506 0.535 70.524 ;
     RECT  0.103 72.936 0.535 73.494 ;
     RECT  0.247 77.436 0.535 79.542 ;
     RECT  0.103 80.298 0.535 80.784 ;
     RECT  0.175 81.846 0.535 81.9 ;
     RECT  0.571 86.706 1.111 86.724 ;
     RECT  0.535 28.224 1.147 29.484 ;
     RECT  1.111 86.706 1.723 87.066 ;
     RECT  1.219 88.866 1.723 88.884 ;
     RECT  0.067 18.198 1.759 18.72 ;
     RECT  1.723 43.776 1.759 43.794 ;
     RECT  1.723 65.25 1.759 65.268 ;
     RECT  1.759 18.126 1.795 18.72 ;
     RECT  1.795 17.388 1.831 18.72 ;
     RECT  1.723 86.346 1.903 87.066 ;
     RECT  1.831 17.154 1.939 18.72 ;
     RECT  1.723 88.326 1.975 88.884 ;
     RECT  1.975 88.236 2.011 88.884 ;
     RECT  1.903 86.04 2.119 87.066 ;
     RECT  1.903 93.294 2.119 93.312 ;
     RECT  1.939 16.884 2.155 18.72 ;
     RECT  2.119 86.04 2.155 87.138 ;
     RECT  2.011 88.2 2.155 88.884 ;
     RECT  2.119 93.294 2.155 93.384 ;
     RECT  0.535 2.736 2.16 6.642 ;
     RECT  0.103 7.668 2.16 7.686 ;
     RECT  0.103 11.214 2.16 11.232 ;
     RECT  0.211 13.068 2.16 14.094 ;
     RECT  0.103 15.156 2.16 15.174 ;
     RECT  2.155 16.308 2.16 18.72 ;
     RECT  0.103 19.656 2.16 19.674 ;
     RECT  0.167 20.934 2.16 22.194 ;
     RECT  1.975 24.444 2.16 24.462 ;
     RECT  1.147 27.576 2.16 29.484 ;
     RECT  0.535 30.726 2.16 33.336 ;
     RECT  0.347 35.136 2.16 35.154 ;
     RECT  1.723 36.324 2.16 36.342 ;
     RECT  0.203 39.294 2.16 39.888 ;
     RECT  0.103 40.806 2.16 40.824 ;
     RECT  0.535 42.066 2.16 42.084 ;
     RECT  1.759 43.686 2.16 43.794 ;
     RECT  0.535 45.396 2.16 46.836 ;
     RECT  1.147 50.796 2.16 50.814 ;
     RECT  0.535 53.766 2.16 59.634 ;
     RECT  0.211 61.326 2.16 62.694 ;
     RECT  0.247 63.486 2.16 63.504 ;
     RECT  1.759 65.25 2.16 65.574 ;
     RECT  0.535 67.338 2.16 67.464 ;
     RECT  0.535 69.804 2.16 70.524 ;
     RECT  0.175 71.586 2.16 71.784 ;
     RECT  0.535 72.738 2.16 73.494 ;
     RECT  0.139 75.906 2.16 76.644 ;
     RECT  0.535 77.436 2.16 80.784 ;
     RECT  0.535 81.846 2.16 81.972 ;
     RECT  2.155 85.5 2.16 87.336 ;
     RECT  2.155 88.2 2.16 89.334 ;
     RECT  0.067 90.936 2.16 90.954 ;
     RECT  0.031 92.106 2.16 92.124 ;
     RECT  2.155 93.294 2.16 93.474 ;
     RECT  2.16 2.151 3.415 95.049 ;
     RECT  3.415 2.106 6.395 95.049 ;
     RECT  6.395 2.151 15.12 95.049 ;
     RECT  15.12 87.39 15.323 93.582 ;
     RECT  15.12 30.114 15.395 38.538 ;
     RECT  15.12 3.348 15.431 14.472 ;
     RECT  15.12 71.424 15.431 76.338 ;
     RECT  15.323 87.39 15.431 93.348 ;
     RECT  15.12 58.5 15.467 60.678 ;
     RECT  15.12 77.364 15.503 85.446 ;
     RECT  15.503 77.436 15.539 85.446 ;
     RECT  15.431 3.348 15.683 5.832 ;
     RECT  15.539 77.634 15.683 85.446 ;
     RECT  15.12 28.188 15.755 29.358 ;
     RECT  15.431 87.894 15.863 93.348 ;
     RECT  15.431 9.324 15.971 14.472 ;
     RECT  15.12 15.3 15.971 20.34 ;
     RECT  15.12 22.05 15.971 26.316 ;
     RECT  15.12 46.854 15.971 51.426 ;
     RECT  15.12 61.434 15.971 69.48 ;
     RECT  15.863 87.894 15.971 93.114 ;
     RECT  15.683 3.42 16.007 5.832 ;
     RECT  15.431 6.822 16.007 8.532 ;
     RECT  15.971 15.3 16.007 19.134 ;
     RECT  15.971 22.05 16.007 25.848 ;
     RECT  15.395 30.114 16.007 38.268 ;
     RECT  15.12 39.762 16.007 39.78 ;
     RECT  15.12 41.22 16.007 46.098 ;
     RECT  15.971 46.854 16.007 49.842 ;
     RECT  15.467 60.66 16.007 60.678 ;
     RECT  15.431 71.424 16.007 76.266 ;
     RECT  16.007 3.42 16.043 5.796 ;
     RECT  16.007 8.244 16.043 8.532 ;
     RECT  16.007 30.114 16.043 35.064 ;
     RECT  16.007 41.22 16.043 44.208 ;
     RECT  15.12 52.794 16.043 57.474 ;
     RECT  15.971 61.434 16.043 64.89 ;
     RECT  16.043 8.244 16.079 8.334 ;
     RECT  16.043 52.794 16.079 54.936 ;
     RECT  16.043 31.428 16.115 35.064 ;
     RECT  16.115 31.428 16.151 33.606 ;
     RECT  16.043 3.42 16.259 3.708 ;
     RECT  15.755 28.188 16.259 29.322 ;
     RECT  15.683 83.232 16.259 85.446 ;
     RECT  16.259 28.188 16.295 28.314 ;
     RECT  16.259 83.772 16.295 85.446 ;
     RECT  16.295 28.296 16.367 28.314 ;
     RECT  16.295 83.772 16.367 85.176 ;
     RECT  16.043 30.114 16.439 30.474 ;
     RECT  16.043 41.76 16.511 44.208 ;
     RECT  16.007 44.964 16.511 46.098 ;
     RECT  16.043 61.506 16.511 64.89 ;
     RECT  15.683 77.634 16.511 82.008 ;
     RECT  16.043 4.5 16.547 5.796 ;
     RECT  16.079 8.316 16.547 8.334 ;
     RECT  16.007 15.3 16.547 15.318 ;
     RECT  16.007 16.236 16.547 19.134 ;
     RECT  16.007 22.05 16.547 22.464 ;
     RECT  16.007 23.598 16.547 25.848 ;
     RECT  16.151 31.428 16.547 33.444 ;
     RECT  16.115 34.506 16.547 35.064 ;
     RECT  16.007 35.82 16.547 38.268 ;
     RECT  16.511 41.994 16.547 43.254 ;
     RECT  16.511 44.19 16.547 44.208 ;
     RECT  16.511 45 16.547 46.098 ;
     RECT  16.007 46.854 16.547 49.104 ;
     RECT  15.971 50.904 16.547 51.156 ;
     RECT  16.079 52.794 16.547 53.01 ;
     RECT  16.043 55.836 16.547 57.474 ;
     RECT  15.467 58.5 16.547 59.832 ;
     RECT  16.511 61.506 16.547 64.764 ;
     RECT  16.007 71.424 16.547 76.068 ;
     RECT  16.511 77.634 16.547 78.534 ;
     RECT  16.511 79.29 16.547 82.008 ;
     RECT  15.971 87.894 16.547 91.494 ;
     RECT  16.547 16.308 16.583 16.326 ;
     RECT  16.547 22.05 16.583 22.068 ;
     RECT  16.547 23.706 16.583 24.228 ;
     RECT  16.547 32.202 16.583 33.444 ;
     RECT  16.547 42.426 16.583 42.444 ;
     RECT  16.547 47.592 16.583 48.996 ;
     RECT  16.079 53.802 16.583 54.936 ;
     RECT  16.547 55.836 16.583 57.438 ;
     RECT  16.547 59.58 16.583 59.832 ;
     RECT  16.547 71.694 16.583 75.834 ;
     RECT  16.547 77.634 16.583 78.462 ;
     RECT  16.547 87.894 16.583 89.874 ;
     RECT  15.971 9.324 16.619 10.152 ;
     RECT  16.547 17.154 16.619 19.134 ;
     RECT  16.583 32.202 16.619 33.372 ;
     RECT  16.583 53.802 16.619 53.82 ;
     RECT  16.583 59.58 16.619 59.796 ;
     RECT  16.583 71.73 16.619 75.834 ;
     RECT  16.583 77.904 16.619 78.462 ;
     RECT  16.583 88.704 16.619 89.874 ;
     RECT  16.007 6.822 16.655 7.254 ;
     RECT  16.619 9.324 16.655 9.684 ;
     RECT  16.547 31.428 16.655 31.446 ;
     RECT  16.547 34.506 16.655 34.956 ;
     RECT  16.583 47.592 16.655 47.88 ;
     RECT  16.547 52.794 16.655 52.884 ;
     RECT  16.547 61.506 16.655 61.794 ;
     RECT  16.619 71.73 16.655 75.294 ;
     RECT  16.367 83.772 16.655 84.87 ;
     RECT  16.619 89.856 16.655 89.874 ;
     RECT  16.655 9.324 16.691 9.342 ;
     RECT  16.619 32.202 16.691 32.22 ;
     RECT  16.655 47.862 16.691 47.88 ;
     RECT  16.655 52.866 16.691 52.884 ;
     RECT  16.655 71.964 16.691 75.294 ;
     RECT  16.655 83.772 16.691 84.096 ;
     RECT  16.583 48.636 16.727 48.996 ;
     RECT  16.583 54.918 16.727 54.936 ;
     RECT  16.691 71.964 16.727 72.45 ;
     RECT  16.655 84.852 16.727 84.87 ;
     RECT  16.619 33.012 16.763 33.372 ;
     RECT  16.655 34.506 16.763 34.524 ;
     RECT  16.727 72.27 16.763 72.45 ;
     RECT  16.763 72.432 16.799 72.45 ;
     RECT  16.691 73.476 16.835 75.294 ;
     RECT  16.835 73.512 16.871 75.294 ;
     RECT  16.871 73.512 16.907 73.53 ;
     RECT  16.871 74.511 16.907 74.529 ;
     RECT  16.547 4.662 17.015 5.796 ;
     RECT  15.971 65.718 17.015 69.48 ;
     RECT  17.015 5.778 17.051 5.796 ;
     RECT  15.971 13.068 17.051 14.472 ;
     RECT  16.547 79.596 17.051 82.008 ;
     RECT  16.655 6.822 17.087 6.948 ;
     RECT  17.051 13.068 17.087 13.428 ;
     RECT  16.619 18.774 17.087 19.134 ;
     RECT  17.015 65.718 17.087 68.4 ;
     RECT  17.015 69.3 17.087 69.48 ;
     RECT  17.051 80.136 17.087 81.738 ;
     RECT  15.12 86.544 17.087 86.562 ;
     RECT  17.015 4.662 17.123 4.68 ;
     RECT  17.087 13.068 17.123 13.194 ;
     RECT  17.087 18.774 17.123 18.99 ;
     RECT  17.087 66.366 17.123 68.4 ;
     RECT  17.087 69.462 17.123 69.48 ;
     RECT  16.871 75.276 17.123 75.294 ;
     RECT  17.087 81.108 17.123 81.738 ;
     RECT  16.547 91.368 17.123 91.494 ;
     RECT  17.051 14.454 17.159 14.472 ;
     RECT  15.971 19.89 17.159 20.34 ;
     RECT  16.547 24.984 17.159 25.848 ;
     RECT  16.547 37.134 17.159 38.268 ;
     RECT  16.547 45.27 17.159 46.098 ;
     RECT  16.547 50.94 17.159 50.994 ;
     RECT  16.619 59.778 17.159 59.796 ;
     RECT  16.547 64.476 17.159 64.728 ;
     RECT  17.123 66.366 17.159 66.888 ;
     RECT  17.123 67.842 17.159 68.4 ;
     RECT  17.123 81.108 17.159 81.126 ;
     RECT  17.123 91.404 17.159 91.494 ;
     RECT  15.971 93.024 17.159 93.114 ;
     RECT  15.971 10.908 17.195 12.312 ;
     RECT  17.123 13.068 17.195 13.086 ;
     RECT  16.619 17.766 17.195 17.946 ;
     RECT  17.123 18.774 17.195 18.792 ;
     RECT  16.583 23.868 17.195 24.228 ;
     RECT  17.159 25.326 17.195 25.776 ;
     RECT  17.159 37.134 17.195 37.494 ;
     RECT  17.159 38.25 17.195 38.268 ;
     RECT  16.547 43.236 17.195 43.254 ;
     RECT  17.159 45.396 17.195 46.098 ;
     RECT  16.727 48.978 17.195 48.996 ;
     RECT  17.159 50.94 17.195 50.958 ;
     RECT  16.583 56.106 17.195 56.124 ;
     RECT  16.583 56.916 17.195 57.438 ;
     RECT  17.159 64.71 17.195 64.728 ;
     RECT  17.159 66.366 17.195 66.384 ;
     RECT  17.159 68.382 17.195 68.4 ;
     RECT  16.619 78.444 17.195 78.462 ;
     RECT  17.087 80.136 17.195 80.154 ;
     RECT  16.583 87.894 17.195 87.912 ;
     RECT  17.159 91.476 17.195 91.494 ;
     RECT  15.971 92.25 17.195 92.268 ;
     RECT  17.159 93.096 17.195 93.114 ;
     RECT  16.259 29.304 17.231 29.322 ;
     RECT  16.691 83.772 17.231 83.79 ;
     RECT  16.259 3.69 17.267 3.708 ;
     RECT  17.087 6.93 17.267 6.948 ;
     RECT  17.195 17.928 17.267 17.946 ;
     RECT  17.159 20.322 17.267 20.34 ;
     RECT  16.439 30.114 17.267 30.132 ;
     RECT  16.763 33.354 17.267 33.372 ;
     RECT  17.195 46.08 17.267 46.098 ;
     RECT  16.547 58.5 17.267 58.518 ;
     RECT  16.655 61.776 17.267 61.794 ;
    LAYER M3 ;
     RECT  4.536 1.723 4.554 2.191 ;
     RECT  6.372 2.101 6.39 2.191 ;
     RECT  4.536 2.191 4.59 2.227 ;
     RECT  6.372 2.191 6.714 2.227 ;
     RECT  7.815 2.143 7.905 2.227 ;
     RECT  2.415 2.143 2.505 2.263 ;
     RECT  3.42 2.101 3.438 2.263 ;
     RECT  4.392 2.227 4.59 2.263 ;
     RECT  4.392 2.263 4.914 2.299 ;
     RECT  5.652 2.227 7.905 2.299 ;
     RECT  2.415 2.263 3.438 2.371 ;
     RECT  4.392 2.299 8.586 2.371 ;
     RECT  11.412 2.335 11.43 2.371 ;
     RECT  13.215 2.143 13.305 2.413 ;
     RECT  4.32 2.371 8.586 2.461 ;
     RECT  2.304 2.371 3.546 2.569 ;
     RECT  4.32 2.461 9.018 2.569 ;
     RECT  2.304 2.569 9.018 2.605 ;
     RECT  2.304 2.605 9.63 2.641 ;
     RECT  10.908 2.371 11.43 2.641 ;
     RECT  12.168 2.299 12.186 2.641 ;
     RECT  13.215 2.413 13.497 2.641 ;
     RECT  2.304 2.641 9.846 2.731 ;
     RECT  10.908 2.641 14.562 2.731 ;
     RECT  0.072 2.731 0.09 3.001 ;
     RECT  2.304 2.731 14.562 3.181 ;
     RECT  2.304 3.181 14.922 3.299 ;
     RECT  15.66 3.343 15.678 3.415 ;
     RECT  0.072 3.001 0.198 3.541 ;
     RECT  7.2 3.299 14.922 3.605 ;
     RECT  0.072 3.541 0.234 3.811 ;
     RECT  9.9 3.605 14.922 3.839 ;
     RECT  0.072 3.811 0.27 3.991 ;
     RECT  2.304 3.299 6.462 4.075 ;
     RECT  7.2 3.605 9.126 4.075 ;
     RECT  2.304 4.075 9.126 4.081 ;
     RECT  9.9 3.839 14.814 4.145 ;
     RECT  10.764 4.145 14.814 4.217 ;
     RECT  0.072 3.991 0.522 4.301 ;
     RECT  2.268 4.081 9.126 4.387 ;
     RECT  9.9 4.145 9.918 4.387 ;
     RECT  15.66 3.415 16.254 4.495 ;
     RECT  17.244 3.685 17.262 4.495 ;
     RECT  0.108 4.301 0.522 4.877 ;
     RECT  2.268 4.387 9.918 4.963 ;
     RECT  10.908 4.217 14.814 4.963 ;
     RECT  0.18 4.877 0.522 4.973 ;
     RECT  0.216 4.973 0.522 4.999 ;
     RECT  2.268 4.963 10.134 5.071 ;
     RECT  10.872 4.963 14.814 5.071 ;
     RECT  2.268 5.071 14.814 5.189 ;
     RECT  0.216 4.999 0.558 5.639 ;
     RECT  0.216 5.639 0.522 5.741 ;
     RECT  0.216 5.741 0.306 5.837 ;
     RECT  0.144 5.971 0.198 6.151 ;
     RECT  2.304 5.189 14.814 6.547 ;
     RECT  15.66 4.495 17.262 6.547 ;
     RECT  0.108 6.151 0.198 6.619 ;
     RECT  0.108 6.619 0.558 6.893 ;
     RECT  2.304 6.547 17.262 6.953 ;
     RECT  0.144 6.893 0.558 6.989 ;
     RECT  2.304 6.953 17.19 6.989 ;
     RECT  2.304 6.989 17.118 7.051 ;
     RECT  2.268 7.051 17.118 7.619 ;
     RECT  0.144 6.989 0.162 7.663 ;
     RECT  2.304 7.619 17.118 7.757 ;
     RECT  15.66 7.757 17.118 7.949 ;
     RECT  0.108 7.663 0.162 8.107 ;
     RECT  0.108 8.107 0.342 8.237 ;
     RECT  15.984 7.949 17.118 8.237 ;
     RECT  2.304 7.757 14.922 8.429 ;
     RECT  2.304 8.429 10.89 8.683 ;
     RECT  11.808 8.429 14.922 8.815 ;
     RECT  15.984 8.237 17.082 8.815 ;
     RECT  11.808 8.815 17.082 8.909 ;
     RECT  2.268 8.683 10.89 8.969 ;
     RECT  0.144 8.237 0.162 8.971 ;
     RECT  0.108 8.971 0.162 9.163 ;
     RECT  2.304 8.969 10.89 9.211 ;
     RECT  11.808 8.909 16.686 9.211 ;
     RECT  2.304 9.211 16.686 9.509 ;
     RECT  15.408 9.509 16.686 9.677 ;
     RECT  2.304 9.509 14.634 9.691 ;
     RECT  0.108 9.163 0.342 9.869 ;
     RECT  0.108 9.869 0.234 10.157 ;
     RECT  2.268 9.691 14.634 10.219 ;
     RECT  2.232 10.219 14.634 10.291 ;
     RECT  2.232 10.291 14.67 10.391 ;
     RECT  15.984 9.677 16.686 10.411 ;
     RECT  2.268 10.391 14.67 10.561 ;
     RECT  15.408 10.411 16.686 10.561 ;
     RECT  2.268 10.561 16.686 10.795 ;
     RECT  0.108 10.157 0.126 11.237 ;
     RECT  2.268 10.795 17.19 11.261 ;
     RECT  2.304 11.261 17.19 11.405 ;
     RECT  9.324 11.405 17.19 11.435 ;
     RECT  9.432 11.435 17.19 11.813 ;
     RECT  16.524 11.813 17.19 12.119 ;
     RECT  9.432 11.813 15.39 12.181 ;
     RECT  2.304 11.405 8.55 12.217 ;
     RECT  9.324 12.181 15.39 12.217 ;
     RECT  2.304 12.217 15.39 12.551 ;
     RECT  2.34 12.551 15.39 12.619 ;
     RECT  2.34 12.619 15.966 12.797 ;
     RECT  14.688 12.797 15.966 12.821 ;
     RECT  15.336 12.821 15.39 12.893 ;
     RECT  2.34 12.797 13.914 12.929 ;
     RECT  2.34 12.929 13.878 13.019 ;
     RECT  2.34 13.019 13.662 13.055 ;
     RECT  16.992 12.119 17.19 13.091 ;
     RECT  15.372 12.893 15.39 13.361 ;
     RECT  0.108 13.063 0.126 13.531 ;
     RECT  16.992 13.091 17.154 13.595 ;
     RECT  0.108 13.531 0.162 13.613 ;
     RECT  0.144 13.613 0.162 13.639 ;
     RECT  2.415 13.055 13.662 13.703 ;
     RECT  17.028 13.595 17.154 13.937 ;
     RECT  9.036 13.703 13.662 13.945 ;
     RECT  2.415 13.703 8.154 13.981 ;
     RECT  9.036 13.945 13.77 13.981 ;
     RECT  0.144 13.639 0.558 13.997 ;
     RECT  2.34 13.981 8.154 14.009 ;
     RECT  2.34 14.009 8.097 14.059 ;
     RECT  9.036 13.981 13.842 14.215 ;
     RECT  0.144 13.997 0.234 14.429 ;
     RECT  0.216 14.429 0.234 14.477 ;
     RECT  1.152 14.347 1.17 14.477 ;
     RECT  17.136 13.937 17.154 14.477 ;
     RECT  9.036 14.215 14.13 14.485 ;
     RECT  2.304 14.059 8.097 14.755 ;
     RECT  8.856 14.485 14.13 14.755 ;
     RECT  2.304 14.755 14.13 14.791 ;
     RECT  2.304 14.791 14.562 14.909 ;
     RECT  2.304 14.909 14.526 15.019 ;
     RECT  2.16 15.019 14.526 15.211 ;
     RECT  0.108 15.151 0.126 15.403 ;
     RECT  1.944 15.211 14.526 15.449 ;
     RECT  16.524 15.295 16.542 15.529 ;
     RECT  0.108 15.403 0.342 15.533 ;
     RECT  11.412 15.449 14.526 15.719 ;
     RECT  0.108 15.533 0.126 15.821 ;
     RECT  1.944 15.449 10.494 15.979 ;
     RECT  15.984 15.529 16.542 16.069 ;
     RECT  15.48 16.069 16.542 16.105 ;
     RECT  11.412 15.719 11.682 16.231 ;
     RECT  1.764 15.979 10.494 16.261 ;
     RECT  11.232 16.231 11.682 16.261 ;
     RECT  15.408 16.105 16.542 16.303 ;
     RECT  12.528 15.719 14.526 16.411 ;
     RECT  15.408 16.303 16.578 16.411 ;
     RECT  1.764 16.261 11.682 16.681 ;
     RECT  12.528 16.411 16.578 16.681 ;
     RECT  1.764 16.681 16.578 16.907 ;
     RECT  7.815 16.907 16.578 16.979 ;
     RECT  7.815 16.979 15.174 17.024 ;
     RECT  15.948 16.979 16.578 17.149 ;
     RECT  7.815 17.024 14.994 17.213 ;
     RECT  7.815 17.213 14.166 17.609 ;
     RECT  15.948 17.149 16.614 17.611 ;
     RECT  1.764 16.907 6.966 17.653 ;
     RECT  7.815 17.609 14.13 17.653 ;
     RECT  14.976 17.213 14.994 17.803 ;
     RECT  15.948 17.611 17.19 17.803 ;
     RECT  14.976 17.803 17.19 17.923 ;
     RECT  14.976 17.923 17.262 18.031 ;
     RECT  1.764 17.653 14.13 18.149 ;
     RECT  2.232 18.149 14.13 18.227 ;
     RECT  14.904 18.031 17.262 18.293 ;
     RECT  2.34 18.227 14.13 18.427 ;
     RECT  0.072 18.193 0.09 18.697 ;
     RECT  2.34 18.427 14.634 18.725 ;
     RECT  2.34 18.725 14.526 18.761 ;
     RECT  15.408 18.293 17.262 18.893 ;
     RECT  2.34 18.761 9.99 19.075 ;
     RECT  17.064 18.893 17.262 19.139 ;
     RECT  2.304 19.075 9.99 19.237 ;
     RECT  10.728 18.761 14.526 19.325 ;
     RECT  10.728 19.325 13.77 19.337 ;
     RECT  15.408 18.893 15.966 19.373 ;
     RECT  2.268 19.237 9.99 19.409 ;
     RECT  15.948 19.373 15.966 19.571 ;
     RECT  2.304 19.409 9.99 19.579 ;
     RECT  10.728 19.337 13.497 19.579 ;
     RECT  0.036 18.697 0.09 19.651 ;
     RECT  14.508 19.325 14.526 19.651 ;
     RECT  17.136 19.139 17.262 19.913 ;
     RECT  17.244 19.913 17.262 20.345 ;
     RECT  14.508 19.651 14.922 20.417 ;
     RECT  1.152 20.347 1.17 20.525 ;
     RECT  2.304 19.579 13.497 20.579 ;
     RECT  2.304 20.579 11.286 20.615 ;
     RECT  0.036 19.651 0.126 20.659 ;
     RECT  14.472 20.461 14.49 20.687 ;
     RECT  0.036 20.659 0.162 20.965 ;
     RECT  12.06 20.579 13.497 21.001 ;
     RECT  2.304 20.615 11.106 21.067 ;
     RECT  2.268 21.067 11.106 21.163 ;
     RECT  12.06 21.001 13.662 21.163 ;
     RECT  0.036 20.965 0.558 21.293 ;
     RECT  2.232 21.163 11.106 21.469 ;
     RECT  12.06 21.163 14.274 21.469 ;
     RECT  2.232 21.469 14.274 21.499 ;
     RECT  2.196 21.499 14.274 21.505 ;
     RECT  2.196 21.505 14.31 21.541 ;
     RECT  2.196 21.541 14.526 21.586 ;
     RECT  2.088 21.586 14.526 21.725 ;
     RECT  0.036 21.293 0.522 21.767 ;
     RECT  2.304 21.725 14.526 21.775 ;
     RECT  0.108 21.767 0.522 22.027 ;
     RECT  2.304 21.775 14.67 22.081 ;
     RECT  16.56 22.045 16.578 22.081 ;
     RECT  0.108 22.027 0.63 22.157 ;
     RECT  0.108 22.157 0.306 22.349 ;
     RECT  2.304 22.081 14.742 22.363 ;
     RECT  2.304 22.363 14.85 22.469 ;
     RECT  2.304 22.469 9.414 22.699 ;
     RECT  16.02 22.081 16.578 22.783 ;
     RECT  0.288 22.349 0.306 22.987 ;
     RECT  10.26 22.469 14.85 23.125 ;
     RECT  15.984 22.783 16.578 23.125 ;
     RECT  0.288 22.987 0.378 23.131 ;
     RECT  1.98 22.699 9.414 23.251 ;
     RECT  10.26 23.125 16.578 23.251 ;
     RECT  0.144 23.131 0.378 23.309 ;
     RECT  0.288 23.309 0.306 23.357 ;
     RECT  1.98 23.251 16.578 23.855 ;
     RECT  15.372 23.855 16.578 23.863 ;
     RECT  15.372 23.863 17.19 24.173 ;
     RECT  15.372 24.173 15.39 24.431 ;
     RECT  1.98 23.855 14.634 24.467 ;
     RECT  2.196 24.467 14.634 24.601 ;
     RECT  2.196 24.601 14.922 24.701 ;
     RECT  16.524 24.173 17.19 24.943 ;
     RECT  15.948 24.943 17.19 25.043 ;
     RECT  2.304 24.701 14.922 25.325 ;
     RECT  15.948 25.043 16.002 25.387 ;
     RECT  17.136 25.043 17.19 25.781 ;
     RECT  17.136 25.781 17.154 25.853 ;
     RECT  15.372 25.387 16.002 25.889 ;
     RECT  2.304 25.325 14.382 25.901 ;
     RECT  15.912 25.889 16.002 25.901 ;
     RECT  2.304 25.901 11.97 26.051 ;
     RECT  15.912 25.901 15.966 26.123 ;
     RECT  12.708 25.901 14.382 26.131 ;
     RECT  2.304 26.051 11.646 26.249 ;
     RECT  7.056 26.249 11.646 26.291 ;
     RECT  12.708 26.131 14.526 26.321 ;
     RECT  15.948 26.123 15.966 26.321 ;
     RECT  7.056 26.291 11.43 26.357 ;
     RECT  2.304 26.249 5.994 26.429 ;
     RECT  2.304 26.429 5.742 26.491 ;
     RECT  12.708 26.321 13.806 26.519 ;
     RECT  12.708 26.519 13.77 26.629 ;
     RECT  7.092 26.357 11.43 26.699 ;
     RECT  14.904 26.401 14.922 26.789 ;
     RECT  7.092 26.699 9.018 27.175 ;
     RECT  10.008 26.699 11.43 27.175 ;
     RECT  2.232 26.491 5.742 27.211 ;
     RECT  6.732 27.175 9.018 27.211 ;
     RECT  10.008 27.175 11.646 27.211 ;
     RECT  12.564 26.629 13.77 27.211 ;
     RECT  10.008 27.211 13.77 27.337 ;
     RECT  10.008 27.337 13.986 27.547 ;
     RECT  10.008 27.547 14.058 27.571 ;
     RECT  14.832 27.409 14.85 27.571 ;
     RECT  10.008 27.571 14.85 27.643 ;
     RECT  2.232 27.211 9.018 27.751 ;
     RECT  9.972 27.643 14.85 27.751 ;
     RECT  2.232 27.751 14.85 27.917 ;
     RECT  1.152 27.571 1.17 28.111 ;
     RECT  2.232 27.917 11.61 28.175 ;
     RECT  12.348 27.917 14.85 28.255 ;
     RECT  16.272 28.183 16.29 28.291 ;
     RECT  12.348 28.255 15.102 28.319 ;
     RECT  0.144 28.219 0.162 28.381 ;
     RECT  2.232 28.175 11.466 28.409 ;
     RECT  9.756 28.409 11.466 28.445 ;
     RECT  9.756 28.445 11.034 28.481 ;
     RECT  16.272 28.291 16.362 28.723 ;
     RECT  13.104 28.319 15.102 28.795 ;
     RECT  16.236 28.723 16.362 28.795 ;
     RECT  0.144 28.381 0.234 29.029 ;
     RECT  1.152 28.111 1.206 29.029 ;
     RECT  12.348 28.319 12.366 29.029 ;
     RECT  2.232 28.409 9.018 29.191 ;
     RECT  9.756 28.481 10.926 29.191 ;
     RECT  11.988 29.029 12.366 29.191 ;
     RECT  13.104 28.795 16.362 29.191 ;
     RECT  2.232 29.191 10.926 29.227 ;
     RECT  0.144 29.029 1.206 29.461 ;
     RECT  2.232 29.227 10.998 29.461 ;
     RECT  2.232 29.461 11.07 29.767 ;
     RECT  0.108 29.461 1.206 29.837 ;
     RECT  2.232 29.767 11.106 29.837 ;
     RECT  10.188 29.837 11.106 29.911 ;
     RECT  11.988 29.191 16.362 29.911 ;
     RECT  0.144 29.837 1.206 30.029 ;
     RECT  17.208 29.299 17.226 30.109 ;
     RECT  0.18 30.029 1.206 30.413 ;
     RECT  10.188 29.911 16.362 30.451 ;
     RECT  0.18 30.413 0.558 30.509 ;
     RECT  2.232 29.837 9.126 30.649 ;
     RECT  10.188 30.451 16.434 30.649 ;
     RECT  0.18 30.509 0.342 30.811 ;
     RECT  2.232 30.649 16.434 30.848 ;
     RECT  2.304 30.848 16.434 31.423 ;
     RECT  17.208 30.109 17.262 31.423 ;
     RECT  0.144 30.811 0.342 31.459 ;
     RECT  2.304 31.423 17.262 31.801 ;
     RECT  2.232 31.801 17.262 31.853 ;
     RECT  0.144 31.459 0.558 31.891 ;
     RECT  0.108 31.891 0.558 32.621 ;
     RECT  0.108 32.621 0.342 32.909 ;
     RECT  2.304 31.853 17.262 33.005 ;
     RECT  0.144 32.909 0.342 33.101 ;
     RECT  2.304 33.005 14.922 33.269 ;
     RECT  0.216 33.101 0.342 33.293 ;
     RECT  15.696 33.005 17.262 33.377 ;
     RECT  15.696 33.377 17.19 33.389 ;
     RECT  0.216 33.293 0.306 33.629 ;
     RECT  0.288 33.629 0.306 33.677 ;
     RECT  2.304 33.269 12.258 33.835 ;
     RECT  15.696 33.389 16.758 34.061 ;
     RECT  2.268 33.835 12.258 34.087 ;
     RECT  13.068 33.269 14.922 34.087 ;
     RECT  0.324 34.027 0.342 34.459 ;
     RECT  2.268 34.087 14.922 34.501 ;
     RECT  0.216 34.459 0.342 34.507 ;
     RECT  15.84 34.061 16.758 34.529 ;
     RECT  0.216 34.507 0.378 34.699 ;
     RECT  0.108 34.699 0.378 34.733 ;
     RECT  15.84 34.529 16.686 34.934 ;
     RECT  2.268 34.501 14.994 35.179 ;
     RECT  2.232 35.179 14.994 35.203 ;
     RECT  15.84 34.934 16.65 35.203 ;
     RECT  2.232 35.203 16.65 35.275 ;
     RECT  1.728 35.275 16.65 35.597 ;
     RECT  0.108 34.733 0.126 35.659 ;
     RECT  15.408 35.597 16.65 35.693 ;
     RECT  0.108 35.659 0.342 35.789 ;
     RECT  0.108 35.789 0.126 35.885 ;
     RECT  1.728 35.597 14.274 35.969 ;
     RECT  15.408 35.693 15.426 36.173 ;
     RECT  1.728 35.969 6.966 36.347 ;
     RECT  7.776 35.969 14.274 36.391 ;
     RECT  16.524 35.693 16.65 36.523 ;
     RECT  16.488 36.523 16.65 36.589 ;
     RECT  7.776 36.391 14.994 36.689 ;
     RECT  15.984 36.589 16.65 36.811 ;
     RECT  15.984 36.811 17.19 36.907 ;
     RECT  2.232 36.347 6.966 36.931 ;
     RECT  7.776 36.689 14.634 36.931 ;
     RECT  2.232 36.931 14.634 37.049 ;
     RECT  2.232 37.049 14.31 37.625 ;
     RECT  15.372 36.907 17.19 37.867 ;
     RECT  2.232 37.625 9.486 37.931 ;
     RECT  15.336 37.867 17.19 37.997 ;
     RECT  2.304 37.931 9.486 38.165 ;
     RECT  15.336 37.997 15.966 38.201 ;
     RECT  17.172 37.997 17.19 38.273 ;
     RECT  2.376 38.165 9.486 38.371 ;
     RECT  10.224 37.625 14.31 38.371 ;
     RECT  2.376 38.371 14.31 38.399 ;
     RECT  2.376 38.399 12.402 38.435 ;
     RECT  15.336 38.201 15.39 38.471 ;
     RECT  15.372 38.471 15.39 38.543 ;
     RECT  2.376 38.435 12.294 38.579 ;
     RECT  13.14 38.399 14.31 38.579 ;
     RECT  11.196 38.579 12.294 38.669 ;
     RECT  13.14 38.579 14.166 38.669 ;
     RECT  13.176 38.669 14.166 38.813 ;
     RECT  2.376 38.579 10.458 39.019 ;
     RECT  11.196 38.669 11.97 39.119 ;
     RECT  2.304 39.019 10.458 39.361 ;
     RECT  11.196 39.119 11.43 39.361 ;
     RECT  13.176 38.813 14.094 39.451 ;
     RECT  0.108 39.289 0.126 39.523 ;
     RECT  0.108 39.523 0.198 39.721 ;
     RECT  12.312 39.451 14.094 39.757 ;
     RECT  2.304 39.361 11.43 39.829 ;
     RECT  12.312 39.757 14.814 39.857 ;
     RECT  2.268 39.829 11.43 39.865 ;
     RECT  12.312 39.857 14.742 39.865 ;
     RECT  2.268 39.865 14.742 39.929 ;
     RECT  0.108 39.721 0.558 40.493 ;
     RECT  2.304 39.929 14.742 40.711 ;
     RECT  0.108 40.493 0.126 41.069 ;
     RECT  2.268 40.711 14.742 41.135 ;
     RECT  2.268 41.135 9.99 41.165 ;
     RECT  11.016 41.135 14.742 41.179 ;
     RECT  11.016 41.179 14.778 41.207 ;
     RECT  15.984 39.757 16.002 41.215 ;
     RECT  11.052 41.207 14.778 41.243 ;
     RECT  0.144 41.371 0.162 41.549 ;
     RECT  15.984 41.215 16.038 41.755 ;
     RECT  15.984 41.755 16.506 41.953 ;
     RECT  15.516 41.953 16.506 41.989 ;
     RECT  2.304 41.165 9.99 41.995 ;
     RECT  11.088 41.243 14.778 42.025 ;
     RECT  15.516 41.989 16.542 42.025 ;
     RECT  1.764 41.995 9.99 42.181 ;
     RECT  11.088 42.025 16.542 42.181 ;
     RECT  0.54 42.061 0.558 42.221 ;
     RECT  1.764 42.181 16.542 42.283 ;
     RECT  1.728 42.283 16.542 42.421 ;
     RECT  1.728 42.421 16.578 42.755 ;
     RECT  14.688 42.755 16.578 42.893 ;
     RECT  15.444 42.893 16.578 43.231 ;
     RECT  1.728 42.755 13.77 43.501 ;
     RECT  1.728 43.501 13.842 43.579 ;
     RECT  14.688 42.893 14.706 43.579 ;
     RECT  1.728 43.579 14.706 43.645 ;
     RECT  15.444 43.231 17.19 43.645 ;
     RECT  1.728 43.645 17.19 43.799 ;
     RECT  2.304 43.799 17.19 43.871 ;
     RECT  2.304 43.871 15.714 43.949 ;
     RECT  16.452 43.871 17.19 44.045 ;
     RECT  2.304 43.949 15.426 44.621 ;
     RECT  16.452 44.045 16.542 44.68 ;
     RECT  15.948 44.68 16.542 44.717 ;
     RECT  15.984 44.717 16.542 44.875 ;
     RECT  2.304 44.621 14.886 44.879 ;
     RECT  2.304 44.879 14.094 44.915 ;
     RECT  15.984 44.875 17.154 45.023 ;
     RECT  15.984 45.023 16.002 45.101 ;
     RECT  7.02 44.915 14.094 45.149 ;
     RECT  14.868 44.879 14.886 45.149 ;
     RECT  17.136 45.023 17.154 45.163 ;
     RECT  17.136 45.163 17.19 45.293 ;
     RECT  7.02 45.149 11.538 45.329 ;
     RECT  7.02 45.329 9.018 45.419 ;
     RECT  17.172 45.293 17.19 45.419 ;
     RECT  12.312 45.149 14.094 45.491 ;
     RECT  2.376 44.915 6.282 45.661 ;
     RECT  7.02 45.419 7.038 45.661 ;
     RECT  12.78 45.491 14.094 45.661 ;
     RECT  0.144 45.391 0.162 45.739 ;
     RECT  2.376 45.661 7.038 45.805 ;
     RECT  2.34 45.805 7.038 45.832 ;
     RECT  0.108 45.739 0.162 45.931 ;
     RECT  0.108 45.931 0.234 45.965 ;
     RECT  0.144 45.965 0.234 46.003 ;
     RECT  7.776 45.419 9.018 46.111 ;
     RECT  7.776 46.111 9.126 46.171 ;
     RECT  9.864 45.329 11.538 46.171 ;
     RECT  2.304 45.832 7.038 46.237 ;
     RECT  7.776 46.171 11.538 46.237 ;
     RECT  12.78 45.661 14.202 46.237 ;
     RECT  2.304 46.237 11.538 46.345 ;
     RECT  12.42 46.237 14.202 46.345 ;
     RECT  2.304 46.345 14.202 46.381 ;
     RECT  2.304 46.381 14.454 46.499 ;
     RECT  0.144 46.003 0.558 46.541 ;
     RECT  0.18 46.541 0.558 46.829 ;
     RECT  17.244 46.075 17.262 46.849 ;
     RECT  0.216 46.829 0.558 46.925 ;
     RECT  2.304 46.499 14.238 46.987 ;
     RECT  2.268 46.987 14.238 47.353 ;
     RECT  0.54 46.925 0.558 47.405 ;
     RECT  16.524 46.849 17.262 47.929 ;
     RECT  2.268 47.353 14.922 48.199 ;
     RECT  15.984 47.929 17.262 48.199 ;
     RECT  2.268 48.199 17.262 48.269 ;
     RECT  0.324 48.331 0.342 48.461 ;
     RECT  0.144 48.523 0.162 48.701 ;
     RECT  2.268 48.269 17.19 49.199 ;
     RECT  14.976 49.199 17.19 49.325 ;
     RECT  2.304 49.199 14.022 49.343 ;
     RECT  14.976 49.325 16.722 49.469 ;
     RECT  12.204 49.343 14.022 49.517 ;
     RECT  12.204 49.517 13.95 49.919 ;
     RECT  15.372 49.469 16.722 50.093 ;
     RECT  2.304 49.343 11.466 50.161 ;
     RECT  12.204 49.919 13.734 50.161 ;
     RECT  2.304 50.161 13.734 50.387 ;
     RECT  15.372 50.093 16.002 50.431 ;
     RECT  8.82 50.387 13.734 50.717 ;
     RECT  8.892 50.717 13.734 50.729 ;
     RECT  8.964 50.729 13.734 50.791 ;
     RECT  14.472 50.431 16.002 50.791 ;
     RECT  1.152 48.715 1.17 50.819 ;
     RECT  17.172 50.731 17.19 50.827 ;
     RECT  8.964 50.791 16.002 50.899 ;
     RECT  17.136 50.827 17.19 50.899 ;
     RECT  8.964 50.899 17.19 50.963 ;
     RECT  2.304 50.387 8.097 50.971 ;
     RECT  8.964 50.963 17.154 50.999 ;
     RECT  8.964 50.999 16.542 51.245 ;
     RECT  8.964 51.245 15.966 51.341 ;
     RECT  8.964 51.341 14.85 51.359 ;
     RECT  11.34 51.359 13.734 51.431 ;
     RECT  15.948 51.341 15.966 51.431 ;
     RECT  11.34 51.431 11.538 51.437 ;
     RECT  14.508 51.359 14.85 51.437 ;
     RECT  2.232 50.971 8.097 51.511 ;
     RECT  8.964 51.359 10.458 51.511 ;
     RECT  2.232 51.511 10.458 51.539 ;
     RECT  2.232 51.539 6.354 51.629 ;
     RECT  14.508 51.437 14.526 51.773 ;
     RECT  12.636 51.431 13.734 52.249 ;
     RECT  7.524 51.539 10.458 52.321 ;
     RECT  11.34 51.437 11.358 52.321 ;
     RECT  2.232 51.629 5.85 52.408 ;
     RECT  6.624 52.285 6.642 52.408 ;
     RECT  2.232 52.408 6.642 52.411 ;
     RECT  7.524 52.321 11.358 52.411 ;
     RECT  12.6 52.249 13.734 52.411 ;
     RECT  2.232 52.411 13.95 52.591 ;
     RECT  14.76 52.447 14.778 52.861 ;
     RECT  16.632 52.789 16.65 52.861 ;
     RECT  14.76 52.861 14.886 52.981 ;
     RECT  16.632 52.861 16.686 52.987 ;
     RECT  2.232 52.591 13.986 53.095 ;
     RECT  14.724 52.981 14.886 53.095 ;
     RECT  2.232 53.095 14.886 53.131 ;
     RECT  2.232 53.131 15.426 53.249 ;
     RECT  12.6 53.249 15.426 53.329 ;
     RECT  16.524 52.987 16.686 53.329 ;
     RECT  2.232 53.249 11.826 53.519 ;
     RECT  2.232 53.519 11.502 54.409 ;
     RECT  0.18 53.761 0.198 54.481 ;
     RECT  2.232 54.409 11.754 54.481 ;
     RECT  12.6 53.329 16.686 54.481 ;
     RECT  0.18 54.481 0.234 54.571 ;
     RECT  0.144 54.571 0.234 54.679 ;
     RECT  2.232 54.481 16.686 54.779 ;
     RECT  2.268 54.779 16.686 54.913 ;
     RECT  0.036 54.679 0.234 55.111 ;
     RECT  1.152 54.913 1.17 55.111 ;
     RECT  0.036 55.111 1.242 55.247 ;
     RECT  0.036 55.247 0.558 55.661 ;
     RECT  2.268 54.913 16.722 55.757 ;
     RECT  15.984 55.757 16.722 56.059 ;
     RECT  15.984 56.059 17.118 56.101 ;
     RECT  15.984 56.101 17.19 56.141 ;
     RECT  2.268 55.757 14.922 56.219 ;
     RECT  2.268 56.219 14.634 56.371 ;
     RECT  0.036 55.661 0.342 56.399 ;
     RECT  15.984 56.141 16.722 56.429 ;
     RECT  0.108 56.399 0.342 56.461 ;
     RECT  2.232 56.371 14.634 56.597 ;
     RECT  2.232 56.597 14.418 56.669 ;
     RECT  16.524 56.429 16.722 56.717 ;
     RECT  2.232 56.669 14.346 56.759 ;
     RECT  15.408 56.605 15.426 56.813 ;
     RECT  2.232 56.759 14.238 56.831 ;
     RECT  16.56 56.717 16.722 56.875 ;
     RECT  2.232 56.831 9.27 56.903 ;
     RECT  10.152 56.831 14.238 57.029 ;
     RECT  15.372 56.971 15.39 57.067 ;
     RECT  15.336 57.067 15.39 57.173 ;
     RECT  2.268 56.903 9.27 57.341 ;
     RECT  0.108 56.461 0.558 57.343 ;
     RECT  15.372 57.173 15.39 57.407 ;
     RECT  16.56 56.875 17.19 57.443 ;
     RECT  16.524 57.445 16.542 57.485 ;
     RECT  2.268 57.341 9.126 57.773 ;
     RECT  10.44 57.029 13.59 57.955 ;
     RECT  10.224 57.955 13.59 58.081 ;
     RECT  9.9 58.081 13.59 58.225 ;
     RECT  9.9 58.225 13.914 58.261 ;
     RECT  2.304 57.773 9.126 58.351 ;
     RECT  9.9 58.261 14.418 58.351 ;
     RECT  2.304 58.351 14.526 58.495 ;
     RECT  2.304 58.495 14.598 58.523 ;
     RECT  0.036 57.343 0.558 59.021 ;
     RECT  2.304 58.523 12.33 59.161 ;
     RECT  2.196 59.161 12.33 59.213 ;
     RECT  16.056 58.891 16.074 59.233 ;
     RECT  17.244 58.495 17.262 59.233 ;
     RECT  13.104 58.523 14.598 59.341 ;
     RECT  2.376 59.213 12.33 59.431 ;
     RECT  13.068 59.341 14.598 59.431 ;
     RECT  0.036 59.021 0.27 59.495 ;
     RECT  2.376 59.431 14.598 59.729 ;
     RECT  0.108 59.495 0.27 59.885 ;
     RECT  16.056 59.233 17.262 59.971 ;
     RECT  0.108 59.885 0.198 59.981 ;
     RECT  2.376 59.729 10.854 60.115 ;
     RECT  11.628 59.729 14.598 60.151 ;
     RECT  15.444 59.971 17.262 60.151 ;
     RECT  11.628 60.151 17.262 60.341 ;
     RECT  2.304 60.115 10.854 60.523 ;
     RECT  2.232 60.523 10.854 60.575 ;
     RECT  2.304 60.575 10.854 60.691 ;
     RECT  11.628 60.341 14.598 60.691 ;
     RECT  0.18 59.981 0.198 60.781 ;
     RECT  0.108 60.781 0.198 60.809 ;
     RECT  2.304 60.691 14.598 61.087 ;
     RECT  15.444 60.341 17.262 61.087 ;
     RECT  2.304 61.087 17.262 61.579 ;
     RECT  0.108 60.809 0.162 61.663 ;
     RECT  0.108 61.663 0.198 61.709 ;
     RECT  2.268 61.579 17.262 61.799 ;
     RECT  2.268 61.799 17.19 61.808 ;
     RECT  2.268 61.808 17.154 62.041 ;
     RECT  2.232 62.041 17.154 62.093 ;
     RECT  0.144 61.709 0.198 62.131 ;
     RECT  0.144 62.131 0.234 62.668 ;
     RECT  2.304 62.093 17.154 62.699 ;
     RECT  0.108 62.668 0.234 62.765 ;
     RECT  0.18 62.765 0.234 62.923 ;
     RECT  0.18 62.923 0.342 63.053 ;
     RECT  10.26 62.699 17.154 63.149 ;
     RECT  2.304 62.699 9.486 63.403 ;
     RECT  10.26 63.149 16.542 63.509 ;
     RECT  14.796 63.509 16.542 63.629 ;
     RECT  14.796 63.629 14.85 63.725 ;
     RECT  2.232 63.403 9.486 63.787 ;
     RECT  10.26 63.509 14.022 63.787 ;
     RECT  14.796 63.725 14.814 63.851 ;
     RECT  0.18 63.053 0.27 64.075 ;
     RECT  15.984 63.629 16.542 64.171 ;
     RECT  2.232 63.787 14.022 64.291 ;
     RECT  2.232 64.291 14.706 64.315 ;
     RECT  0.18 64.075 0.342 64.399 ;
     RECT  15.984 64.171 17.19 64.555 ;
     RECT  15.948 64.555 17.19 64.651 ;
     RECT  1.728 64.315 14.706 64.741 ;
     RECT  0.108 64.399 0.342 64.843 ;
     RECT  15.912 64.651 17.19 64.895 ;
     RECT  15.912 64.895 15.966 65.201 ;
     RECT  15.912 65.201 15.93 65.227 ;
     RECT  1.728 64.741 14.814 65.237 ;
     RECT  1.728 65.237 9.306 65.273 ;
     RECT  1.764 65.273 9.306 65.399 ;
     RECT  10.116 65.237 14.814 65.515 ;
     RECT  15.876 65.227 15.93 65.515 ;
     RECT  1.764 65.399 9.054 65.579 ;
     RECT  17.064 64.895 17.19 65.707 ;
     RECT  2.196 65.579 9.054 65.939 ;
     RECT  17.028 65.707 17.19 65.995 ;
     RECT  10.116 65.515 15.93 66.091 ;
     RECT  16.992 65.995 17.19 66.091 ;
     RECT  9.828 66.091 17.19 66.281 ;
     RECT  2.268 65.939 9.054 66.325 ;
     RECT  9.828 66.281 14.274 66.325 ;
     RECT  15.12 66.281 17.19 66.821 ;
     RECT  2.268 66.325 14.274 67.163 ;
     RECT  15.12 66.821 15.246 67.163 ;
     RECT  9.612 67.163 14.274 67.171 ;
     RECT  0.108 64.843 0.558 67.361 ;
     RECT  9.612 67.171 14.382 67.369 ;
     RECT  15.12 67.163 15.138 67.369 ;
     RECT  0.54 67.361 0.558 67.469 ;
     RECT  2.268 67.163 8.802 67.981 ;
     RECT  9.612 67.369 15.138 67.981 ;
     RECT  2.268 67.981 15.138 68.099 ;
     RECT  15.12 68.099 15.138 68.171 ;
     RECT  16.236 66.821 17.19 68.405 ;
     RECT  16.236 68.405 17.118 68.675 ;
     RECT  2.268 68.099 13.986 68.909 ;
     RECT  2.376 68.909 13.986 68.917 ;
     RECT  2.376 68.917 14.166 69.053 ;
     RECT  2.376 69.053 13.77 69.215 ;
     RECT  16.812 68.675 17.118 69.287 ;
     RECT  17.064 69.287 17.118 69.323 ;
     RECT  17.1 69.323 17.118 69.485 ;
     RECT  2.376 69.215 13.497 69.629 ;
     RECT  2.376 69.629 11.754 69.719 ;
     RECT  2.376 69.719 11.718 69.871 ;
     RECT  2.34 69.871 11.718 69.989 ;
     RECT  12.492 69.629 13.497 69.989 ;
     RECT  2.34 69.989 11.43 70.301 ;
     RECT  2.34 70.301 9.99 70.303 ;
     RECT  13.215 69.989 13.497 70.411 ;
     RECT  0.54 69.799 0.558 70.501 ;
     RECT  10.836 70.301 11.43 70.529 ;
     RECT  14.364 70.411 14.382 70.529 ;
     RECT  13.215 70.411 13.626 70.645 ;
     RECT  11.16 70.529 11.43 70.807 ;
     RECT  12.456 70.747 12.474 70.807 ;
     RECT  13.215 70.645 14.31 70.807 ;
     RECT  0.18 70.501 0.558 71.275 ;
     RECT  2.304 70.303 9.99 71.275 ;
     RECT  2.304 71.275 10.278 71.311 ;
     RECT  11.16 70.807 14.31 71.311 ;
     RECT  2.304 71.311 14.31 71.491 ;
     RECT  0.144 71.275 0.558 71.501 ;
     RECT  0.144 71.501 0.342 71.581 ;
     RECT  16.524 71.419 16.542 71.689 ;
     RECT  16.524 71.689 16.578 71.725 ;
     RECT  16.524 71.725 16.65 71.959 ;
     RECT  0.108 71.581 0.342 71.981 ;
     RECT  0.18 71.981 0.198 72.077 ;
     RECT  2.304 71.491 14.706 72.157 ;
     RECT  16.524 71.959 16.722 72.265 ;
     RECT  2.304 72.157 14.886 72.293 ;
     RECT  2.304 72.293 14.814 72.328 ;
     RECT  2.268 72.328 14.814 72.329 ;
     RECT  16.524 72.265 16.758 72.427 ;
     RECT  7.272 72.329 14.814 72.833 ;
     RECT  0.54 72.733 0.558 72.931 ;
     RECT  7.272 72.833 14.742 73.229 ;
     RECT  7.776 73.229 14.742 73.265 ;
     RECT  0.108 72.931 0.558 73.291 ;
     RECT  2.268 72.329 6.282 73.309 ;
     RECT  16.524 72.427 16.794 73.309 ;
     RECT  2.268 73.309 6.354 73.381 ;
     RECT  0.108 73.291 0.666 73.421 ;
     RECT  2.268 73.381 6.426 73.435 ;
     RECT  15.984 73.309 16.794 73.471 ;
     RECT  15.984 73.471 16.83 73.507 ;
     RECT  2.268 73.435 6.498 73.517 ;
     RECT  2.304 73.517 6.498 73.531 ;
     RECT  12.564 73.265 14.742 73.571 ;
     RECT  0.108 73.421 0.522 73.613 ;
     RECT  12.564 73.571 13.986 73.643 ;
     RECT  0.108 73.613 0.342 73.709 ;
     RECT  14.724 73.571 14.742 73.997 ;
     RECT  2.304 73.531 6.894 74.011 ;
     RECT  7.776 73.265 11.826 74.011 ;
     RECT  0.324 73.709 0.342 74.093 ;
     RECT  2.304 74.011 11.826 74.119 ;
     RECT  12.564 73.643 13.914 74.119 ;
     RECT  2.304 74.119 13.914 74.309 ;
     RECT  15.984 73.507 16.902 74.534 ;
     RECT  2.34 74.309 13.914 74.551 ;
     RECT  15.984 74.534 16.866 74.731 ;
     RECT  15.948 74.731 16.866 74.827 ;
     RECT  15.912 74.827 16.866 74.92 ;
     RECT  2.34 74.551 14.454 74.929 ;
     RECT  15.876 74.92 16.866 75.271 ;
     RECT  2.34 74.929 14.706 75.397 ;
     RECT  15.876 75.271 17.118 75.397 ;
     RECT  2.34 75.397 17.118 75.541 ;
     RECT  2.304 75.541 17.118 75.821 ;
     RECT  10.26 75.821 17.118 75.929 ;
     RECT  14.652 75.929 17.118 76.073 ;
     RECT  15.408 76.073 17.118 76.301 ;
     RECT  15.408 76.301 16.002 76.493 ;
     RECT  10.26 75.929 13.914 76.549 ;
     RECT  16.992 76.301 17.118 76.589 ;
     RECT  0.108 75.901 0.126 76.621 ;
     RECT  15.984 76.493 16.002 76.685 ;
     RECT  10.116 76.549 13.914 76.783 ;
     RECT  2.304 75.821 9.27 76.855 ;
     RECT  10.116 76.783 14.058 76.855 ;
     RECT  2.304 76.855 14.058 76.919 ;
     RECT  9.18 76.919 14.058 77.089 ;
     RECT  9.18 77.089 14.094 77.161 ;
     RECT  2.304 76.919 8.097 77.251 ;
     RECT  15.48 77.359 15.498 77.395 ;
     RECT  0.108 76.621 0.162 77.431 ;
     RECT  15.408 77.395 15.498 77.431 ;
     RECT  15.408 77.431 15.534 77.549 ;
     RECT  15.48 77.549 15.534 77.645 ;
     RECT  2.268 77.251 8.097 77.701 ;
     RECT  9.18 77.161 14.382 77.701 ;
     RECT  15.516 77.645 15.534 77.741 ;
     RECT  16.56 77.629 16.578 77.863 ;
     RECT  16.524 77.863 16.578 77.899 ;
     RECT  2.268 77.701 14.454 77.935 ;
     RECT  0.108 77.431 0.234 77.971 ;
     RECT  15.948 77.899 16.614 77.995 ;
     RECT  0.108 77.971 0.27 78.061 ;
     RECT  2.268 77.935 14.634 78.089 ;
     RECT  2.268 78.089 14.202 78.125 ;
     RECT  15.948 77.995 17.19 78.469 ;
     RECT  1.152 76.351 1.17 78.605 ;
     RECT  0.108 78.061 0.306 78.667 ;
     RECT  2.268 78.125 8.19 78.859 ;
     RECT  8.964 78.125 14.202 78.859 ;
     RECT  0.108 78.667 0.342 78.871 ;
     RECT  2.268 78.859 14.202 78.893 ;
     RECT  15.408 78.469 17.19 78.955 ;
     RECT  2.304 78.893 14.202 78.979 ;
     RECT  0.108 78.871 0.378 79.015 ;
     RECT  15.372 78.955 17.19 79.043 ;
     RECT  2.304 78.979 14.454 79.169 ;
     RECT  15.948 79.043 17.19 79.781 ;
     RECT  14.688 79.483 14.814 80.023 ;
     RECT  2.304 79.169 13.842 80.095 ;
     RECT  14.688 80.023 15.426 80.095 ;
     RECT  16.488 79.781 17.19 80.159 ;
     RECT  2.304 80.095 15.426 80.429 ;
     RECT  2.304 80.429 15.39 80.519 ;
     RECT  0.108 79.015 0.558 80.717 ;
     RECT  10.728 80.519 15.39 80.897 ;
     RECT  16.488 80.159 17.154 80.897 ;
     RECT  16.956 80.897 17.154 81.131 ;
     RECT  16.956 81.131 17.118 81.203 ;
     RECT  10.728 80.897 14.49 81.401 ;
     RECT  2.304 80.519 9.99 81.607 ;
     RECT  10.728 81.401 14.382 81.607 ;
     RECT  0.108 80.717 0.198 81.643 ;
     RECT  15.372 80.897 15.39 81.671 ;
     RECT  17.028 81.203 17.118 81.743 ;
     RECT  0.108 81.643 0.342 81.949 ;
     RECT  2.304 81.607 14.382 81.977 ;
     RECT  17.028 81.743 17.046 82.013 ;
     RECT  0.108 81.949 0.558 82.061 ;
     RECT  0.18 82.061 0.558 82.157 ;
     RECT  0.18 82.157 0.198 82.541 ;
     RECT  2.304 81.977 13.878 82.589 ;
     RECT  10.548 82.589 13.878 83.101 ;
     RECT  2.304 82.589 9.81 83.179 ;
     RECT  10.548 83.101 14.31 83.221 ;
     RECT  15.66 82.525 15.678 83.227 ;
     RECT  2.268 83.179 9.81 83.335 ;
     RECT  10.548 83.221 14.382 83.335 ;
     RECT  0.144 83.323 0.162 83.501 ;
     RECT  2.268 83.335 14.382 83.533 ;
     RECT  2.268 83.533 14.526 83.659 ;
     RECT  2.232 83.659 14.526 83.911 ;
     RECT  2.232 83.911 14.85 84.029 ;
     RECT  15.66 83.227 16.254 84.073 ;
     RECT  17.208 83.767 17.226 84.073 ;
     RECT  2.232 84.029 14.634 84.136 ;
     RECT  0.324 83.947 0.342 84.475 ;
     RECT  2.196 84.136 14.634 84.715 ;
     RECT  0.144 84.475 0.342 85.099 ;
     RECT  1.728 84.715 14.634 85.189 ;
     RECT  1.728 85.189 14.706 85.261 ;
     RECT  0.144 85.099 0.594 85.325 ;
     RECT  0.576 85.325 0.594 85.387 ;
     RECT  1.728 85.261 14.778 85.387 ;
     RECT  0.576 85.387 14.778 85.693 ;
     RECT  0.576 85.693 14.922 86.155 ;
     RECT  0.144 86.155 14.922 86.261 ;
     RECT  13.032 86.261 14.922 86.333 ;
     RECT  0.144 86.261 12.294 86.459 ;
     RECT  15.66 84.073 17.226 86.669 ;
     RECT  0.144 86.459 11.862 86.728 ;
     RECT  0.108 86.728 11.862 86.729 ;
     RECT  0.108 86.729 0.342 86.765 ;
     RECT  15.66 86.669 17.154 86.765 ;
     RECT  16.236 86.765 17.154 86.861 ;
     RECT  13.068 86.333 14.922 86.881 ;
     RECT  0.108 86.765 0.234 86.909 ;
     RECT  16.236 86.861 17.082 86.957 ;
     RECT  0.108 86.909 0.162 87.043 ;
     RECT  0.072 87.043 0.162 87.071 ;
     RECT  1.116 86.729 11.862 87.071 ;
     RECT  13.068 86.881 15.426 87.151 ;
     RECT  1.224 87.071 11.862 87.211 ;
     RECT  12.6 87.151 15.426 87.211 ;
     RECT  0.072 87.071 0.126 87.739 ;
     RECT  0.036 87.739 0.126 87.773 ;
     RECT  16.272 86.957 17.082 87.889 ;
     RECT  1.224 87.211 15.426 88.195 ;
     RECT  16.272 87.889 17.19 88.301 ;
     RECT  1.224 88.195 15.462 88.456 ;
     RECT  16.272 88.301 16.614 88.456 ;
     RECT  1.224 88.456 16.614 88.781 ;
     RECT  1.224 88.781 14.958 88.889 ;
     RECT  1.908 88.889 14.958 89.501 ;
     RECT  14.832 89.501 14.958 89.699 ;
     RECT  15.948 88.781 16.614 89.741 ;
     RECT  16.524 89.741 16.614 89.851 ;
     RECT  15.372 90.013 15.426 90.311 ;
     RECT  16.524 89.851 16.65 90.379 ;
     RECT  1.908 89.501 13.914 90.391 ;
     RECT  1.908 90.391 13.986 90.661 ;
     RECT  16.524 90.379 17.154 90.667 ;
     RECT  1.908 90.661 14.058 90.859 ;
     RECT  15.444 90.667 17.154 90.893 ;
     RECT  0.036 87.773 0.09 90.959 ;
     RECT  1.908 90.859 14.454 91.021 ;
     RECT  17.1 90.893 17.154 91.243 ;
     RECT  15.444 90.893 15.966 91.339 ;
     RECT  17.1 91.243 17.19 91.391 ;
     RECT  17.136 91.391 17.19 91.427 ;
     RECT  1.908 91.021 14.634 91.627 ;
     RECT  15.372 91.339 15.966 91.627 ;
     RECT  0.036 90.959 0.054 92.129 ;
     RECT  17.172 91.427 17.19 92.203 ;
     RECT  1.908 91.627 15.966 92.741 ;
     RECT  6.012 92.741 15.966 92.813 ;
     RECT  17.136 92.203 17.19 93.047 ;
     RECT  6.012 92.813 15.894 93.083 ;
     RECT  17.172 93.047 17.19 93.119 ;
     RECT  6.012 93.083 15.858 93.209 ;
     RECT  1.908 92.741 5.238 93.317 ;
     RECT  6.768 93.209 15.858 93.353 ;
     RECT  2.124 93.317 5.238 93.389 ;
     RECT  2.16 93.389 5.238 93.479 ;
     RECT  2.196 93.479 5.238 93.523 ;
     RECT  6.012 93.209 6.03 93.523 ;
     RECT  6.768 93.353 15.318 93.587 ;
     RECT  6.768 93.587 14.958 93.749 ;
     RECT  2.196 93.523 6.03 93.929 ;
     RECT  6.768 93.749 9.882 94.019 ;
     RECT  10.8 93.749 14.922 94.127 ;
     RECT  2.376 93.929 6.03 94.171 ;
     RECT  6.768 94.019 6.894 94.171 ;
     RECT  7.632 94.019 9.882 94.199 ;
     RECT  10.8 94.127 14.886 94.289 ;
     RECT  7.668 94.199 9.882 94.325 ;
     RECT  10.944 94.289 14.886 94.325 ;
     RECT  7.668 94.325 8.73 94.433 ;
     RECT  9.54 94.325 9.558 94.433 ;
     RECT  11.016 94.325 14.886 94.433 ;
     RECT  11.016 94.433 14.238 94.469 ;
     RECT  2.376 94.171 6.894 94.493 ;
     RECT  2.376 94.493 5.958 94.559 ;
     RECT  6.876 94.493 6.894 94.559 ;
     RECT  11.628 94.469 13.497 94.559 ;
     RECT  2.415 94.559 4.374 94.595 ;
     RECT  5.544 94.559 5.886 94.595 ;
     RECT  2.415 94.595 4.23 94.631 ;
     RECT  7.815 94.433 8.73 94.631 ;
     RECT  14.22 94.469 14.238 94.631 ;
     RECT  2.415 94.631 3.834 94.739 ;
     RECT  2.415 94.739 2.697 94.787 ;
     RECT  7.815 94.631 8.097 94.787 ;
     RECT  13.215 94.559 13.497 94.787 ;
     RECT  3.492 94.739 3.654 94.829 ;
     RECT  2.415 94.787 2.505 95.057 ;
     RECT  7.815 94.787 7.905 95.057 ;
     RECT  13.215 94.787 13.305 95.057 ;
    LAYER M4 ;
     RECT  0.025 87.744 0.06 87.768 ;
     RECT  0.06 4.368 0.061 10.44 ;
     RECT  0.06 29.712 0.097 35.784 ;
     RECT  0.06 45.84 0.097 48.84 ;
     RECT  0.06 55.056 0.097 64.968 ;
     RECT  0.06 13.584 0.137 16.584 ;
     RECT  0.06 39.696 0.137 42.696 ;
     RECT  0.06 78.096 0.137 87.768 ;
     RECT  0.061 4.272 0.173 10.44 ;
     RECT  0.137 78.096 0.173 87.144 ;
     RECT  0.173 78.192 0.209 87.144 ;
     RECT  0.209 78.288 0.245 87.144 ;
     RECT  0.06 20.496 1.141 23.496 ;
     RECT  0.097 54.96 2.221 64.968 ;
     RECT  0.173 4.464 2.257 10.44 ;
     RECT  0.097 29.712 2.293 35.88 ;
     RECT  2.221 54.96 2.293 65.688 ;
     RECT  0.245 78.384 2.293 87.144 ;
     RECT  0.137 13.68 2.401 16.584 ;
     RECT  2.221 18.192 2.401 18.216 ;
     RECT  2.257 4.464 2.408 11.256 ;
     RECT  2.401 13.68 2.408 18.216 ;
     RECT  1.141 20.352 2.408 23.496 ;
     RECT  2.293 29.712 2.408 36.552 ;
     RECT  0.137 39.792 2.408 42.696 ;
     RECT  2.293 44.352 2.408 44.376 ;
     RECT  0.097 45.744 2.408 48.84 ;
     RECT  2.293 54.912 2.408 65.688 ;
     RECT  2.293 68.4 2.408 68.424 ;
     RECT  0.06 71.184 2.408 74.184 ;
     RECT  2.293 78.384 2.408 87.96 ;
     RECT  2.293 91.392 2.408 91.416 ;
     RECT  2.408 2.148 2.512 95.052 ;
     RECT  2.512 2.418 2.704 94.782 ;
     RECT  2.704 4.464 2.729 11.256 ;
     RECT  2.704 40.944 2.729 42.6 ;
     RECT  2.704 20.064 2.765 23.4 ;
     RECT  2.729 40.944 2.765 42.504 ;
     RECT  2.704 58.128 2.819 68.76 ;
     RECT  2.729 4.464 2.837 10.152 ;
     RECT  2.704 39.792 2.837 39.816 ;
     RECT  2.704 44.352 2.837 44.376 ;
     RECT  2.819 59.184 2.839 67.848 ;
     RECT  2.704 13.2 2.867 19.032 ;
     RECT  2.704 77.52 2.867 91.416 ;
     RECT  2.704 45.744 2.873 47.112 ;
     RECT  2.837 4.464 2.909 9.912 ;
     RECT  2.909 8.784 2.945 9.912 ;
     RECT  2.704 71.376 2.945 74.568 ;
     RECT  2.704 56.016 2.981 57.096 ;
     RECT  2.867 77.52 3.011 91.32 ;
     RECT  2.729 11.232 3.017 11.256 ;
     RECT  2.945 9.216 3.053 9.912 ;
     RECT  2.704 26.688 3.053 35.496 ;
     RECT  2.873 47.088 3.053 47.112 ;
     RECT  2.839 59.232 3.053 67.848 ;
     RECT  2.909 4.464 3.089 7.704 ;
     RECT  2.867 13.2 3.089 17.16 ;
     RECT  2.867 18.192 3.089 19.032 ;
     RECT  2.704 48.144 3.089 48.696 ;
     RECT  3.011 77.52 3.089 86.856 ;
     RECT  3.053 9.264 3.161 9.912 ;
     RECT  2.765 20.064 3.161 23.352 ;
     RECT  2.704 36.528 3.161 36.552 ;
     RECT  2.765 40.944 3.161 42.024 ;
     RECT  3.161 9.264 3.197 9.528 ;
     RECT  3.053 26.688 3.197 31.512 ;
     RECT  3.161 42 3.197 42.024 ;
     RECT  3.089 48.144 3.197 48.216 ;
     RECT  3.053 67.248 3.203 67.848 ;
     RECT  3.197 26.688 3.251 31.416 ;
     RECT  3.197 48.192 3.269 48.216 ;
     RECT  2.704 54.912 3.269 54.984 ;
     RECT  2.819 58.128 3.269 58.152 ;
     RECT  2.945 72.528 3.269 74.568 ;
     RECT  3.089 77.52 3.269 86.52 ;
     RECT  3.203 67.248 3.338 67.32 ;
     RECT  2.704 92.64 3.34 94.296 ;
     RECT  3.053 32.496 3.341 35.496 ;
     RECT  3.197 9.264 3.377 9.336 ;
     RECT  3.269 72.528 3.377 72.84 ;
     RECT  3.269 77.52 3.377 80.952 ;
     RECT  3.161 20.064 3.413 23.304 ;
     RECT  3.269 81.936 3.485 86.52 ;
     RECT  3.053 59.232 3.521 65.496 ;
     RECT  3.485 84.24 3.521 86.52 ;
     RECT  3.521 59.232 3.557 61.56 ;
     RECT  3.089 15.504 3.593 17.16 ;
     RECT  2.873 45.744 3.593 45.768 ;
     RECT  2.981 56.016 3.593 56.952 ;
     RECT  3.161 40.944 3.697 40.968 ;
     RECT  3.377 9.264 3.701 9.288 ;
     RECT  3.34 92.928 3.881 94.296 ;
     RECT  3.089 19.008 3.913 19.032 ;
     RECT  3.413 20.064 3.913 22.872 ;
     RECT  3.251 26.688 3.913 30.984 ;
     RECT  3.805 38.784 3.917 38.808 ;
     RECT  3.733 2.688 3.949 2.712 ;
     RECT  2.704 24.528 3.949 24.552 ;
     RECT  2.704 50.016 3.949 50.04 ;
     RECT  3.949 49.728 3.973 50.04 ;
     RECT  2.704 70.08 3.98 70.104 ;
     RECT  3.011 88.128 3.98 91.32 ;
     RECT  2.704 52.416 3.985 52.968 ;
     RECT  3.98 69.84 3.985 70.104 ;
     RECT  3.985 68.88 4.021 70.104 ;
     RECT  3.98 88.128 4.067 91.848 ;
     RECT  3.949 2.688 4.069 2.808 ;
     RECT  3.733 10.944 4.093 10.968 ;
     RECT  3.485 81.936 4.097 82.92 ;
     RECT  3.338 67.248 4.129 67.272 ;
     RECT  3.913 19.008 4.133 22.872 ;
     RECT  3.881 93.552 4.133 94.296 ;
     RECT  4.021 68.88 4.165 70.728 ;
     RECT  3.949 24.48 4.213 24.552 ;
     RECT  3.089 13.2 4.237 14.472 ;
     RECT  3.697 40.416 4.237 40.968 ;
     RECT  2.704 76.176 4.237 76.2 ;
     RECT  4.093 51.36 4.273 51.384 ;
     RECT  3.985 52.416 4.273 53.736 ;
     RECT  4.213 24.48 4.3 24.696 ;
     RECT  4.237 40.416 4.309 41.544 ;
     RECT  3.269 54.912 4.309 54.936 ;
     RECT  3.593 56.016 4.309 56.712 ;
     RECT  3.377 77.52 4.313 80.568 ;
     RECT  4.165 68.88 4.316 71.112 ;
     RECT  3.377 72.528 4.316 72.552 ;
     RECT  4.069 1.728 4.345 2.808 ;
     RECT  4.093 44.448 4.345 44.472 ;
     RECT  4.309 46.992 4.345 47.016 ;
     RECT  3.269 74.016 4.345 74.568 ;
     RECT  4.3 24.48 4.357 24.552 ;
     RECT  4.345 74.016 4.357 74.664 ;
     RECT  4.237 75.792 4.357 76.2 ;
     RECT  4.067 88.128 4.357 91.32 ;
     RECT  4.133 94.272 4.385 94.296 ;
     RECT  4.237 13.008 4.405 14.472 ;
     RECT  4.309 39.984 4.412 41.544 ;
     RECT  4.133 22.176 4.444 22.872 ;
     RECT  3.805 36.576 4.453 36.6 ;
     RECT  2.704 37.632 4.453 37.656 ;
     RECT  4.412 39.216 4.453 41.544 ;
     RECT  4.345 43.824 4.453 44.472 ;
     RECT  4.316 68.88 4.453 72.552 ;
     RECT  4.357 74.016 4.453 76.2 ;
     RECT  3.521 84.288 4.453 86.52 ;
     RECT  4.133 19.008 4.457 20.904 ;
     RECT  4.273 51.36 4.46 53.736 ;
     RECT  4.309 54.912 4.46 56.712 ;
     RECT  4.457 19.008 4.489 20.424 ;
     RECT  3.913 26.208 4.489 30.984 ;
     RECT  3.521 62.544 4.489 65.496 ;
     RECT  4.129 66.48 4.489 67.272 ;
     RECT  4.313 77.52 4.489 79.464 ;
     RECT  4.309 48.432 4.493 48.456 ;
     RECT  4.453 43.824 4.499 45.576 ;
     RECT  3.341 34.8 4.501 35.496 ;
     RECT  4.453 36.576 4.501 37.656 ;
     RECT  4.345 46.848 4.517 47.016 ;
     RECT  4.489 25.584 4.525 30.984 ;
     RECT  4.453 84.288 4.525 86.76 ;
     RECT  4.357 87.744 4.525 91.32 ;
     RECT  4.489 18.144 4.529 20.424 ;
     RECT  4.489 62.544 4.529 67.272 ;
     RECT  4.525 84.288 4.529 91.32 ;
     RECT  4.345 1.728 4.565 2.856 ;
     RECT  4.46 51.36 4.595 56.712 ;
     RECT  4.093 10.944 4.597 11.688 ;
     RECT  4.405 13.008 4.597 14.904 ;
     RECT  4.565 2.64 4.633 2.856 ;
     RECT  4.525 25.584 4.633 31.224 ;
     RECT  3.341 32.496 4.633 33.624 ;
     RECT  4.517 46.752 4.633 47.016 ;
     RECT  4.595 56.4 4.633 56.712 ;
     RECT  4.444 22.704 4.637 22.872 ;
     RECT  4.453 39.216 4.673 42.12 ;
     RECT  4.529 62.544 4.709 65.304 ;
     RECT  3.593 15.888 4.741 17.16 ;
     RECT  4.529 18.144 4.741 20.376 ;
     RECT  3.557 59.232 4.741 60.648 ;
     RECT  4.529 66.288 4.741 67.272 ;
     RECT  4.489 77.424 4.741 79.464 ;
     RECT  4.357 23.904 4.745 24.552 ;
     RECT  3.089 4.464 4.777 7.416 ;
     RECT  4.705 9.552 4.849 9.576 ;
     RECT  4.633 25.584 4.849 33.624 ;
     RECT  4.501 34.8 4.849 37.656 ;
     RECT  4.777 4.464 4.885 7.848 ;
     RECT  4.741 59.232 4.921 61.56 ;
     RECT  4.709 62.544 4.921 65.256 ;
     RECT  4.741 15.888 4.925 20.376 ;
     RECT  4.597 10.944 4.957 14.904 ;
     RECT  4.925 15.888 4.957 20.04 ;
     RECT  3.973 49.584 4.993 50.04 ;
     RECT  4.595 51.36 4.993 52.632 ;
     RECT  4.741 66.288 5.065 67.704 ;
     RECT  4.453 68.88 5.065 76.2 ;
     RECT  4.097 81.984 5.065 82.92 ;
     RECT  4.633 46.752 5.069 47.304 ;
     RECT  4.993 49.584 5.087 52.632 ;
     RECT  5.065 81.984 5.101 83.064 ;
     RECT  4.529 88.08 5.132 91.32 ;
     RECT  4.777 92.352 5.132 92.376 ;
     RECT  5.065 68.88 5.137 76.392 ;
     RECT  4.741 77.376 5.137 79.464 ;
     RECT  4.849 25.584 5.173 37.656 ;
     RECT  4.633 56.4 5.173 57.384 ;
     RECT  4.673 39.216 5.177 41.4 ;
     RECT  5.177 39.216 5.213 39.912 ;
     RECT  5.132 88.08 5.219 92.376 ;
     RECT  4.499 44.4 5.245 45.576 ;
     RECT  5.219 92.352 5.245 92.376 ;
     RECT  5.065 66.288 5.249 67.752 ;
     RECT  5.137 68.88 5.281 79.464 ;
     RECT  4.313 80.496 5.281 80.568 ;
     RECT  4.957 10.944 5.285 20.04 ;
     RECT  5.285 10.944 5.317 17.832 ;
     RECT  4.745 24.48 5.317 24.552 ;
     RECT  5.173 25.584 5.317 38.04 ;
     RECT  5.101 81.744 5.317 83.064 ;
     RECT  4.529 84.288 5.317 86.904 ;
     RECT  4.981 42.72 5.357 43.032 ;
     RECT  5.173 56.4 5.389 58.008 ;
     RECT  4.595 53.712 5.393 55.416 ;
     RECT  4.921 59.232 5.393 65.256 ;
     RECT  5.249 66.336 5.425 67.752 ;
     RECT  5.281 68.88 5.425 80.568 ;
     RECT  5.285 19.104 5.429 20.04 ;
     RECT  5.245 44.4 5.461 45.768 ;
     RECT  4.633 2.64 5.497 3.432 ;
     RECT  4.885 4.464 5.497 8.328 ;
     RECT  4.637 22.752 5.497 22.872 ;
     RECT  5.317 24.48 5.497 38.04 ;
     RECT  5.213 39.216 5.497 39.768 ;
     RECT  5.389 56.4 5.497 58.104 ;
     RECT  5.393 59.232 5.497 63.96 ;
     RECT  5.087 48.624 5.573 52.632 ;
     RECT  5.357 42.72 5.653 42.744 ;
     RECT  5.497 24.48 5.681 39.768 ;
     RECT  5.653 42.384 5.699 42.744 ;
     RECT  5.497 56.4 5.717 63.96 ;
     RECT  5.177 40.896 5.745 41.4 ;
     RECT  5.681 24.48 5.789 30.408 ;
     RECT  4.849 9.456 5.821 9.576 ;
     RECT  5.317 10.656 5.821 17.832 ;
     RECT  5.497 22.752 5.821 23.208 ;
     RECT  5.573 51.504 5.821 52.632 ;
     RECT  5.393 53.712 5.821 55.224 ;
     RECT  5.425 66.336 5.825 80.568 ;
     RECT  5.699 42.384 5.861 42.408 ;
     RECT  5.821 9.456 5.897 17.832 ;
     RECT  5.789 24.48 5.897 29.208 ;
     RECT  5.825 70.08 5.897 80.568 ;
     RECT  5.219 88.08 5.897 91.224 ;
     RECT  5.461 44.208 5.933 45.768 ;
     RECT  5.497 2.64 5.965 8.328 ;
     RECT  5.897 9.456 5.965 17.16 ;
     RECT  5.429 19.2 5.969 20.04 ;
     RECT  5.897 88.128 5.969 91.224 ;
     RECT  5.897 25.056 5.987 29.208 ;
     RECT  5.965 2.64 6.005 17.16 ;
     RECT  5.897 70.08 6.005 73.56 ;
     RECT  5.245 92.352 6.037 92.664 ;
     RECT  6.005 70.08 6.041 70.776 ;
     RECT  5.821 22.224 6.073 23.208 ;
     RECT  5.317 81.744 6.109 86.904 ;
     RECT  5.717 56.4 6.113 60.888 ;
     RECT  5.933 44.208 6.131 45.048 ;
     RECT  5.821 51.504 6.149 55.224 ;
     RECT  5.681 31.488 6.181 39.768 ;
     RECT  5.969 88.608 6.181 91.224 ;
     RECT  6.037 92.352 6.181 92.76 ;
     RECT  6.149 52.416 6.185 55.224 ;
     RECT  6.181 88.608 6.221 92.76 ;
     RECT  5.069 46.752 6.253 47.208 ;
     RECT  6.109 81.648 6.253 86.904 ;
     RECT  5.717 61.872 6.257 63.96 ;
     RECT  5.461 94.464 6.257 94.488 ;
     RECT  6.181 31.488 6.275 39.912 ;
     RECT  5.987 25.056 6.293 25.608 ;
     RECT  6.185 52.512 6.293 55.224 ;
     RECT  6.005 71.952 6.293 73.56 ;
     RECT  5.897 74.544 6.293 80.568 ;
     RECT  5.393 64.992 6.329 65.256 ;
     RECT  5.987 27.216 6.365 29.208 ;
     RECT  6.275 31.488 6.365 39.576 ;
     RECT  6.131 44.208 6.397 44.856 ;
     RECT  6.365 31.488 6.401 37.608 ;
     RECT  6.257 61.968 6.421 63.96 ;
     RECT  6.329 64.992 6.421 65.16 ;
     RECT  6.253 46.32 6.428 47.208 ;
     RECT  6.421 61.968 6.467 65.16 ;
     RECT  6.005 2.64 6.473 14.472 ;
     RECT  6.005 15.504 6.473 17.16 ;
     RECT  6.293 71.952 6.473 72.12 ;
     RECT  6.293 73.44 6.509 73.56 ;
     RECT  5.965 42.096 6.515 42.264 ;
     RECT  6.428 46.32 6.541 47.544 ;
     RECT  5.573 48.624 6.541 50.424 ;
     RECT  5.605 21.168 6.577 21.192 ;
     RECT  6.365 28.32 6.581 29.208 ;
     RECT  5.825 66.336 6.581 69 ;
     RECT  6.293 74.592 6.581 80.568 ;
     RECT  6.473 72.048 6.617 72.12 ;
     RECT  6.401 31.488 6.653 32.376 ;
     RECT  6.473 15.504 6.725 16.44 ;
     RECT  6.653 31.872 6.761 32.376 ;
     RECT  6.581 75.696 6.761 76.392 ;
     RECT  6.577 20.496 6.793 21.192 ;
     RECT  6.073 22.224 6.793 23.88 ;
     RECT  6.581 28.32 6.797 28.872 ;
     RECT  6.541 46.32 6.797 50.424 ;
     RECT  6.365 38.784 6.803 39.576 ;
     RECT  6.041 70.752 6.833 70.776 ;
     RECT  6.617 72.096 6.833 72.12 ;
     RECT  6.473 2.64 6.853 3 ;
     RECT  6.797 49.44 6.865 50.424 ;
     RECT  5.745 40.896 7.009 40.92 ;
     RECT  5.789 30.192 7.081 30.408 ;
     RECT  5.969 19.2 7.189 19.224 ;
     RECT  6.221 88.608 7.189 88.824 ;
     RECT  7.189 88.608 7.196 88.968 ;
     RECT  6.221 89.952 7.196 92.76 ;
     RECT  7.153 26.208 7.225 26.232 ;
     RECT  6.365 27.216 7.225 27.24 ;
     RECT  6.113 56.496 7.225 60.888 ;
     RECT  6.397 43.824 7.261 44.856 ;
     RECT  6.581 77.424 7.261 80.568 ;
     RECT  6.253 81.648 7.261 87.144 ;
     RECT  6.937 42.288 7.333 42.312 ;
     RECT  7.196 88.608 7.333 92.76 ;
     RECT  6.901 17.616 7.381 17.832 ;
     RECT  7.189 19.2 7.381 19.368 ;
     RECT  6.793 20.496 7.381 23.88 ;
     RECT  7.333 42.288 7.477 42.6 ;
     RECT  7.477 42.192 7.513 42.6 ;
     RECT  7.261 43.824 7.513 45 ;
     RECT  7.225 56.496 7.549 60.984 ;
     RECT  6.467 61.968 7.549 64.92 ;
     RECT  6.803 39.456 7.585 39.576 ;
     RECT  7.009 40.896 7.585 41.16 ;
     RECT  7.225 26.208 7.621 27.24 ;
     RECT  6.797 28.32 7.621 28.344 ;
     RECT  7.513 42.192 7.621 45 ;
     RECT  6.797 46.32 7.621 47.928 ;
     RECT  6.293 52.608 7.621 55.224 ;
     RECT  7.549 56.496 7.621 64.92 ;
     RECT  7.009 69.6 7.621 69.624 ;
     RECT  6.581 74.592 7.801 74.616 ;
     RECT  6.761 75.696 7.801 76.152 ;
     RECT  6.853 2.256 7.808 3 ;
     RECT  6.473 4.08 7.808 14.472 ;
     RECT  6.725 15.504 7.808 15.528 ;
     RECT  7.381 17.616 7.808 23.88 ;
     RECT  6.293 25.056 7.808 25.08 ;
     RECT  7.621 26.208 7.808 28.344 ;
     RECT  7.081 30.192 7.808 30.888 ;
     RECT  6.761 31.872 7.808 32.328 ;
     RECT  6.401 33.36 7.808 37.608 ;
     RECT  7.585 39.456 7.808 41.16 ;
     RECT  7.621 42.192 7.808 47.928 ;
     RECT  6.865 49.44 7.808 50.664 ;
     RECT  7.621 52.608 7.808 64.92 ;
     RECT  6.581 66.336 7.808 68.136 ;
     RECT  7.621 69.6 7.808 70.056 ;
     RECT  6.509 73.536 7.808 73.56 ;
     RECT  7.801 74.592 7.808 76.152 ;
     RECT  7.261 77.424 7.808 87.144 ;
     RECT  7.333 88.608 7.808 93.048 ;
     RECT  7.808 2.148 7.912 95.052 ;
     RECT  7.912 2.418 8.104 94.782 ;
     RECT  8.104 81.984 8.165 83.688 ;
     RECT  8.104 9.36 8.201 10.344 ;
     RECT  8.104 12.336 8.201 13.32 ;
     RECT  8.104 56.88 8.201 60.072 ;
     RECT  8.104 79.872 8.201 80.376 ;
     RECT  8.104 20.544 8.243 27.672 ;
     RECT  8.104 43.68 8.273 47.304 ;
     RECT  8.104 64.416 8.273 70.872 ;
     RECT  8.104 72.48 8.291 76.488 ;
     RECT  8.291 72.48 8.309 75.72 ;
     RECT  8.165 81.984 8.309 82.008 ;
     RECT  8.104 90.24 8.309 90.552 ;
     RECT  8.104 61.968 8.381 63.288 ;
     RECT  8.104 14.832 8.417 19.368 ;
     RECT  8.243 20.544 8.428 21.144 ;
     RECT  8.104 40.8 8.453 41.16 ;
     RECT  8.417 14.832 8.461 18.312 ;
     RECT  8.381 62.16 8.489 63.288 ;
     RECT  8.104 29.232 8.524 36.216 ;
     RECT  8.104 3.936 8.525 7.752 ;
     RECT  8.104 86.832 8.531 87.528 ;
     RECT  8.524 31.248 8.533 36.216 ;
     RECT  8.461 14.832 8.561 16.152 ;
     RECT  8.309 72.48 8.579 75.144 ;
     RECT  8.104 2.592 8.597 2.808 ;
     RECT  8.104 48.384 8.597 55.224 ;
     RECT  8.561 16.128 8.633 16.152 ;
     RECT  8.461 17.904 8.633 18.312 ;
     RECT  8.273 64.656 8.668 70.872 ;
     RECT  8.597 2.736 8.705 2.808 ;
     RECT  8.525 3.936 8.723 7.272 ;
     RECT  8.668 68.64 8.777 70.872 ;
     RECT  8.104 37.296 8.849 39.576 ;
     RECT  8.273 43.68 8.849 45.72 ;
     RECT  8.597 48.384 8.857 55.128 ;
     RECT  8.533 33.072 8.867 36.216 ;
     RECT  8.849 37.296 8.867 38.76 ;
     RECT  8.309 90.24 8.885 90.264 ;
     RECT  8.867 35.856 8.908 36.216 ;
     RECT  8.668 64.656 8.915 67.368 ;
     RECT  8.524 29.232 8.921 30.168 ;
     RECT  8.867 33.072 8.921 34.728 ;
     RECT  8.915 66.096 8.956 67.368 ;
     RECT  8.867 37.584 8.957 38.76 ;
     RECT  8.849 43.68 8.993 45 ;
     RECT  8.201 57.168 8.993 60.072 ;
     RECT  8.243 22.464 9.065 27.672 ;
     RECT  8.104 42.192 9.097 42.312 ;
     RECT  8.104 77.952 9.097 78.888 ;
     RECT  8.201 79.872 9.097 79.896 ;
     RECT  8.273 46.704 9.107 47.304 ;
     RECT  8.857 48.384 9.107 50.76 ;
     RECT  8.165 82.992 9.109 83.688 ;
     RECT  9.109 82.992 9.164 83.832 ;
     RECT  9.097 77.952 9.169 79.896 ;
     RECT  8.921 33.312 9.173 34.728 ;
     RECT  8.993 43.68 9.173 43.704 ;
     RECT  8.993 58.512 9.203 60.072 ;
     RECT  8.723 4.512 9.209 7.272 ;
     RECT  8.777 68.64 9.209 68.664 ;
     RECT  8.579 72.48 9.209 74.52 ;
     RECT  9.164 82.272 9.209 83.832 ;
     RECT  8.453 40.8 9.216 41.064 ;
     RECT  8.993 57.168 9.245 57.336 ;
     RECT  9.209 72.912 9.245 74.52 ;
     RECT  9.209 82.272 9.251 83.208 ;
     RECT  8.201 12.816 9.277 13.32 ;
     RECT  9.065 22.8 9.277 27.672 ;
     RECT  9.097 42.192 9.281 42.552 ;
     RECT  9.245 57.312 9.281 57.336 ;
     RECT  8.777 69.84 9.308 70.872 ;
     RECT  9.277 12.72 9.313 13.32 ;
     RECT  8.561 14.832 9.313 14.856 ;
     RECT  9.203 58.656 9.349 60.072 ;
     RECT  8.489 62.16 9.349 62.856 ;
     RECT  8.104 84.96 9.349 85.8 ;
     RECT  8.531 86.832 9.349 86.856 ;
     RECT  9.209 4.656 9.353 7.272 ;
     RECT  8.533 31.248 9.353 31.704 ;
     RECT  8.104 88.848 9.353 88.968 ;
     RECT  8.915 64.656 9.385 65.016 ;
     RECT  9.353 5.04 9.389 7.272 ;
     RECT  9.205 11.376 9.421 11.4 ;
     RECT  9.349 58.656 9.425 60.312 ;
     RECT  9.425 58.848 9.443 60.312 ;
     RECT  9.349 61.776 9.443 62.856 ;
     RECT  9.349 76.464 9.452 76.488 ;
     RECT  9.169 77.616 9.452 79.896 ;
     RECT  9.313 12.72 9.457 14.856 ;
     RECT  9.385 63.84 9.469 65.016 ;
     RECT  9.452 76.464 9.485 79.896 ;
     RECT  8.201 9.648 9.493 10.344 ;
     RECT  9.421 11.376 9.493 11.496 ;
     RECT  9.353 31.248 9.493 31.56 ;
     RECT  9.107 46.704 9.529 46.728 ;
     RECT  9.389 5.04 9.533 6.84 ;
     RECT  9.493 9.648 9.565 11.496 ;
     RECT  9.245 74.448 9.565 74.52 ;
     RECT  9.565 9.648 9.589 11.592 ;
     RECT  9.457 12.576 9.589 14.856 ;
     RECT  8.417 19.344 9.596 19.368 ;
     RECT  9.485 75.792 9.601 79.896 ;
     RECT  8.633 18.144 9.637 18.312 ;
     RECT  9.596 19.344 9.637 19.848 ;
     RECT  8.428 21.12 9.637 21.144 ;
     RECT  9.565 74.448 9.637 74.712 ;
     RECT  9.601 75.792 9.637 80.04 ;
     RECT  9.589 9.648 9.677 14.856 ;
     RECT  9.349 84.96 9.677 86.856 ;
     RECT  9.677 9.648 9.713 11.592 ;
     RECT  8.957 37.584 9.713 37.608 ;
     RECT  9.637 18.144 9.724 21.144 ;
     RECT  9.493 30.96 9.731 31.56 ;
     RECT  9.533 5.04 9.749 5.736 ;
     RECT  9.637 74.448 9.749 80.04 ;
     RECT  9.713 9.648 9.781 9.672 ;
     RECT  9.677 12.576 9.785 14.856 ;
     RECT  9.443 62.16 9.785 62.76 ;
     RECT  9.308 69.84 9.785 71.352 ;
     RECT  9.277 22.8 9.817 28.104 ;
     RECT  8.921 29.232 9.817 29.832 ;
     RECT  9.385 90.48 9.817 90.504 ;
     RECT  8.104 91.584 9.817 93.768 ;
     RECT  9.281 42.288 9.853 42.552 ;
     RECT  9.173 33.312 9.857 33.624 ;
     RECT  9.749 5.04 9.893 5.448 ;
     RECT  9.817 90.48 9.893 93.768 ;
     RECT  9.817 22.8 9.929 29.832 ;
     RECT  9.785 69.84 9.961 70.296 ;
     RECT  9.353 88.944 9.965 88.968 ;
     RECT  9.929 24.192 9.971 29.832 ;
     RECT  9.205 81.216 10.001 81.24 ;
     RECT  8.705 2.736 10.069 2.76 ;
     RECT  9.724 19.344 10.069 21.144 ;
     RECT  9.929 22.8 10.069 23.16 ;
     RECT  8.857 52.32 10.109 55.128 ;
     RECT  9.107 48.384 10.141 48.552 ;
     RECT  9.107 49.584 10.141 50.76 ;
     RECT  10.109 52.32 10.141 53.784 ;
     RECT  10.109 55.104 10.141 55.128 ;
     RECT  9.469 63.936 10.141 65.016 ;
     RECT  10.069 2.736 10.145 3.192 ;
     RECT  8.957 38.736 10.145 38.76 ;
     RECT  10.141 55.104 10.172 56.088 ;
     RECT  9.749 74.496 10.181 80.04 ;
     RECT  10.145 3.072 10.213 3.192 ;
     RECT  9.785 71.28 10.213 71.352 ;
     RECT  9.245 72.912 10.213 73.128 ;
     RECT  10.141 63.936 10.249 65.16 ;
     RECT  9.893 90.48 10.249 93.672 ;
     RECT  10.069 19.344 10.259 23.16 ;
     RECT  10.172 55.104 10.259 56.232 ;
     RECT  9.216 40.8 10.285 40.824 ;
     RECT  10.249 63.936 10.285 65.832 ;
     RECT  8.956 66.816 10.285 67.368 ;
     RECT  9.781 8.688 10.289 9.672 ;
     RECT  9.971 24.192 10.289 27.864 ;
     RECT  9.971 28.944 10.289 29.832 ;
     RECT  8.993 44.832 10.316 45 ;
     RECT  9.961 69.168 10.325 70.296 ;
     RECT  9.529 46.176 10.349 46.728 ;
     RECT  9.853 42.288 10.357 43.56 ;
     RECT  10.357 82.56 10.393 82.584 ;
     RECT  10.259 22.464 10.403 23.16 ;
     RECT  9.745 17.088 10.412 17.112 ;
     RECT  9.724 18.144 10.412 18.36 ;
     RECT  9.785 62.736 10.433 62.76 ;
     RECT  10.357 42.24 10.453 43.56 ;
     RECT  10.316 44.544 10.453 45 ;
     RECT  10.349 46.176 10.453 46.776 ;
     RECT  10.285 63.936 10.46 67.368 ;
     RECT  10.325 69.168 10.46 70.248 ;
     RECT  10.453 42.192 10.461 43.56 ;
     RECT  10.453 44.544 10.465 46.776 ;
     RECT  10.141 48.384 10.465 50.76 ;
     RECT  10.465 44.544 10.499 50.76 ;
     RECT  10.499 44.832 10.501 50.76 ;
     RECT  10.141 51.936 10.501 53.784 ;
     RECT  10.357 84.336 10.537 84.36 ;
     RECT  10.501 44.832 10.541 53.784 ;
     RECT  9.443 58.848 10.541 60.168 ;
     RECT  10.46 63.936 10.541 70.248 ;
     RECT  10.537 84.192 10.573 84.36 ;
     RECT  9.677 85.536 10.573 86.856 ;
     RECT  10.541 46.368 10.577 53.784 ;
     RECT  10.249 89.952 10.609 93.672 ;
     RECT  10.609 89.52 10.613 93.672 ;
     RECT  10.259 55.152 10.645 56.232 ;
     RECT  10.573 57.264 10.645 57.288 ;
     RECT  10.393 82.128 10.649 82.584 ;
     RECT  10.213 71.28 10.681 73.128 ;
     RECT  9.533 6.816 10.753 6.84 ;
     RECT  10.259 19.344 10.757 20.184 ;
     RECT  10.577 50.688 10.757 53.784 ;
     RECT  10.613 91.2 10.757 93.672 ;
     RECT  10.177 15.84 10.781 15.864 ;
     RECT  10.412 17.088 10.781 18.36 ;
     RECT  9.713 10.848 10.789 11.592 ;
     RECT  9.785 12.576 10.789 14.04 ;
     RECT  10.781 15.84 10.789 18.36 ;
     RECT  10.757 53.568 10.793 53.784 ;
     RECT  9.893 5.088 10.825 5.448 ;
     RECT  10.645 55.152 10.825 57.48 ;
     RECT  10.541 58.848 10.825 59.016 ;
     RECT  10.289 24.192 10.829 26.232 ;
     RECT  10.181 74.688 10.829 80.04 ;
     RECT  10.285 39.888 10.837 40.824 ;
     RECT  10.289 9.648 10.861 9.672 ;
     RECT  10.789 10.848 10.861 14.04 ;
     RECT  10.259 21.408 10.865 21.432 ;
     RECT  10.577 46.368 10.865 49.608 ;
     RECT  10.757 50.688 10.865 52.536 ;
     RECT  10.541 60.144 10.865 60.168 ;
     RECT  10.681 71.28 10.865 73.416 ;
     RECT  10.289 29.808 10.897 29.832 ;
     RECT  9.731 30.96 10.897 31.224 ;
     RECT  10.213 3.072 10.933 3.48 ;
     RECT  10.861 8.496 10.933 8.52 ;
     RECT  10.613 89.52 10.933 89.976 ;
     RECT  10.461 43.536 10.969 43.56 ;
     RECT  10.681 32.448 11.005 32.472 ;
     RECT  9.857 33.6 11.005 33.624 ;
     RECT  9.173 34.704 11.005 34.728 ;
     RECT  10.897 29.808 11.009 31.224 ;
     RECT  10.541 44.832 11.009 45.336 ;
     RECT  10.541 64.608 11.009 70.248 ;
     RECT  10.753 6.576 11.029 6.84 ;
     RECT  10.933 8.064 11.029 8.52 ;
     RECT  10.573 85.536 11.037 87.768 ;
     RECT  10.829 24.192 11.045 24.84 ;
     RECT  10.789 15.408 11.077 18.36 ;
     RECT  10.793 53.76 11.077 53.784 ;
     RECT  10.403 22.464 11.081 22.488 ;
     RECT  11.037 85.536 11.081 86.808 ;
     RECT  11.009 30.096 11.085 31.224 ;
     RECT  8.908 35.856 11.113 35.88 ;
     RECT  10.573 37.104 11.113 37.128 ;
     RECT  10.861 9.648 11.116 14.04 ;
     RECT  10.825 5.088 11.117 5.496 ;
     RECT  11.009 67.824 11.117 70.248 ;
     RECT  10.461 42.192 11.125 42.552 ;
     RECT  10.289 27.552 11.149 27.864 ;
     RECT  10.865 46.608 11.153 49.032 ;
     RECT  11.153 47.328 11.171 49.032 ;
     RECT  11.005 33.6 11.173 34.728 ;
     RECT  11.113 35.856 11.173 37.128 ;
     RECT  11.085 30.096 11.189 31.368 ;
     RECT  10.933 89.472 11.189 89.976 ;
     RECT  11.009 44.88 11.212 45.336 ;
     RECT  11.189 30.288 11.221 31.368 ;
     RECT  11.005 32.448 11.221 32.52 ;
     RECT  10.865 50.736 11.225 52.536 ;
     RECT  10.501 38.16 11.228 38.52 ;
     RECT  10.837 39.888 11.228 41.064 ;
     RECT  10.933 3.072 11.257 3.864 ;
     RECT  11.117 5.088 11.257 5.448 ;
     RECT  10.757 20.16 11.257 20.184 ;
     RECT  11.077 53.76 11.257 53.928 ;
     RECT  10.825 55.152 11.257 59.016 ;
     RECT  11.009 64.608 11.261 66.84 ;
     RECT  11.173 33.6 11.269 37.128 ;
     RECT  11.228 38.16 11.269 41.064 ;
     RECT  11.125 42.048 11.297 42.552 ;
     RECT  10.753 63.552 11.297 63.576 ;
     RECT  10.829 75.216 11.329 80.04 ;
     RECT  10.573 83.808 11.329 84.36 ;
     RECT  11.257 53.76 11.333 59.016 ;
     RECT  11.257 3.072 11.365 5.448 ;
     RECT  11.225 50.832 11.369 52.536 ;
     RECT  11.365 2.832 11.411 5.448 ;
     RECT  11.333 54.336 11.411 59.016 ;
     RECT  10.865 71.28 11.411 72.408 ;
     RECT  11.149 27.552 11.413 28.152 ;
     RECT  11.329 75.216 11.413 80.424 ;
     RECT  11.116 11.328 11.441 14.04 ;
     RECT  11.369 52.512 11.441 52.536 ;
     RECT  11.411 2.832 11.449 5.208 ;
     RECT  11.411 71.376 11.449 72.408 ;
     RECT  11.413 27.312 11.459 28.152 ;
     RECT  11.261 64.608 11.507 66.552 ;
     RECT  11.117 67.824 11.507 67.848 ;
     RECT  11.507 64.608 11.509 65.976 ;
     RECT  10.865 73.392 11.509 73.416 ;
     RECT  10.649 82.128 11.509 82.296 ;
     RECT  11.029 6.576 11.513 8.52 ;
     RECT  11.077 15.408 11.513 18.84 ;
     RECT  11.297 42.24 11.513 42.552 ;
     RECT  11.509 73.392 11.545 73.608 ;
     RECT  10.897 60.912 11.564 60.984 ;
     RECT  10.829 26.208 11.612 26.232 ;
     RECT  11.269 33.6 11.621 41.064 ;
     RECT  11.171 47.616 11.621 49.032 ;
     RECT  11.509 63.792 11.629 65.976 ;
     RECT  11.629 64.32 11.644 65.976 ;
     RECT  11.221 30.288 11.651 32.52 ;
     RECT  11.117 69.072 11.651 70.248 ;
     RECT  11.257 20.16 11.653 20.232 ;
     RECT  11.651 31.728 11.653 32.52 ;
     RECT  11.621 33.6 11.653 35.208 ;
     RECT  11.441 11.328 11.693 11.448 ;
     RECT  11.513 17.184 11.693 18.84 ;
     RECT  11.441 12.576 11.699 14.04 ;
     RECT  11.621 36.384 11.699 39.624 ;
     RECT  11.621 49.008 11.699 49.032 ;
     RECT  11.699 12.576 11.729 13.944 ;
     RECT  11.651 30.288 11.729 30.6 ;
     RECT  11.621 40.944 11.729 41.064 ;
     RECT  11.693 17.28 11.756 18.84 ;
     RECT  11.116 9.648 11.761 9.912 ;
     RECT  11.513 15.408 11.761 15.672 ;
     RECT  11.756 17.28 11.761 19.128 ;
     RECT  11.653 20.16 11.761 20.76 ;
     RECT  11.513 7.92 11.797 8.52 ;
     RECT  11.761 9.6 11.797 9.912 ;
     RECT  11.693 11.424 11.801 11.448 ;
     RECT  11.413 75.216 11.801 79.752 ;
     RECT  11.329 83.808 11.804 84.408 ;
     RECT  11.081 85.536 11.804 86.664 ;
     RECT  11.411 54.72 11.833 59.016 ;
     RECT  11.545 73.392 11.837 74.136 ;
     RECT  11.801 78.864 11.837 79.752 ;
     RECT  11.612 26.208 11.869 26.28 ;
     RECT  11.509 81.888 11.869 82.296 ;
     RECT  10.757 91.2 11.869 91.944 ;
     RECT  10.757 93.312 11.869 93.672 ;
     RECT  11.653 31.728 11.873 35.208 ;
     RECT  11.513 42.48 11.905 42.552 ;
     RECT  10.969 43.536 11.905 43.656 ;
     RECT  11.869 91.2 11.905 93.672 ;
     RECT  11.045 24.192 12.013 24.648 ;
     RECT  11.869 25.728 12.013 26.28 ;
     RECT  11.905 42.48 12.013 43.656 ;
     RECT  11.905 91.104 12.017 93.672 ;
     RECT  12.013 42.48 12.049 43.848 ;
     RECT  11.212 44.88 12.049 44.904 ;
     RECT  11.761 17.28 12.053 20.76 ;
     RECT  12.049 42.48 12.053 44.904 ;
     RECT  11.564 60.912 12.085 61.032 ;
     RECT  11.837 74.112 12.085 74.136 ;
     RECT  11.801 75.216 12.085 77.592 ;
     RECT  11.804 83.808 12.085 86.664 ;
     RECT  12.017 93.312 12.085 93.672 ;
     RECT  11.977 22.08 12.121 22.104 ;
     RECT  11.699 36.528 12.125 39.624 ;
     RECT  11.621 47.616 12.125 47.976 ;
     RECT  12.125 36.528 12.161 38.184 ;
     RECT  11.644 65.664 12.161 65.976 ;
     RECT  11.449 3.168 12.179 5.208 ;
     RECT  12.085 60.912 12.301 61.608 ;
     RECT  11.545 62.64 12.301 62.664 ;
     RECT  11.189 89.472 12.373 89.544 ;
     RECT  11.449 71.376 12.421 71.832 ;
     RECT  12.053 18.24 12.445 20.76 ;
     RECT  12.121 22.032 12.445 22.104 ;
     RECT  11.369 50.832 12.445 51.432 ;
     RECT  12.421 71.232 12.445 71.832 ;
     RECT  12.373 89.472 12.445 90.12 ;
     RECT  11.729 30.288 12.469 30.312 ;
     RECT  11.651 69.072 12.469 69.48 ;
     RECT  12.445 88.896 12.476 90.12 ;
     RECT  12.013 23.952 12.509 26.28 ;
     RECT  12.179 5.04 12.517 5.208 ;
     RECT  11.513 6.576 12.517 6.936 ;
     RECT  11.729 12.576 12.517 13.128 ;
     RECT  12.085 83.808 12.517 87.24 ;
     RECT  12.476 88.848 12.517 90.12 ;
     RECT  12.017 91.104 12.517 92.088 ;
     RECT  12.509 23.328 12.553 26.28 ;
     RECT  11.459 27.312 12.553 27.96 ;
     RECT  11.869 81.888 12.565 82.488 ;
     RECT  12.517 83.808 12.565 92.088 ;
     RECT  11.873 31.728 12.613 33.096 ;
     RECT  12.445 50.112 12.613 51.432 ;
     RECT  12.193 53.04 12.613 53.064 ;
     RECT  11.833 54.72 12.625 59.784 ;
     RECT  12.301 60.912 12.625 62.664 ;
     RECT  12.553 23.328 12.733 27.96 ;
     RECT  12.125 47.952 12.757 47.976 ;
     RECT  12.613 50.112 12.757 53.064 ;
     RECT  11.761 15.264 12.764 15.672 ;
     RECT  12.764 15.264 12.805 16.248 ;
     RECT  12.517 11.664 12.841 13.128 ;
     RECT  11.837 78.864 12.877 79.56 ;
     RECT  12.613 31.344 12.913 33.096 ;
     RECT  12.469 29.76 12.949 30.312 ;
     RECT  12.565 81.888 12.949 92.088 ;
     RECT  12.125 39.168 12.985 39.624 ;
     RECT  12.517 5.04 13.021 6.936 ;
     RECT  11.797 7.92 13.021 9.912 ;
     RECT  11.644 64.32 13.021 64.68 ;
     RECT  12.625 54.72 13.052 62.664 ;
     RECT  12.949 81.648 13.052 92.088 ;
     RECT  12.517 46.608 13.057 46.632 ;
     RECT  12.757 49.488 13.057 53.064 ;
     RECT  12.445 18.24 13.093 22.104 ;
     RECT  12.985 39.168 13.093 40.008 ;
     RECT  11.729 41.04 13.093 41.064 ;
     RECT  12.179 3.168 13.208 3.384 ;
     RECT  13.021 5.04 13.208 9.912 ;
     RECT  12.841 10.992 13.208 13.128 ;
     RECT  12.805 14.496 13.208 16.248 ;
     RECT  13.093 17.616 13.208 22.104 ;
     RECT  12.733 23.28 13.208 27.96 ;
     RECT  12.949 29.568 13.208 30.312 ;
     RECT  12.913 31.344 13.208 33.144 ;
     RECT  11.873 34.176 13.208 35.208 ;
     RECT  12.161 36.528 13.208 37.896 ;
     RECT  13.093 39.168 13.208 41.064 ;
     RECT  12.053 42.48 13.208 44.472 ;
     RECT  13.057 46.56 13.208 46.632 ;
     RECT  12.757 47.952 13.208 48.456 ;
     RECT  13.057 49.488 13.208 53.112 ;
     RECT  13.052 54.72 13.208 62.712 ;
     RECT  13.021 63.84 13.208 64.68 ;
     RECT  12.161 65.712 13.208 65.976 ;
     RECT  12.469 68.352 13.208 69.48 ;
     RECT  12.445 70.752 13.208 71.832 ;
     RECT  12.229 72.816 13.208 72.84 ;
     RECT  12.085 74.112 13.208 77.592 ;
     RECT  12.877 78.864 13.208 79.752 ;
     RECT  13.052 80.928 13.208 92.088 ;
     RECT  12.085 93.312 13.208 94.536 ;
     RECT  13.208 2.148 13.312 95.052 ;
     RECT  13.312 2.418 13.504 94.782 ;
     RECT  13.504 80.016 13.529 80.04 ;
     RECT  13.504 31.776 13.565 39.336 ;
     RECT  13.504 40.56 13.601 41.592 ;
     RECT  13.565 31.776 13.619 38.808 ;
     RECT  13.504 54.48 13.619 57.624 ;
     RECT  13.504 85.392 13.637 91.944 ;
     RECT  13.619 57.6 13.645 57.624 ;
     RECT  13.504 10.944 13.667 13.08 ;
     RECT  13.667 12.768 13.673 13.08 ;
     RECT  13.504 93.312 13.673 94.104 ;
     RECT  13.504 67.152 13.68 67.176 ;
     RECT  13.504 14.832 13.681 15.24 ;
     RECT  13.601 40.896 13.709 41.592 ;
     RECT  13.637 86.64 13.709 91.944 ;
     RECT  13.504 29.52 13.763 30.264 ;
     RECT  13.504 70.704 13.781 71.688 ;
     RECT  13.709 90.528 13.811 91.944 ;
     RECT  13.619 31.776 13.817 37.896 ;
     RECT  13.504 46.56 13.817 46.728 ;
     RECT  13.504 18.72 13.853 19.32 ;
     RECT  13.817 31.92 13.853 37.608 ;
     RECT  13.504 78.144 13.853 78.504 ;
     RECT  13.504 82.032 13.859 84.408 ;
     RECT  13.853 18.72 13.889 19.272 ;
     RECT  13.817 46.704 13.889 46.728 ;
     RECT  13.504 47.952 13.889 49.512 ;
     RECT  13.781 71.376 13.889 71.688 ;
     RECT  13.859 82.656 13.889 84.408 ;
     RECT  13.889 83.088 13.907 84.408 ;
     RECT  13.889 19.248 13.925 19.272 ;
     RECT  13.504 59.232 13.925 60.072 ;
     RECT  13.504 21.216 13.961 23.304 ;
     RECT  13.637 85.392 13.961 85.416 ;
     RECT  13.504 6.384 13.997 6.936 ;
     RECT  13.504 9.6 13.997 9.624 ;
     RECT  13.681 15.216 13.997 15.24 ;
     RECT  13.853 78.144 13.997 78.168 ;
     RECT  13.504 52.992 14.003 53.4 ;
     RECT  13.619 54.48 14.003 56.616 ;
     RECT  13.997 6.912 14.033 6.936 ;
     RECT  13.673 12.768 14.033 12.792 ;
     RECT  13.504 17.616 14.033 17.64 ;
     RECT  13.961 22.032 14.033 23.304 ;
     RECT  13.889 48.816 14.033 49.512 ;
     RECT  13.925 59.232 14.033 59.256 ;
     RECT  13.504 25.728 14.099 27.912 ;
     RECT  13.763 29.52 14.099 29.592 ;
     RECT  14.003 55.152 14.099 56.616 ;
     RECT  13.504 3.312 14.177 3.384 ;
     RECT  13.504 43.536 14.177 44.376 ;
     RECT  14.177 3.36 14.285 3.384 ;
     RECT  14.099 29.568 14.285 29.592 ;
     RECT  13.709 40.896 14.285 41.112 ;
     RECT  13.504 75.408 14.285 76.584 ;
     RECT  13.853 31.92 14.321 36.888 ;
     RECT  13.907 83.232 14.321 84.408 ;
     RECT  14.285 41.088 14.357 41.112 ;
     RECT  13.504 50.832 14.357 51.432 ;
     RECT  14.099 25.728 14.393 25.752 ;
     RECT  14.177 43.536 14.393 43.656 ;
     RECT  14.321 83.232 14.393 83.256 ;
     RECT  14.099 27.888 14.429 27.912 ;
     RECT  14.033 48.816 14.429 48.984 ;
     RECT  13.889 71.664 14.465 71.688 ;
     RECT  14.321 84.384 14.465 84.408 ;
     RECT  13.504 8.112 14.497 8.52 ;
     RECT  13.504 62.112 14.569 62.136 ;
     RECT  13.504 63.36 14.569 64.44 ;
     RECT  14.033 22.368 14.641 23.304 ;
     RECT  13.504 24.624 14.641 24.648 ;
     RECT  13.667 10.944 14.645 11.64 ;
     RECT  14.569 62.112 14.717 64.44 ;
     RECT  14.605 42.48 14.749 42.504 ;
     RECT  14.321 31.92 14.753 36.648 ;
     RECT  14.003 52.992 14.753 53.016 ;
     RECT  14.497 8.112 14.785 9.192 ;
     RECT  14.285 75.456 14.789 76.584 ;
     RECT  14.641 22.368 14.821 24.648 ;
     RECT  14.677 79.488 14.825 79.512 ;
     RECT  13.709 86.64 14.825 89.448 ;
     RECT  13.673 93.312 14.825 93.336 ;
     RECT  14.821 22.368 14.861 25.32 ;
     RECT  14.357 50.88 14.861 51.432 ;
     RECT  13.504 65.712 15.109 65.832 ;
     RECT  15.109 65.712 15.217 66.696 ;
     RECT  13.811 90.96 15.289 91.944 ;
     RECT  14.099 55.248 15.325 56.616 ;
     RECT  14.821 11.76 15.361 12.552 ;
     RECT  14.861 23.28 15.361 25.32 ;
     RECT  14.753 32.208 15.361 36.648 ;
     RECT  15.325 37.872 15.361 38.28 ;
     RECT  15.325 44.304 15.361 44.328 ;
     RECT  14.429 48.96 15.361 48.984 ;
     RECT  14.861 50.88 15.361 51.336 ;
     RECT  14.857 80.112 15.361 80.136 ;
     RECT  14.825 86.736 15.361 89.448 ;
     RECT  15.289 90.96 15.361 92.52 ;
     RECT  14.785 7.536 15.397 9.192 ;
     RECT  15.361 16.944 15.397 16.968 ;
     RECT  15.361 18 15.397 18.024 ;
     RECT  15.361 44.112 15.397 44.328 ;
     RECT  15.361 48.96 15.397 51.336 ;
     RECT  14.717 62.112 15.397 64.392 ;
     RECT  14.789 75.696 15.397 76.584 ;
     RECT  15.361 78.96 15.397 78.984 ;
     RECT  15.361 80.112 15.397 80.232 ;
     RECT  14.749 42.48 15.433 42.888 ;
     RECT  15.433 42.48 15.469 42.984 ;
     RECT  15.397 44.112 15.469 44.616 ;
     RECT  15.397 7.44 15.685 10.728 ;
     RECT  15.361 86.736 15.829 92.52 ;
     RECT  15.685 7.344 15.865 10.728 ;
     RECT  15.361 11.76 15.865 12.936 ;
     RECT  15.397 62.064 15.865 64.392 ;
     RECT  15.217 65.52 15.865 66.696 ;
     RECT  14.713 73.968 15.865 73.992 ;
     RECT  15.397 75.696 15.865 78.984 ;
     RECT  15.361 23.28 15.901 25.8 ;
     RECT  15.397 16.176 15.937 18.024 ;
     RECT  15.901 19.056 15.937 19.08 ;
     RECT  15.901 23.28 15.937 25.992 ;
     RECT  15.469 42.48 15.937 44.616 ;
     RECT  15.865 62.064 15.937 66.696 ;
     RECT  15.865 73.968 15.937 78.984 ;
     RECT  15.397 80.112 15.937 80.424 ;
     RECT  15.865 7.344 15.973 12.936 ;
     RECT  15.937 23.184 15.973 25.992 ;
     RECT  15.937 42.48 15.973 44.712 ;
     RECT  15.325 55.248 15.973 57.096 ;
     RECT  15.937 61.968 15.973 66.696 ;
     RECT  15.937 73.968 16.477 80.424 ;
     RECT  15.937 16.176 16.513 19.08 ;
     RECT  15.397 48.528 16.513 51.336 ;
     RECT  15.973 54.48 16.513 57.096 ;
     RECT  15.973 61.488 16.513 66.696 ;
     RECT  16.477 73.968 16.513 80.52 ;
     RECT  16.513 61.392 16.801 66.696 ;
     RECT  16.801 61.392 17.089 67.368 ;
     RECT  15.361 32.208 17.125 38.28 ;
     RECT  15.829 86.736 17.125 92.712 ;
     RECT  15.973 42.192 17.161 45.096 ;
     RECT  16.513 48.432 17.161 51.336 ;
     RECT  17.125 86.64 17.161 92.712 ;
     RECT  17.125 31.92 17.237 38.28 ;
     RECT  17.161 86.64 17.237 92.808 ;
     RECT  15.973 6.864 17.244 12.936 ;
     RECT  16.513 16.08 17.244 19.08 ;
     RECT  15.973 22.992 17.244 25.992 ;
     RECT  17.237 32.208 17.244 38.28 ;
     RECT  17.161 42.192 17.244 45.192 ;
     RECT  17.161 48.24 17.244 51.336 ;
     RECT  16.513 54.48 17.244 57.48 ;
     RECT  17.089 61.392 17.244 67.464 ;
     RECT  16.513 73.68 17.244 80.52 ;
     RECT  17.237 86.736 17.244 92.808 ;
     RECT  17.244 48.24 17.273 48.264 ;
    LAYER M5 ;
     RECT  3.984 0.016 4.104 1.763 ;
     RECT  2.4 2.137 2.52 2.151 ;
     RECT  7.8 2.137 7.92 2.151 ;
     RECT  13.2 2.137 13.32 2.151 ;
     RECT  7.8 2.151 8.112 2.245 ;
     RECT  6.864 2.245 8.112 2.725 ;
     RECT  6.864 2.725 8.712 4.069 ;
     RECT  6.72 4.069 8.712 4.115 ;
     RECT  11.376 2.821 11.4 4.261 ;
     RECT  7.8 4.115 8.712 4.547 ;
     RECT  0.192 4.741 0.216 5.027 ;
     RECT  11.376 4.261 12.168 5.029 ;
     RECT  13.2 2.151 13.512 5.029 ;
     RECT  11.376 5.029 13.512 5.219 ;
     RECT  11.376 5.219 11.4 5.459 ;
     RECT  5.184 2.821 5.208 5.605 ;
     RECT  6.72 4.115 6.744 5.605 ;
     RECT  5.184 5.605 6.744 5.747 ;
     RECT  12.528 5.219 13.512 6.419 ;
     RECT  5.184 5.747 6.12 7.859 ;
     RECT  13.2 6.419 13.512 7.909 ;
     RECT  11.04 7.765 11.064 8.437 ;
     RECT  12.48 7.909 13.512 8.867 ;
     RECT  11.04 8.437 11.448 9.349 ;
     RECT  0.192 9.397 0.216 9.587 ;
     RECT  5.184 7.859 5.208 9.637 ;
     RECT  6.72 9.445 6.744 9.637 ;
     RECT  11.04 9.349 11.928 9.923 ;
     RECT  7.8 4.547 8.376 10.355 ;
     RECT  11.04 9.923 11.448 10.837 ;
     RECT  5.184 9.637 6.744 10.883 ;
     RECT  7.8 10.355 8.112 11.173 ;
     RECT  13.2 8.867 13.512 11.221 ;
     RECT  10.848 10.837 11.448 11.363 ;
     RECT  5.184 10.883 5.976 11.411 ;
     RECT  11.424 11.363 11.448 12.517 ;
     RECT  9.6 10.309 9.624 12.755 ;
     RECT  13.2 11.221 13.656 12.901 ;
     RECT  3.984 1.763 4.008 12.997 ;
     RECT  5.952 11.411 5.976 13.621 ;
     RECT  10.8 12.517 11.448 13.955 ;
     RECT  11.424 13.955 11.448 14.005 ;
     RECT  11.424 14.005 11.688 14.051 ;
     RECT  7.056 11.173 8.112 14.821 ;
     RECT  12.816 12.901 13.656 14.867 ;
     RECT  3.984 12.997 4.44 14.915 ;
     RECT  11.664 14.051 11.688 15.397 ;
     RECT  0.144 15.493 0.168 15.779 ;
     RECT  7.056 14.821 8.376 16.117 ;
     RECT  2.4 2.151 2.712 16.165 ;
     RECT  12.816 14.867 13.512 16.259 ;
     RECT  5.616 13.621 5.976 16.261 ;
     RECT  10.8 15.397 11.688 16.595 ;
     RECT  2.4 16.165 2.808 16.645 ;
     RECT  3.984 14.915 4.008 17.077 ;
     RECT  5.136 16.261 5.976 17.077 ;
     RECT  3.984 17.077 5.976 17.123 ;
     RECT  7.056 16.117 8.424 17.123 ;
     RECT  13.2 16.259 13.512 17.605 ;
     RECT  7.056 17.123 8.376 17.843 ;
     RECT  2.4 16.645 2.856 17.939 ;
     RECT  3.984 17.123 4.92 18.035 ;
     RECT  11.472 16.595 11.688 18.803 ;
     RECT  10.464 17.605 10.488 18.805 ;
     RECT  11.664 18.803 11.688 19.093 ;
     RECT  9.648 18.805 10.488 19.379 ;
     RECT  3.984 18.035 4.824 19.427 ;
     RECT  11.664 19.093 11.832 20.243 ;
     RECT  7.392 17.843 8.376 20.531 ;
     RECT  7.8 20.531 8.376 20.579 ;
     RECT  9.648 19.379 9.672 20.725 ;
     RECT  9.648 20.725 10.248 20.771 ;
     RECT  13.104 17.605 13.512 20.819 ;
     RECT  10.224 20.771 10.248 22.453 ;
     RECT  10.224 22.453 10.392 22.499 ;
     RECT  5.952 17.123 5.976 22.739 ;
     RECT  7.8 20.579 8.232 22.741 ;
     RECT  7.8 22.741 8.424 22.789 ;
     RECT  10.368 22.499 10.392 23.171 ;
     RECT  11.664 20.243 11.688 23.317 ;
     RECT  13.2 20.819 13.512 23.317 ;
     RECT  3.984 19.427 4.392 23.893 ;
     RECT  11.664 23.317 13.512 23.987 ;
     RECT  3.984 23.893 4.536 24.563 ;
     RECT  7.8 22.789 8.808 24.899 ;
     RECT  11.664 23.987 11.688 25.861 ;
     RECT  13.2 23.987 13.512 25.861 ;
     RECT  3.984 24.563 4.248 26.243 ;
     RECT  5.328 25.045 5.352 26.293 ;
     RECT  7.8 24.899 8.424 26.341 ;
     RECT  7.8 26.341 9.144 26.629 ;
     RECT  11.664 25.861 13.512 26.629 ;
     RECT  2.4 17.939 2.712 26.677 ;
     RECT  3.984 26.243 4.008 26.677 ;
     RECT  5.328 26.293 5.976 27.251 ;
     RECT  11.664 26.629 14.088 27.301 ;
     RECT  7.8 26.629 9.96 27.347 ;
     RECT  9.264 27.347 9.96 28.643 ;
     RECT  2.4 26.677 4.008 28.885 ;
     RECT  5.328 27.251 5.352 28.885 ;
     RECT  2.4 28.885 5.352 29.027 ;
     RECT  6.48 28.501 6.504 29.075 ;
     RECT  5.328 29.027 5.352 29.123 ;
     RECT  11.424 27.301 14.088 29.555 ;
     RECT  5.136 29.989 5.16 30.131 ;
     RECT  7.8 27.347 8.232 30.133 ;
     RECT  9.264 28.643 9.288 30.133 ;
     RECT  7.8 30.133 9.288 30.949 ;
     RECT  11.424 29.555 13.752 31.333 ;
     RECT  11.136 31.333 13.752 31.379 ;
     RECT  2.4 29.027 4.008 31.427 ;
     RECT  5.04 32.053 5.064 32.293 ;
     RECT  11.136 31.379 11.688 32.483 ;
     RECT  13.2 31.379 13.752 32.627 ;
     RECT  7.8 30.949 9.72 33.107 ;
     RECT  9.264 33.107 9.72 33.635 ;
     RECT  11.664 32.483 11.688 34.165 ;
     RECT  7.8 33.107 8.112 34.213 ;
     RECT  13.2 32.627 13.512 34.645 ;
     RECT  0.144 33.109 0.168 34.691 ;
     RECT  7.8 34.213 8.232 34.933 ;
     RECT  3.984 31.427 4.008 35.077 ;
     RECT  5.04 32.293 5.736 35.077 ;
     RECT  3.984 35.077 5.736 35.123 ;
     RECT  5.712 35.123 5.736 35.317 ;
     RECT  6.864 34.933 8.232 35.317 ;
     RECT  5.712 35.317 8.232 35.363 ;
     RECT  6 35.363 8.232 35.413 ;
     RECT  9.264 33.635 9.288 35.413 ;
     RECT  11.184 34.165 11.688 35.891 ;
     RECT  3.984 35.123 4.536 36.227 ;
     RECT  11.664 35.891 11.688 37.045 ;
     RECT  13.2 34.645 13.608 37.045 ;
     RECT  6 35.413 9.288 37.093 ;
     RECT  5.616 37.093 9.288 37.139 ;
     RECT  11.664 37.045 13.608 37.187 ;
     RECT  3.984 36.227 4.008 37.285 ;
     RECT  11.664 37.187 11.688 37.621 ;
     RECT  7.8 37.139 9.288 37.859 ;
     RECT  5.616 37.139 6.792 38.819 ;
     RECT  13.2 37.187 13.608 38.819 ;
     RECT  5.616 38.819 6.264 39.251 ;
     RECT  13.2 38.819 13.512 39.301 ;
     RECT  6 39.251 6.264 39.491 ;
     RECT  11.28 37.621 11.688 39.877 ;
     RECT  6.24 39.491 6.264 39.923 ;
     RECT  7.8 37.859 8.112 40.405 ;
     RECT  13.104 39.301 13.512 40.595 ;
     RECT  9.264 37.859 9.288 41.029 ;
     RECT  10.464 39.877 11.688 41.075 ;
     RECT  10.464 41.075 10.488 42.037 ;
     RECT  11.664 41.075 11.688 42.037 ;
     RECT  5.664 41.365 5.688 42.085 ;
     RECT  7.68 40.405 8.112 42.227 ;
     RECT  9.12 41.029 9.288 42.227 ;
     RECT  10.464 42.037 11.688 42.227 ;
     RECT  2.4 31.427 2.712 42.517 ;
     RECT  5.664 42.085 6.504 42.755 ;
     RECT  3.984 37.285 4.488 42.997 ;
     RECT  7.8 42.227 8.112 43.285 ;
     RECT  11.136 42.227 11.688 43.333 ;
     RECT  10.368 43.333 11.688 43.813 ;
     RECT  13.2 40.595 13.512 43.813 ;
     RECT  6.48 42.755 6.504 43.957 ;
     RECT  7.632 43.285 8.112 43.957 ;
     RECT  6.48 43.957 8.112 44.147 ;
     RECT  2.304 42.517 2.712 44.387 ;
     RECT  6.48 44.147 6.504 44.389 ;
     RECT  3.984 42.997 5.016 44.435 ;
     RECT  10.368 43.813 13.512 44.483 ;
     RECT  10.368 44.483 11.688 44.579 ;
     RECT  6.096 44.389 6.504 45.059 ;
     RECT  7.632 44.147 8.112 45.731 ;
     RECT  10.464 44.579 11.688 46.165 ;
     RECT  3.984 44.435 4.584 46.787 ;
     RECT  10.368 46.165 11.688 46.787 ;
     RECT  7.8 45.731 8.112 47.269 ;
     RECT  9.264 42.227 9.288 47.269 ;
     RECT  11.136 46.787 11.688 47.363 ;
     RECT  6.48 45.059 6.504 47.555 ;
     RECT  7.8 47.269 9.288 47.845 ;
     RECT  7.68 47.845 9.288 48.373 ;
     RECT  3.984 46.787 4.008 48.421 ;
     RECT  13.2 44.483 13.512 48.421 ;
     RECT  0.144 48.181 0.168 48.467 ;
     RECT  3.984 48.421 4.344 48.613 ;
     RECT  11.664 47.363 11.688 48.805 ;
     RECT  3.984 48.613 5.16 49.043 ;
     RECT  11.376 48.805 11.688 49.043 ;
     RECT  7.68 48.373 10.2 49.475 ;
     RECT  3.984 49.043 4.344 49.619 ;
     RECT  4.32 49.619 4.344 49.715 ;
     RECT  12.768 48.421 13.512 50.147 ;
     RECT  7.68 49.475 9.288 52.309 ;
     RECT  13.056 50.147 13.512 52.357 ;
     RECT  12.624 52.357 13.512 53.075 ;
     RECT  13.2 53.075 13.512 53.365 ;
     RECT  4.512 52.645 4.536 53.557 ;
     RECT  6.288 53.413 6.312 54.131 ;
     RECT  4.512 53.557 4.584 54.179 ;
     RECT  11.376 49.043 11.4 54.371 ;
     RECT  7.68 52.309 10.248 54.659 ;
     RECT  13.2 53.365 13.992 55.141 ;
     RECT  4.512 54.179 4.536 55.237 ;
     RECT  13.2 55.141 14.088 55.283 ;
     RECT  7.68 54.659 8.112 55.765 ;
     RECT  4.512 55.237 4.584 56.197 ;
     RECT  9.264 54.659 10.248 56.243 ;
     RECT  7.632 55.765 8.112 56.531 ;
     RECT  4.368 56.197 4.584 56.723 ;
     RECT  2.4 44.387 2.712 56.869 ;
     RECT  11.712 55.237 11.736 57.253 ;
     RECT  13.2 55.283 13.608 57.253 ;
     RECT  11.712 57.253 13.608 57.635 ;
     RECT  11.712 57.635 13.512 57.875 ;
     RECT  2.4 56.869 2.808 58.307 ;
     RECT  9.264 56.243 9.288 58.501 ;
     RECT  9.168 58.501 9.288 59.221 ;
     RECT  13.2 57.875 13.512 59.221 ;
     RECT  9.168 59.221 9.432 59.267 ;
     RECT  4.368 56.723 4.392 59.797 ;
     RECT  6.24 57.973 6.264 60.035 ;
     RECT  4.368 59.797 5.112 60.419 ;
     RECT  7.68 56.531 8.112 60.805 ;
     RECT  13.104 59.221 13.512 60.901 ;
     RECT  7.488 60.805 8.112 60.949 ;
     RECT  2.4 58.307 2.712 61.525 ;
     RECT  4.464 60.419 5.112 61.525 ;
     RECT  12.672 60.901 13.512 61.619 ;
     RECT  7.392 60.949 8.112 62.101 ;
     RECT  4.464 61.525 5.448 62.435 ;
     RECT  2.4 61.525 3.384 62.677 ;
     RECT  13.104 61.619 13.512 62.723 ;
     RECT  0.144 62.869 0.168 63.059 ;
     RECT  2.304 62.677 3.384 63.109 ;
     RECT  6.816 62.101 8.112 63.203 ;
     RECT  2.256 63.109 3.384 63.299 ;
     RECT  11.616 58.117 11.64 63.781 ;
     RECT  9.264 59.267 9.432 63.875 ;
     RECT  0.144 64.165 0.168 64.355 ;
     RECT  4.464 62.435 5.112 64.403 ;
     RECT  7.488 63.203 8.112 64.981 ;
     RECT  9.264 63.875 9.288 64.981 ;
     RECT  6.432 63.781 6.456 65.125 ;
     RECT  6.288 65.125 6.456 65.171 ;
     RECT  6.288 65.171 6.312 66.371 ;
     RECT  11.568 63.781 11.64 66.517 ;
     RECT  4.464 64.403 4.488 66.613 ;
     RECT  13.2 62.723 13.512 67.141 ;
     RECT  11.472 66.517 11.64 67.237 ;
     RECT  2.304 63.299 3.384 67.283 ;
     RECT  4.464 66.613 4.584 67.283 ;
     RECT  2.304 67.283 3.288 67.331 ;
     RECT  7.488 64.981 9.288 67.523 ;
     RECT  2.304 67.331 3.192 67.859 ;
     RECT  10.512 67.237 11.64 67.859 ;
     RECT  11.616 67.859 11.64 68.341 ;
     RECT  13.2 67.141 13.608 68.341 ;
     RECT  2.304 67.859 2.808 68.435 ;
     RECT  2.4 68.435 2.808 68.771 ;
     RECT  4.464 67.283 4.488 68.915 ;
     RECT  7.68 67.523 9.288 69.011 ;
     RECT  10.512 67.859 10.536 69.011 ;
     RECT  11.616 68.341 13.608 70.259 ;
     RECT  9.264 69.011 9.288 70.261 ;
     RECT  9.264 70.261 9.384 70.595 ;
     RECT  5.712 69.493 5.736 70.645 ;
     RECT  4.032 69.829 4.056 70.739 ;
     RECT  12.48 70.259 13.608 70.739 ;
     RECT  5.28 70.645 5.736 70.787 ;
     RECT  12.48 70.739 13.512 71.221 ;
     RECT  5.28 70.787 5.304 71.749 ;
     RECT  12.432 71.221 13.512 71.843 ;
     RECT  4.368 71.749 5.304 72.131 ;
     RECT  11.376 71.269 11.4 72.419 ;
     RECT  13.2 71.843 13.512 72.805 ;
     RECT  0.144 73.813 0.168 74.099 ;
     RECT  7.68 69.011 8.112 74.485 ;
     RECT  9.36 70.595 9.384 74.485 ;
     RECT  4.368 72.131 4.392 74.629 ;
     RECT  4.368 74.629 4.632 74.915 ;
     RECT  12.528 72.805 13.512 75.107 ;
     RECT  7.68 74.485 9.384 75.155 ;
     RECT  11.136 73.381 11.16 75.205 ;
     RECT  9.36 75.155 9.384 75.781 ;
     RECT  11.136 75.205 11.4 75.781 ;
     RECT  4.608 74.915 4.632 75.827 ;
     RECT  7.68 75.155 8.28 75.923 ;
     RECT  6.288 75.205 6.312 76.067 ;
     RECT  12.768 75.107 13.512 76.211 ;
     RECT  7.8 75.923 8.28 76.499 ;
     RECT  9.36 75.781 9.528 77.125 ;
     RECT  11.04 75.781 11.4 77.125 ;
     RECT  9.36 77.125 11.4 77.171 ;
     RECT  11.376 77.171 11.4 77.555 ;
     RECT  4.56 76.069 4.584 77.941 ;
     RECT  4.032 77.941 4.584 77.987 ;
     RECT  6.336 76.117 6.36 78.037 ;
     RECT  9.36 77.171 10.248 78.131 ;
     RECT  9.36 78.131 9.528 78.371 ;
     RECT  6.096 78.037 6.36 79.189 ;
     RECT  7.8 76.499 8.112 79.189 ;
     RECT  13.2 76.211 13.512 79.189 ;
     RECT  6.096 79.189 8.112 79.619 ;
     RECT  6.336 79.619 8.112 80.243 ;
     RECT  11.376 79.045 11.4 80.435 ;
     RECT  9.36 78.371 9.384 81.205 ;
     RECT  6.336 80.243 6.36 81.877 ;
     RECT  7.44 80.243 8.112 82.019 ;
     RECT  13.104 79.189 13.512 82.021 ;
     RECT  13.104 82.021 13.848 82.261 ;
     RECT  12.576 82.261 13.848 83.077 ;
     RECT  12.576 83.077 13.896 83.123 ;
     RECT  9.216 81.205 9.384 83.173 ;
     RECT  2.4 68.771 2.712 83.749 ;
     RECT  9.12 83.173 9.384 83.843 ;
     RECT  5.568 81.877 6.36 84.035 ;
     RECT  0.144 83.893 0.168 84.083 ;
     RECT  2.304 83.749 2.712 84.613 ;
     RECT  2.304 84.613 2.904 84.899 ;
     RECT  5.808 84.035 6.36 84.901 ;
     RECT  7.8 82.019 8.112 84.901 ;
     RECT  4.032 77.987 4.056 85.333 ;
     RECT  4.032 85.333 4.488 85.379 ;
     RECT  4.464 85.379 4.488 85.621 ;
     RECT  5.808 84.901 8.112 85.621 ;
     RECT  4.464 85.621 8.112 85.667 ;
     RECT  6.336 85.667 8.112 85.765 ;
     RECT  9.36 83.843 9.384 85.765 ;
     RECT  11.856 84.661 11.88 85.765 ;
     RECT  13.104 83.123 13.896 85.765 ;
     RECT  11.856 85.765 13.896 85.955 ;
     RECT  10.848 84.181 10.872 86.195 ;
     RECT  6.336 85.765 9.384 86.435 ;
     RECT  12.528 85.955 13.896 86.675 ;
     RECT  4.464 85.667 5.112 86.771 ;
     RECT  7.8 86.435 8.52 87.539 ;
     RECT  2.4 84.899 2.904 87.637 ;
     RECT  12.528 86.675 13.512 87.685 ;
     RECT  5.088 86.771 5.112 87.733 ;
     RECT  10.512 86.389 10.536 87.733 ;
     RECT  2.4 87.637 3 87.925 ;
     RECT  2.304 87.925 3 88.117 ;
     RECT  4.368 87.733 5.112 88.451 ;
     RECT  6.336 86.435 6.36 88.597 ;
     RECT  7.8 87.539 8.112 88.597 ;
     RECT  6.336 88.597 8.112 88.835 ;
     RECT  2.304 88.117 3.096 88.883 ;
     RECT  10.512 87.733 10.968 89.507 ;
     RECT  4.368 88.451 4.392 89.893 ;
     RECT  7.248 88.835 8.112 89.941 ;
     RECT  10.512 89.507 10.536 90.083 ;
     RECT  6.864 89.941 8.112 90.563 ;
     RECT  4.368 89.893 4.776 90.757 ;
     RECT  2.304 88.883 3 91.285 ;
     RECT  4.368 90.757 5.208 91.285 ;
     RECT  2.304 91.285 5.208 91.331 ;
     RECT  2.304 91.331 4.056 91.427 ;
     RECT  12.528 87.685 13.8 91.811 ;
     RECT  2.4 91.427 4.056 91.859 ;
     RECT  5.184 91.331 5.208 92.099 ;
     RECT  10.512 91.189 10.536 92.147 ;
     RECT  9.504 91.573 9.528 92.387 ;
     RECT  7.056 90.563 8.112 92.533 ;
     RECT  2.4 91.859 3.288 92.675 ;
     RECT  7.056 92.533 8.376 92.723 ;
     RECT  12.528 91.811 13.512 93.539 ;
     RECT  7.8 92.723 8.376 93.779 ;
     RECT  9.648 92.917 9.672 93.779 ;
     RECT  2.4 92.675 3.096 94.307 ;
     RECT  2.4 94.307 2.712 95.049 ;
     RECT  7.8 93.779 8.112 95.049 ;
     RECT  13.2 93.539 13.512 95.049 ;
     RECT  2.4 95.049 2.52 95.063 ;
     RECT  7.8 95.049 7.92 95.063 ;
     RECT  13.2 95.049 13.32 95.063 ;
     RECT  4.008 1.763 4.104 2.821 ;
     RECT  2.52 2.137 3.984 2.151 ;
     RECT  2.712 2.151 3.984 16.165 ;
     RECT  4.008 2.821 5.184 11.411 ;
     RECT  5.208 4.069 6.72 5.605 ;
     RECT  6.744 4.115 7.8 5.747 ;
     RECT  12.168 4.261 13.2 5.029 ;
     RECT  11.4 5.219 12.528 5.459 ;
     RECT  12.528 6.419 13.2 7.765 ;
     RECT  11.064 7.765 13.2 7.909 ;
     RECT  11.064 7.909 12.48 8.437 ;
     RECT  11.448 8.437 12.48 8.867 ;
     RECT  11.448 8.867 13.2 9.349 ;
     RECT  11.928 9.349 13.2 9.923 ;
     RECT  5.208 9.445 6.72 9.637 ;
     RECT  6.744 9.445 7.8 10.883 ;
     RECT  8.376 10.309 9.6 10.355 ;
     RECT  9.624 10.309 11.04 10.837 ;
     RECT  8.112 10.355 9.6 12.755 ;
     RECT  9.624 10.837 10.848 11.363 ;
     RECT  5.976 10.883 7.8 11.173 ;
     RECT  5.976 11.173 7.056 17.843 ;
     RECT  9.624 11.363 11.424 12.517 ;
     RECT  9.624 12.517 10.8 12.755 ;
     RECT  11.448 12.901 12.816 14.005 ;
     RECT  4.44 12.997 5.952 13.621 ;
     RECT  4.44 13.621 5.616 14.915 ;
     RECT  10.8 13.955 11.424 14.051 ;
     RECT  11.688 14.005 12.816 16.259 ;
     RECT  10.8 14.051 11.664 15.397 ;
     RECT  4.008 14.915 5.616 16.261 ;
     RECT  2.808 16.165 3.984 16.645 ;
     RECT  11.688 16.259 13.2 17.605 ;
     RECT  4.008 16.261 5.136 17.077 ;
     RECT  10.8 16.595 11.472 17.605 ;
     RECT  2.856 16.645 3.984 17.939 ;
     RECT  4.92 17.123 5.952 18.035 ;
     RECT  10.488 17.605 11.472 18.803 ;
     RECT  11.688 17.605 13.104 19.093 ;
     RECT  5.976 17.843 7.392 20.531 ;
     RECT  2.712 17.939 3.984 26.677 ;
     RECT  4.824 18.035 5.952 19.427 ;
     RECT  10.488 18.803 11.664 19.379 ;
     RECT  8.376 18.805 9.648 20.579 ;
     RECT  11.832 19.093 13.104 20.243 ;
     RECT  9.672 19.379 11.664 20.725 ;
     RECT  11.688 20.243 13.104 20.819 ;
     RECT  8.232 20.579 9.648 20.771 ;
     RECT  10.248 20.725 11.664 22.453 ;
     RECT  11.688 20.819 13.2 23.317 ;
     RECT  10.392 22.453 11.664 23.171 ;
     RECT  11.688 23.987 13.2 25.861 ;
     RECT  4.248 24.563 4.536 25.045 ;
     RECT  8.424 24.899 8.808 26.341 ;
     RECT  4.248 25.045 5.328 26.243 ;
     RECT  4.008 26.243 5.328 28.885 ;
     RECT  5.352 27.251 5.976 28.501 ;
     RECT  9.96 27.301 11.424 28.643 ;
     RECT  8.232 27.347 9.264 30.133 ;
     RECT  5.352 28.501 6.48 29.075 ;
     RECT  6.504 28.501 7.8 29.075 ;
     RECT  4.008 29.027 5.328 29.123 ;
     RECT  4.008 29.123 5.16 29.989 ;
     RECT  4.008 29.989 5.136 30.131 ;
     RECT  9.72 31.333 11.136 32.483 ;
     RECT  11.688 31.379 13.2 37.045 ;
     RECT  2.712 31.427 3.984 49.619 ;
     RECT  4.008 32.053 5.04 35.077 ;
     RECT  8.112 33.107 9.264 34.213 ;
     RECT  8.232 34.213 9.264 35.413 ;
     RECT  5.736 34.933 6.864 35.317 ;
     RECT  4.536 35.123 5.712 35.363 ;
     RECT  4.536 35.363 6 36.227 ;
     RECT  4.008 36.227 6 37.093 ;
     RECT  4.008 37.093 5.616 37.285 ;
     RECT  6.792 37.139 7.8 38.819 ;
     RECT  11.688 37.187 13.2 39.301 ;
     RECT  4.488 37.285 5.616 39.251 ;
     RECT  8.112 37.859 9.264 41.029 ;
     RECT  4.488 39.251 6 39.491 ;
     RECT  11.688 39.301 13.104 40.595 ;
     RECT  9.288 39.877 10.464 42.227 ;
     RECT  11.688 40.595 13.2 43.813 ;
     RECT  8.112 41.029 9.12 42.227 ;
     RECT  10.488 41.075 11.664 42.037 ;
     RECT  4.488 41.365 5.664 42.755 ;
     RECT  6.504 42.085 7.68 42.227 ;
     RECT  6.504 42.227 7.8 43.285 ;
     RECT  8.112 42.227 9.264 47.269 ;
     RECT  9.288 42.227 11.136 43.333 ;
     RECT  4.488 42.755 6.48 42.997 ;
     RECT  5.016 42.997 6.48 44.389 ;
     RECT  6.504 43.285 7.632 43.957 ;
     RECT  9.288 43.333 10.368 44.579 ;
     RECT  6.504 44.147 7.632 45.731 ;
     RECT  5.016 44.389 6.096 44.435 ;
     RECT  4.584 44.435 6.096 45.059 ;
     RECT  11.688 44.483 13.2 48.421 ;
     RECT  9.288 44.579 10.464 46.165 ;
     RECT  6.504 45.731 7.8 47.555 ;
     RECT  9.288 46.165 10.368 46.787 ;
     RECT  11.136 47.363 11.664 48.373 ;
     RECT  7.68 47.555 7.8 47.845 ;
     RECT  10.2 48.373 11.664 48.805 ;
     RECT  11.688 48.421 12.768 49.043 ;
     RECT  10.2 48.805 11.376 49.475 ;
     RECT  11.4 49.043 12.768 50.147 ;
     RECT  10.248 52.309 11.376 54.371 ;
     RECT  11.4 52.357 12.624 53.075 ;
     RECT  6.312 53.413 7.68 54.131 ;
     RECT  4.536 54.179 4.584 55.237 ;
     RECT  10.248 54.371 11.4 55.237 ;
     RECT  8.112 54.659 9.264 58.501 ;
     RECT  10.248 55.237 11.712 56.243 ;
     RECT  11.736 55.237 13.2 57.253 ;
     RECT  7.632 56.531 7.68 57.973 ;
     RECT  11.712 57.875 13.2 58.117 ;
     RECT  6.264 57.973 7.68 60.035 ;
     RECT  11.64 58.117 13.2 59.221 ;
     RECT  8.112 58.501 9.168 59.267 ;
     RECT  11.64 59.221 13.104 60.901 ;
     RECT  8.112 59.267 9.264 64.981 ;
     RECT  5.112 59.797 6.24 60.035 ;
     RECT  5.112 60.035 5.448 61.525 ;
     RECT  7.392 60.035 7.68 60.805 ;
     RECT  4.368 60.419 4.464 61.525 ;
     RECT  7.392 60.805 7.488 60.949 ;
     RECT  11.64 60.901 12.672 61.619 ;
     RECT  3.384 61.525 4.464 67.283 ;
     RECT  11.64 61.619 13.104 62.723 ;
     RECT  5.448 62.101 6.816 62.435 ;
     RECT  5.112 62.435 6.816 63.203 ;
     RECT  0.144 63.059 0.168 64.165 ;
     RECT  5.112 63.203 7.488 63.781 ;
     RECT  5.112 63.781 6.432 64.403 ;
     RECT  6.456 63.781 7.488 65.171 ;
     RECT  6.288 64.403 6.432 65.125 ;
     RECT  6.312 65.171 7.488 66.371 ;
     RECT  9.288 67.237 10.512 69.011 ;
     RECT  3.288 67.283 4.464 67.331 ;
     RECT  3.192 67.331 4.464 67.859 ;
     RECT  10.536 67.859 11.616 69.011 ;
     RECT  2.712 68.771 2.808 69.829 ;
     RECT  8.112 69.011 9.264 70.595 ;
     RECT  9.288 69.011 9.384 70.261 ;
     RECT  2.712 69.829 4.032 70.739 ;
     RECT  11.616 70.259 12.48 71.221 ;
     RECT  8.112 70.595 9.36 74.485 ;
     RECT  4.056 70.645 5.28 70.739 ;
     RECT  4.368 70.739 5.28 71.749 ;
     RECT  11.616 71.221 12.432 71.269 ;
     RECT  11.4 71.269 12.432 71.843 ;
     RECT  11.4 71.843 13.2 72.419 ;
     RECT  11.376 72.419 13.2 72.805 ;
     RECT  11.376 72.805 12.528 73.381 ;
     RECT  11.16 73.381 12.528 75.107 ;
     RECT  4.56 74.915 4.608 75.827 ;
     RECT  11.16 75.107 12.768 75.205 ;
     RECT  8.28 75.155 9.36 76.499 ;
     RECT  6.312 75.205 7.68 75.923 ;
     RECT  11.4 75.205 12.768 76.211 ;
     RECT  9.528 75.781 11.04 77.125 ;
     RECT  4.56 75.827 4.584 76.069 ;
     RECT  6.312 75.923 7.8 76.067 ;
     RECT  6.336 76.067 7.8 76.117 ;
     RECT  6.36 76.117 7.8 79.189 ;
     RECT  8.112 76.499 9.36 81.205 ;
     RECT  10.248 77.171 11.376 77.555 ;
     RECT  10.248 77.555 11.4 78.131 ;
     RECT  2.712 77.941 4.032 84.613 ;
     RECT  11.376 78.131 11.4 79.045 ;
     RECT  6.36 80.243 7.44 82.019 ;
     RECT  8.112 81.205 9.216 83.173 ;
     RECT  4.056 81.877 5.568 84.035 ;
     RECT  6.36 82.019 7.8 84.901 ;
     RECT  8.112 83.173 9.12 83.843 ;
     RECT  8.112 83.843 9.36 85.765 ;
     RECT  4.056 84.035 5.808 85.333 ;
     RECT  9.384 84.181 10.848 86.195 ;
     RECT  2.904 84.613 4.032 85.379 ;
     RECT  10.872 84.661 11.856 85.955 ;
     RECT  11.88 84.661 13.104 85.765 ;
     RECT  4.488 85.333 5.808 85.621 ;
     RECT  5.112 85.667 6.336 88.451 ;
     RECT  9.384 86.195 10.536 86.389 ;
     RECT  9.384 86.389 10.512 86.435 ;
     RECT  6.36 86.435 7.8 88.597 ;
     RECT  13.512 86.675 13.8 87.685 ;
     RECT  4.464 86.771 5.088 87.637 ;
     RECT  3 87.637 5.088 87.733 ;
     RECT  3 87.733 4.368 88.117 ;
     RECT  3.096 88.117 4.368 88.883 ;
     RECT  4.392 88.451 4.776 89.893 ;
     RECT  6.864 88.835 7.248 89.941 ;
     RECT  3 88.883 4.368 91.285 ;
     RECT  10.512 90.083 10.536 91.189 ;
     RECT  4.056 91.331 5.184 91.859 ;
     RECT  8.112 91.573 9.504 92.387 ;
     RECT  9.528 91.573 10.512 92.147 ;
     RECT  9.528 92.147 9.672 92.387 ;
     RECT  8.112 92.387 9.672 92.533 ;
     RECT  8.376 92.533 9.672 92.917 ;
     RECT  8.376 92.917 9.648 93.779 ;
  END
END ot_qfd_vm_xpad2_t
END LIBRARY
